VERSION 5.8 ;
BUSBITCHARS "[]" ;
DIVIDERCHAR "/" ;
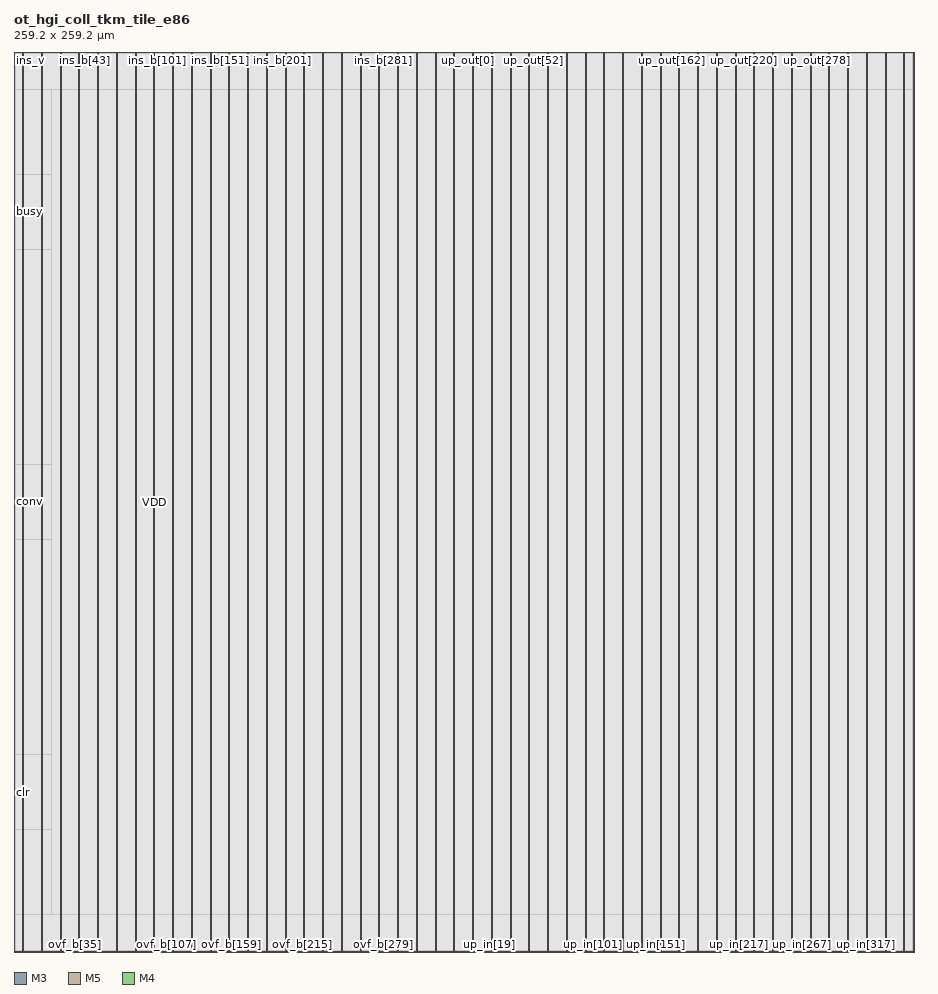
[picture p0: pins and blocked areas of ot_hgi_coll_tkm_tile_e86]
MACRO ot_hgi_coll_tkm_tile_e86
  CLASS BLOCK ;
  ORIGIN 0 0 ;
  FOREIGN ot_hgi_coll_tkm_tile_e86 0 0 ;
  SIZE 259.2 BY 259.2 ;
  SYMMETRY X Y ;
  PIN ins_v
    DIRECTION INPUT ;
    USE SIGNAL ;
    PORT
      LAYER M3 ;
        RECT 4.500 259.056 4.518 259.200 ;
    END
  END ins_v
  PIN ins_b[0]
    DIRECTION INPUT ;
    USE SIGNAL ;
    PORT
      LAYER M5 ;
        RECT 4.848 259.008 4.872 259.200 ;
    END
  END ins_b[0]
  PIN ins_b[1]
    DIRECTION INPUT ;
    USE SIGNAL ;
    PORT
      LAYER M3 ;
        RECT 5.220 259.056 5.238 259.200 ;
    END
  END ins_b[1]
  PIN ins_b[2]
    DIRECTION INPUT ;
    USE SIGNAL ;
    PORT
      LAYER M5 ;
        RECT 5.568 259.008 5.592 259.200 ;
    END
  END ins_b[2]
  PIN ins_b[3]
    DIRECTION INPUT ;
    USE SIGNAL ;
    PORT
      LAYER M3 ;
        RECT 5.940 259.056 5.958 259.200 ;
    END
  END ins_b[3]
  PIN ins_b[4]
    DIRECTION INPUT ;
    USE SIGNAL ;
    PORT
      LAYER M5 ;
        RECT 6.288 259.008 6.312 259.200 ;
    END
  END ins_b[4]
  PIN ins_b[5]
    DIRECTION INPUT ;
    USE SIGNAL ;
    PORT
      LAYER M3 ;
        RECT 6.660 259.056 6.678 259.200 ;
    END
  END ins_b[5]
  PIN ins_b[6]
    DIRECTION INPUT ;
    USE SIGNAL ;
    PORT
      LAYER M5 ;
        RECT 7.008 259.008 7.032 259.200 ;
    END
  END ins_b[6]
  PIN ins_b[7]
    DIRECTION INPUT ;
    USE SIGNAL ;
    PORT
      LAYER M3 ;
        RECT 7.380 259.056 7.398 259.200 ;
    END
  END ins_b[7]
  PIN ins_b[8]
    DIRECTION INPUT ;
    USE SIGNAL ;
    PORT
      LAYER M5 ;
        RECT 7.728 259.008 7.752 259.200 ;
    END
  END ins_b[8]
  PIN ins_b[9]
    DIRECTION INPUT ;
    USE SIGNAL ;
    PORT
      LAYER M3 ;
        RECT 8.100 259.056 8.118 259.200 ;
    END
  END ins_b[9]
  PIN ins_b[10]
    DIRECTION INPUT ;
    USE SIGNAL ;
    PORT
      LAYER M5 ;
        RECT 8.448 259.008 8.472 259.200 ;
    END
  END ins_b[10]
  PIN ins_b[11]
    DIRECTION INPUT ;
    USE SIGNAL ;
    PORT
      LAYER M3 ;
        RECT 8.820 259.056 8.838 259.200 ;
    END
  END ins_b[11]
  PIN ins_b[12]
    DIRECTION INPUT ;
    USE SIGNAL ;
    PORT
      LAYER M5 ;
        RECT 9.168 259.008 9.192 259.200 ;
    END
  END ins_b[12]
  PIN ins_b[13]
    DIRECTION INPUT ;
    USE SIGNAL ;
    PORT
      LAYER M3 ;
        RECT 9.540 259.056 9.558 259.200 ;
    END
  END ins_b[13]
  PIN ins_b[14]
    DIRECTION INPUT ;
    USE SIGNAL ;
    PORT
      LAYER M5 ;
        RECT 9.888 259.008 9.912 259.200 ;
    END
  END ins_b[14]
  PIN ins_b[15]
    DIRECTION INPUT ;
    USE SIGNAL ;
    PORT
      LAYER M3 ;
        RECT 10.260 259.056 10.278 259.200 ;
    END
  END ins_b[15]
  PIN ins_b[16]
    DIRECTION INPUT ;
    USE SIGNAL ;
    PORT
      LAYER M5 ;
        RECT 10.608 259.008 10.632 259.200 ;
    END
  END ins_b[16]
  PIN ins_b[17]
    DIRECTION INPUT ;
    USE SIGNAL ;
    PORT
      LAYER M3 ;
        RECT 10.980 259.056 10.998 259.200 ;
    END
  END ins_b[17]
  PIN ins_b[18]
    DIRECTION INPUT ;
    USE SIGNAL ;
    PORT
      LAYER M5 ;
        RECT 11.328 259.008 11.352 259.200 ;
    END
  END ins_b[18]
  PIN ins_b[19]
    DIRECTION INPUT ;
    USE SIGNAL ;
    PORT
      LAYER M3 ;
        RECT 11.700 259.056 11.718 259.200 ;
    END
  END ins_b[19]
  PIN ins_b[20]
    DIRECTION INPUT ;
    USE SIGNAL ;
    PORT
      LAYER M5 ;
        RECT 12.048 259.008 12.072 259.200 ;
    END
  END ins_b[20]
  PIN ins_b[21]
    DIRECTION INPUT ;
    USE SIGNAL ;
    PORT
      LAYER M3 ;
        RECT 12.420 259.056 12.438 259.200 ;
    END
  END ins_b[21]
  PIN ins_b[22]
    DIRECTION INPUT ;
    USE SIGNAL ;
    PORT
      LAYER M5 ;
        RECT 12.816 259.008 12.840 259.200 ;
    END
  END ins_b[22]
  PIN ins_b[23]
    DIRECTION INPUT ;
    USE SIGNAL ;
    PORT
      LAYER M3 ;
        RECT 13.140 259.056 13.158 259.200 ;
    END
  END ins_b[23]
  PIN ins_b[24]
    DIRECTION INPUT ;
    USE SIGNAL ;
    PORT
      LAYER M5 ;
        RECT 13.536 259.008 13.560 259.200 ;
    END
  END ins_b[24]
  PIN ins_b[25]
    DIRECTION INPUT ;
    USE SIGNAL ;
    PORT
      LAYER M3 ;
        RECT 13.896 259.056 13.914 259.200 ;
    END
  END ins_b[25]
  PIN ins_b[26]
    DIRECTION INPUT ;
    USE SIGNAL ;
    PORT
      LAYER M5 ;
        RECT 14.256 259.008 14.280 259.200 ;
    END
  END ins_b[26]
  PIN ins_b[27]
    DIRECTION INPUT ;
    USE SIGNAL ;
    PORT
      LAYER M3 ;
        RECT 14.616 259.056 14.634 259.200 ;
    END
  END ins_b[27]
  PIN ins_b[28]
    DIRECTION INPUT ;
    USE SIGNAL ;
    PORT
      LAYER M5 ;
        RECT 14.976 259.008 15.000 259.200 ;
    END
  END ins_b[28]
  PIN ins_b[29]
    DIRECTION INPUT ;
    USE SIGNAL ;
    PORT
      LAYER M3 ;
        RECT 15.336 259.056 15.354 259.200 ;
    END
  END ins_b[29]
  PIN ins_b[30]
    DIRECTION INPUT ;
    USE SIGNAL ;
    PORT
      LAYER M5 ;
        RECT 15.696 259.008 15.720 259.200 ;
    END
  END ins_b[30]
  PIN ins_b[31]
    DIRECTION INPUT ;
    USE SIGNAL ;
    PORT
      LAYER M3 ;
        RECT 16.056 259.056 16.074 259.200 ;
    END
  END ins_b[31]
  PIN ins_b[32]
    DIRECTION INPUT ;
    USE SIGNAL ;
    PORT
      LAYER M5 ;
        RECT 16.416 259.008 16.440 259.200 ;
    END
  END ins_b[32]
  PIN ins_b[33]
    DIRECTION INPUT ;
    USE SIGNAL ;
    PORT
      LAYER M3 ;
        RECT 16.776 259.056 16.794 259.200 ;
    END
  END ins_b[33]
  PIN ins_b[34]
    DIRECTION INPUT ;
    USE SIGNAL ;
    PORT
      LAYER M5 ;
        RECT 17.136 259.008 17.160 259.200 ;
    END
  END ins_b[34]
  PIN ins_b[35]
    DIRECTION INPUT ;
    USE SIGNAL ;
    PORT
      LAYER M3 ;
        RECT 17.496 259.056 17.514 259.200 ;
    END
  END ins_b[35]
  PIN ins_b[36]
    DIRECTION INPUT ;
    USE SIGNAL ;
    PORT
      LAYER M5 ;
        RECT 17.856 259.008 17.880 259.200 ;
    END
  END ins_b[36]
  PIN ins_b[37]
    DIRECTION INPUT ;
    USE SIGNAL ;
    PORT
      LAYER M3 ;
        RECT 18.216 259.056 18.234 259.200 ;
    END
  END ins_b[37]
  PIN ins_b[38]
    DIRECTION INPUT ;
    USE SIGNAL ;
    PORT
      LAYER M5 ;
        RECT 18.576 259.008 18.600 259.200 ;
    END
  END ins_b[38]
  PIN ins_b[39]
    DIRECTION INPUT ;
    USE SIGNAL ;
    PORT
      LAYER M3 ;
        RECT 18.936 259.056 18.954 259.200 ;
    END
  END ins_b[39]
  PIN ins_b[40]
    DIRECTION INPUT ;
    USE SIGNAL ;
    PORT
      LAYER M5 ;
        RECT 19.296 259.008 19.320 259.200 ;
    END
  END ins_b[40]
  PIN ins_b[41]
    DIRECTION INPUT ;
    USE SIGNAL ;
    PORT
      LAYER M3 ;
        RECT 19.656 259.056 19.674 259.200 ;
    END
  END ins_b[41]
  PIN ins_b[42]
    DIRECTION INPUT ;
    USE SIGNAL ;
    PORT
      LAYER M5 ;
        RECT 20.016 259.008 20.040 259.200 ;
    END
  END ins_b[42]
  PIN ins_b[43]
    DIRECTION INPUT ;
    USE SIGNAL ;
    PORT
      LAYER M3 ;
        RECT 20.376 259.056 20.394 259.200 ;
    END
  END ins_b[43]
  PIN ins_b[44]
    DIRECTION INPUT ;
    USE SIGNAL ;
    PORT
      LAYER M5 ;
        RECT 20.736 259.008 20.760 259.200 ;
    END
  END ins_b[44]
  PIN ins_b[45]
    DIRECTION INPUT ;
    USE SIGNAL ;
    PORT
      LAYER M3 ;
        RECT 21.096 259.056 21.114 259.200 ;
    END
  END ins_b[45]
  PIN ins_b[46]
    DIRECTION INPUT ;
    USE SIGNAL ;
    PORT
      LAYER M5 ;
        RECT 21.456 259.008 21.480 259.200 ;
    END
  END ins_b[46]
  PIN ins_b[47]
    DIRECTION INPUT ;
    USE SIGNAL ;
    PORT
      LAYER M3 ;
        RECT 21.816 259.056 21.834 259.200 ;
    END
  END ins_b[47]
  PIN ins_b[48]
    DIRECTION INPUT ;
    USE SIGNAL ;
    PORT
      LAYER M5 ;
        RECT 22.176 259.008 22.200 259.200 ;
    END
  END ins_b[48]
  PIN ins_b[49]
    DIRECTION INPUT ;
    USE SIGNAL ;
    PORT
      LAYER M3 ;
        RECT 22.536 259.056 22.554 259.200 ;
    END
  END ins_b[49]
  PIN ins_b[50]
    DIRECTION INPUT ;
    USE SIGNAL ;
    PORT
      LAYER M5 ;
        RECT 22.896 259.008 22.920 259.200 ;
    END
  END ins_b[50]
  PIN ins_b[51]
    DIRECTION INPUT ;
    USE SIGNAL ;
    PORT
      LAYER M3 ;
        RECT 23.256 259.056 23.274 259.200 ;
    END
  END ins_b[51]
  PIN ins_b[52]
    DIRECTION INPUT ;
    USE SIGNAL ;
    PORT
      LAYER M5 ;
        RECT 23.616 259.008 23.640 259.200 ;
    END
  END ins_b[52]
  PIN ins_b[53]
    DIRECTION INPUT ;
    USE SIGNAL ;
    PORT
      LAYER M3 ;
        RECT 23.976 259.056 23.994 259.200 ;
    END
  END ins_b[53]
  PIN ins_b[54]
    DIRECTION INPUT ;
    USE SIGNAL ;
    PORT
      LAYER M5 ;
        RECT 24.336 259.008 24.360 259.200 ;
    END
  END ins_b[54]
  PIN ins_b[55]
    DIRECTION INPUT ;
    USE SIGNAL ;
    PORT
      LAYER M3 ;
        RECT 24.696 259.056 24.714 259.200 ;
    END
  END ins_b[55]
  PIN ins_b[56]
    DIRECTION INPUT ;
    USE SIGNAL ;
    PORT
      LAYER M5 ;
        RECT 25.056 259.008 25.080 259.200 ;
    END
  END ins_b[56]
  PIN ins_b[57]
    DIRECTION INPUT ;
    USE SIGNAL ;
    PORT
      LAYER M3 ;
        RECT 25.416 259.056 25.434 259.200 ;
    END
  END ins_b[57]
  PIN ins_b[58]
    DIRECTION INPUT ;
    USE SIGNAL ;
    PORT
      LAYER M5 ;
        RECT 25.776 259.008 25.800 259.200 ;
    END
  END ins_b[58]
  PIN ins_b[59]
    DIRECTION INPUT ;
    USE SIGNAL ;
    PORT
      LAYER M3 ;
        RECT 26.136 259.056 26.154 259.200 ;
    END
  END ins_b[59]
  PIN ins_b[60]
    DIRECTION INPUT ;
    USE SIGNAL ;
    PORT
      LAYER M5 ;
        RECT 26.496 259.008 26.520 259.200 ;
    END
  END ins_b[60]
  PIN ins_b[61]
    DIRECTION INPUT ;
    USE SIGNAL ;
    PORT
      LAYER M3 ;
        RECT 26.892 259.056 26.910 259.200 ;
    END
  END ins_b[61]
  PIN ins_b[62]
    DIRECTION INPUT ;
    USE SIGNAL ;
    PORT
      LAYER M5 ;
        RECT 27.216 259.008 27.240 259.200 ;
    END
  END ins_b[62]
  PIN ins_b[63]
    DIRECTION INPUT ;
    USE SIGNAL ;
    PORT
      LAYER M3 ;
        RECT 27.612 259.056 27.630 259.200 ;
    END
  END ins_b[63]
  PIN ins_b[64]
    DIRECTION INPUT ;
    USE SIGNAL ;
    PORT
      LAYER M5 ;
        RECT 27.936 259.008 27.960 259.200 ;
    END
  END ins_b[64]
  PIN ins_b[65]
    DIRECTION INPUT ;
    USE SIGNAL ;
    PORT
      LAYER M3 ;
        RECT 28.332 259.056 28.350 259.200 ;
    END
  END ins_b[65]
  PIN ins_b[66]
    DIRECTION INPUT ;
    USE SIGNAL ;
    PORT
      LAYER M5 ;
        RECT 28.656 259.008 28.680 259.200 ;
    END
  END ins_b[66]
  PIN ins_b[67]
    DIRECTION INPUT ;
    USE SIGNAL ;
    PORT
      LAYER M3 ;
        RECT 29.052 259.056 29.070 259.200 ;
    END
  END ins_b[67]
  PIN ins_b[68]
    DIRECTION INPUT ;
    USE SIGNAL ;
    PORT
      LAYER M5 ;
        RECT 29.424 259.008 29.448 259.200 ;
    END
  END ins_b[68]
  PIN ins_b[69]
    DIRECTION INPUT ;
    USE SIGNAL ;
    PORT
      LAYER M3 ;
        RECT 29.772 259.056 29.790 259.200 ;
    END
  END ins_b[69]
  PIN ins_b[70]
    DIRECTION INPUT ;
    USE SIGNAL ;
    PORT
      LAYER M5 ;
        RECT 30.144 259.008 30.168 259.200 ;
    END
  END ins_b[70]
  PIN ins_b[71]
    DIRECTION INPUT ;
    USE SIGNAL ;
    PORT
      LAYER M3 ;
        RECT 30.492 259.056 30.510 259.200 ;
    END
  END ins_b[71]
  PIN ins_b[72]
    DIRECTION INPUT ;
    USE SIGNAL ;
    PORT
      LAYER M5 ;
        RECT 30.864 259.008 30.888 259.200 ;
    END
  END ins_b[72]
  PIN ins_b[73]
    DIRECTION INPUT ;
    USE SIGNAL ;
    PORT
      LAYER M3 ;
        RECT 31.212 259.056 31.230 259.200 ;
    END
  END ins_b[73]
  PIN ins_b[74]
    DIRECTION INPUT ;
    USE SIGNAL ;
    PORT
      LAYER M5 ;
        RECT 31.584 259.008 31.608 259.200 ;
    END
  END ins_b[74]
  PIN ins_b[75]
    DIRECTION INPUT ;
    USE SIGNAL ;
    PORT
      LAYER M3 ;
        RECT 31.932 259.056 31.950 259.200 ;
    END
  END ins_b[75]
  PIN ins_b[76]
    DIRECTION INPUT ;
    USE SIGNAL ;
    PORT
      LAYER M5 ;
        RECT 32.304 259.008 32.328 259.200 ;
    END
  END ins_b[76]
  PIN ins_b[77]
    DIRECTION INPUT ;
    USE SIGNAL ;
    PORT
      LAYER M3 ;
        RECT 32.652 259.056 32.670 259.200 ;
    END
  END ins_b[77]
  PIN ins_b[78]
    DIRECTION INPUT ;
    USE SIGNAL ;
    PORT
      LAYER M5 ;
        RECT 33.024 259.008 33.048 259.200 ;
    END
  END ins_b[78]
  PIN ins_b[79]
    DIRECTION INPUT ;
    USE SIGNAL ;
    PORT
      LAYER M3 ;
        RECT 33.372 259.056 33.390 259.200 ;
    END
  END ins_b[79]
  PIN ins_b[80]
    DIRECTION INPUT ;
    USE SIGNAL ;
    PORT
      LAYER M5 ;
        RECT 33.744 259.008 33.768 259.200 ;
    END
  END ins_b[80]
  PIN ins_b[81]
    DIRECTION INPUT ;
    USE SIGNAL ;
    PORT
      LAYER M3 ;
        RECT 34.092 259.056 34.110 259.200 ;
    END
  END ins_b[81]
  PIN ins_b[82]
    DIRECTION INPUT ;
    USE SIGNAL ;
    PORT
      LAYER M5 ;
        RECT 34.464 259.008 34.488 259.200 ;
    END
  END ins_b[82]
  PIN ins_b[83]
    DIRECTION INPUT ;
    USE SIGNAL ;
    PORT
      LAYER M3 ;
        RECT 34.812 259.056 34.830 259.200 ;
    END
  END ins_b[83]
  PIN ins_b[84]
    DIRECTION INPUT ;
    USE SIGNAL ;
    PORT
      LAYER M5 ;
        RECT 35.184 259.008 35.208 259.200 ;
    END
  END ins_b[84]
  PIN ins_b[85]
    DIRECTION INPUT ;
    USE SIGNAL ;
    PORT
      LAYER M3 ;
        RECT 35.532 259.056 35.550 259.200 ;
    END
  END ins_b[85]
  PIN ins_b[86]
    DIRECTION INPUT ;
    USE SIGNAL ;
    PORT
      LAYER M5 ;
        RECT 35.904 259.008 35.928 259.200 ;
    END
  END ins_b[86]
  PIN ins_b[87]
    DIRECTION INPUT ;
    USE SIGNAL ;
    PORT
      LAYER M3 ;
        RECT 36.252 259.056 36.270 259.200 ;
    END
  END ins_b[87]
  PIN ins_b[88]
    DIRECTION INPUT ;
    USE SIGNAL ;
    PORT
      LAYER M5 ;
        RECT 36.624 259.008 36.648 259.200 ;
    END
  END ins_b[88]
  PIN ins_b[89]
    DIRECTION INPUT ;
    USE SIGNAL ;
    PORT
      LAYER M3 ;
        RECT 36.972 259.056 36.990 259.200 ;
    END
  END ins_b[89]
  PIN ins_b[90]
    DIRECTION INPUT ;
    USE SIGNAL ;
    PORT
      LAYER M5 ;
        RECT 37.344 259.008 37.368 259.200 ;
    END
  END ins_b[90]
  PIN ins_b[91]
    DIRECTION INPUT ;
    USE SIGNAL ;
    PORT
      LAYER M3 ;
        RECT 37.692 259.056 37.710 259.200 ;
    END
  END ins_b[91]
  PIN ins_b[92]
    DIRECTION INPUT ;
    USE SIGNAL ;
    PORT
      LAYER M5 ;
        RECT 38.064 259.008 38.088 259.200 ;
    END
  END ins_b[92]
  PIN ins_b[93]
    DIRECTION INPUT ;
    USE SIGNAL ;
    PORT
      LAYER M3 ;
        RECT 38.412 259.056 38.430 259.200 ;
    END
  END ins_b[93]
  PIN ins_b[94]
    DIRECTION INPUT ;
    USE SIGNAL ;
    PORT
      LAYER M5 ;
        RECT 38.784 259.008 38.808 259.200 ;
    END
  END ins_b[94]
  PIN ins_b[95]
    DIRECTION INPUT ;
    USE SIGNAL ;
    PORT
      LAYER M3 ;
        RECT 39.168 259.056 39.186 259.200 ;
    END
  END ins_b[95]
  PIN ins_b[96]
    DIRECTION INPUT ;
    USE SIGNAL ;
    PORT
      LAYER M5 ;
        RECT 39.504 259.008 39.528 259.200 ;
    END
  END ins_b[96]
  PIN ins_b[97]
    DIRECTION INPUT ;
    USE SIGNAL ;
    PORT
      LAYER M3 ;
        RECT 39.888 259.056 39.906 259.200 ;
    END
  END ins_b[97]
  PIN ins_b[98]
    DIRECTION INPUT ;
    USE SIGNAL ;
    PORT
      LAYER M5 ;
        RECT 40.224 259.008 40.248 259.200 ;
    END
  END ins_b[98]
  PIN ins_b[99]
    DIRECTION INPUT ;
    USE SIGNAL ;
    PORT
      LAYER M3 ;
        RECT 40.608 259.056 40.626 259.200 ;
    END
  END ins_b[99]
  PIN ins_b[100]
    DIRECTION INPUT ;
    USE SIGNAL ;
    PORT
      LAYER M5 ;
        RECT 40.944 259.008 40.968 259.200 ;
    END
  END ins_b[100]
  PIN ins_b[101]
    DIRECTION INPUT ;
    USE SIGNAL ;
    PORT
      LAYER M3 ;
        RECT 41.328 259.056 41.346 259.200 ;
    END
  END ins_b[101]
  PIN ins_b[102]
    DIRECTION INPUT ;
    USE SIGNAL ;
    PORT
      LAYER M5 ;
        RECT 41.664 259.008 41.688 259.200 ;
    END
  END ins_b[102]
  PIN ins_b[103]
    DIRECTION INPUT ;
    USE SIGNAL ;
    PORT
      LAYER M3 ;
        RECT 42.048 259.056 42.066 259.200 ;
    END
  END ins_b[103]
  PIN ins_b[104]
    DIRECTION INPUT ;
    USE SIGNAL ;
    PORT
      LAYER M5 ;
        RECT 42.384 259.008 42.408 259.200 ;
    END
  END ins_b[104]
  PIN ins_b[105]
    DIRECTION INPUT ;
    USE SIGNAL ;
    PORT
      LAYER M3 ;
        RECT 42.768 259.056 42.786 259.200 ;
    END
  END ins_b[105]
  PIN ins_b[106]
    DIRECTION INPUT ;
    USE SIGNAL ;
    PORT
      LAYER M5 ;
        RECT 43.104 259.008 43.128 259.200 ;
    END
  END ins_b[106]
  PIN ins_b[107]
    DIRECTION INPUT ;
    USE SIGNAL ;
    PORT
      LAYER M3 ;
        RECT 43.488 259.056 43.506 259.200 ;
    END
  END ins_b[107]
  PIN ins_b[108]
    DIRECTION INPUT ;
    USE SIGNAL ;
    PORT
      LAYER M5 ;
        RECT 43.824 259.008 43.848 259.200 ;
    END
  END ins_b[108]
  PIN ins_b[109]
    DIRECTION INPUT ;
    USE SIGNAL ;
    PORT
      LAYER M3 ;
        RECT 44.208 259.056 44.226 259.200 ;
    END
  END ins_b[109]
  PIN ins_b[110]
    DIRECTION INPUT ;
    USE SIGNAL ;
    PORT
      LAYER M5 ;
        RECT 44.544 259.008 44.568 259.200 ;
    END
  END ins_b[110]
  PIN ins_b[111]
    DIRECTION INPUT ;
    USE SIGNAL ;
    PORT
      LAYER M3 ;
        RECT 44.928 259.056 44.946 259.200 ;
    END
  END ins_b[111]
  PIN ins_b[112]
    DIRECTION INPUT ;
    USE SIGNAL ;
    PORT
      LAYER M5 ;
        RECT 45.264 259.008 45.288 259.200 ;
    END
  END ins_b[112]
  PIN ins_b[113]
    DIRECTION INPUT ;
    USE SIGNAL ;
    PORT
      LAYER M3 ;
        RECT 45.648 259.056 45.666 259.200 ;
    END
  END ins_b[113]
  PIN ins_b[114]
    DIRECTION INPUT ;
    USE SIGNAL ;
    PORT
      LAYER M5 ;
        RECT 45.984 259.008 46.008 259.200 ;
    END
  END ins_b[114]
  PIN ins_b[115]
    DIRECTION INPUT ;
    USE SIGNAL ;
    PORT
      LAYER M3 ;
        RECT 46.368 259.056 46.386 259.200 ;
    END
  END ins_b[115]
  PIN ins_b[116]
    DIRECTION INPUT ;
    USE SIGNAL ;
    PORT
      LAYER M5 ;
        RECT 46.752 259.008 46.776 259.200 ;
    END
  END ins_b[116]
  PIN ins_b[117]
    DIRECTION INPUT ;
    USE SIGNAL ;
    PORT
      LAYER M3 ;
        RECT 47.088 259.056 47.106 259.200 ;
    END
  END ins_b[117]
  PIN ins_b[118]
    DIRECTION INPUT ;
    USE SIGNAL ;
    PORT
      LAYER M5 ;
        RECT 47.472 259.008 47.496 259.200 ;
    END
  END ins_b[118]
  PIN ins_b[119]
    DIRECTION INPUT ;
    USE SIGNAL ;
    PORT
      LAYER M3 ;
        RECT 47.808 259.056 47.826 259.200 ;
    END
  END ins_b[119]
  PIN ins_b[120]
    DIRECTION INPUT ;
    USE SIGNAL ;
    PORT
      LAYER M5 ;
        RECT 48.192 259.008 48.216 259.200 ;
    END
  END ins_b[120]
  PIN ins_b[121]
    DIRECTION INPUT ;
    USE SIGNAL ;
    PORT
      LAYER M3 ;
        RECT 48.528 259.056 48.546 259.200 ;
    END
  END ins_b[121]
  PIN ins_b[122]
    DIRECTION INPUT ;
    USE SIGNAL ;
    PORT
      LAYER M5 ;
        RECT 48.912 259.008 48.936 259.200 ;
    END
  END ins_b[122]
  PIN ins_b[123]
    DIRECTION INPUT ;
    USE SIGNAL ;
    PORT
      LAYER M3 ;
        RECT 49.248 259.056 49.266 259.200 ;
    END
  END ins_b[123]
  PIN ins_b[124]
    DIRECTION INPUT ;
    USE SIGNAL ;
    PORT
      LAYER M5 ;
        RECT 49.632 259.008 49.656 259.200 ;
    END
  END ins_b[124]
  PIN ins_b[125]
    DIRECTION INPUT ;
    USE SIGNAL ;
    PORT
      LAYER M3 ;
        RECT 49.968 259.056 49.986 259.200 ;
    END
  END ins_b[125]
  PIN ins_b[126]
    DIRECTION INPUT ;
    USE SIGNAL ;
    PORT
      LAYER M5 ;
        RECT 50.352 259.008 50.376 259.200 ;
    END
  END ins_b[126]
  PIN ins_b[127]
    DIRECTION INPUT ;
    USE SIGNAL ;
    PORT
      LAYER M3 ;
        RECT 50.688 259.056 50.706 259.200 ;
    END
  END ins_b[127]
  PIN ins_b[128]
    DIRECTION INPUT ;
    USE SIGNAL ;
    PORT
      LAYER M5 ;
        RECT 51.072 259.008 51.096 259.200 ;
    END
  END ins_b[128]
  PIN ins_b[129]
    DIRECTION INPUT ;
    USE SIGNAL ;
    PORT
      LAYER M3 ;
        RECT 51.444 259.056 51.462 259.200 ;
    END
  END ins_b[129]
  PIN ins_b[130]
    DIRECTION INPUT ;
    USE SIGNAL ;
    PORT
      LAYER M5 ;
        RECT 51.792 259.008 51.816 259.200 ;
    END
  END ins_b[130]
  PIN ins_b[131]
    DIRECTION INPUT ;
    USE SIGNAL ;
    PORT
      LAYER M3 ;
        RECT 52.164 259.056 52.182 259.200 ;
    END
  END ins_b[131]
  PIN ins_b[132]
    DIRECTION INPUT ;
    USE SIGNAL ;
    PORT
      LAYER M5 ;
        RECT 52.512 259.008 52.536 259.200 ;
    END
  END ins_b[132]
  PIN ins_b[133]
    DIRECTION INPUT ;
    USE SIGNAL ;
    PORT
      LAYER M3 ;
        RECT 52.884 259.056 52.902 259.200 ;
    END
  END ins_b[133]
  PIN ins_b[134]
    DIRECTION INPUT ;
    USE SIGNAL ;
    PORT
      LAYER M5 ;
        RECT 53.232 259.008 53.256 259.200 ;
    END
  END ins_b[134]
  PIN ins_b[135]
    DIRECTION INPUT ;
    USE SIGNAL ;
    PORT
      LAYER M3 ;
        RECT 53.604 259.056 53.622 259.200 ;
    END
  END ins_b[135]
  PIN ins_b[136]
    DIRECTION INPUT ;
    USE SIGNAL ;
    PORT
      LAYER M5 ;
        RECT 53.952 259.008 53.976 259.200 ;
    END
  END ins_b[136]
  PIN ins_b[137]
    DIRECTION INPUT ;
    USE SIGNAL ;
    PORT
      LAYER M3 ;
        RECT 54.324 259.056 54.342 259.200 ;
    END
  END ins_b[137]
  PIN ins_b[138]
    DIRECTION INPUT ;
    USE SIGNAL ;
    PORT
      LAYER M5 ;
        RECT 54.672 259.008 54.696 259.200 ;
    END
  END ins_b[138]
  PIN ins_b[139]
    DIRECTION INPUT ;
    USE SIGNAL ;
    PORT
      LAYER M3 ;
        RECT 55.044 259.056 55.062 259.200 ;
    END
  END ins_b[139]
  PIN ins_b[140]
    DIRECTION INPUT ;
    USE SIGNAL ;
    PORT
      LAYER M5 ;
        RECT 55.392 259.008 55.416 259.200 ;
    END
  END ins_b[140]
  PIN ins_b[141]
    DIRECTION INPUT ;
    USE SIGNAL ;
    PORT
      LAYER M3 ;
        RECT 55.764 259.056 55.782 259.200 ;
    END
  END ins_b[141]
  PIN ins_b[142]
    DIRECTION INPUT ;
    USE SIGNAL ;
    PORT
      LAYER M5 ;
        RECT 56.112 259.008 56.136 259.200 ;
    END
  END ins_b[142]
  PIN ins_b[143]
    DIRECTION INPUT ;
    USE SIGNAL ;
    PORT
      LAYER M3 ;
        RECT 56.484 259.056 56.502 259.200 ;
    END
  END ins_b[143]
  PIN ins_b[144]
    DIRECTION INPUT ;
    USE SIGNAL ;
    PORT
      LAYER M5 ;
        RECT 56.832 259.008 56.856 259.200 ;
    END
  END ins_b[144]
  PIN ins_b[145]
    DIRECTION INPUT ;
    USE SIGNAL ;
    PORT
      LAYER M3 ;
        RECT 57.204 259.056 57.222 259.200 ;
    END
  END ins_b[145]
  PIN ins_b[146]
    DIRECTION INPUT ;
    USE SIGNAL ;
    PORT
      LAYER M5 ;
        RECT 57.552 259.008 57.576 259.200 ;
    END
  END ins_b[146]
  PIN ins_b[147]
    DIRECTION INPUT ;
    USE SIGNAL ;
    PORT
      LAYER M3 ;
        RECT 57.924 259.056 57.942 259.200 ;
    END
  END ins_b[147]
  PIN ins_b[148]
    DIRECTION INPUT ;
    USE SIGNAL ;
    PORT
      LAYER M5 ;
        RECT 58.272 259.008 58.296 259.200 ;
    END
  END ins_b[148]
  PIN ins_b[149]
    DIRECTION INPUT ;
    USE SIGNAL ;
    PORT
      LAYER M3 ;
        RECT 58.644 259.056 58.662 259.200 ;
    END
  END ins_b[149]
  PIN ins_b[150]
    DIRECTION INPUT ;
    USE SIGNAL ;
    PORT
      LAYER M5 ;
        RECT 58.992 259.008 59.016 259.200 ;
    END
  END ins_b[150]
  PIN ins_b[151]
    DIRECTION INPUT ;
    USE SIGNAL ;
    PORT
      LAYER M3 ;
        RECT 59.364 259.056 59.382 259.200 ;
    END
  END ins_b[151]
  PIN ins_b[152]
    DIRECTION INPUT ;
    USE SIGNAL ;
    PORT
      LAYER M5 ;
        RECT 59.712 259.008 59.736 259.200 ;
    END
  END ins_b[152]
  PIN ins_b[153]
    DIRECTION INPUT ;
    USE SIGNAL ;
    PORT
      LAYER M3 ;
        RECT 60.084 259.056 60.102 259.200 ;
    END
  END ins_b[153]
  PIN ins_b[154]
    DIRECTION INPUT ;
    USE SIGNAL ;
    PORT
      LAYER M5 ;
        RECT 60.432 259.008 60.456 259.200 ;
    END
  END ins_b[154]
  PIN ins_b[155]
    DIRECTION INPUT ;
    USE SIGNAL ;
    PORT
      LAYER M3 ;
        RECT 60.804 259.056 60.822 259.200 ;
    END
  END ins_b[155]
  PIN ins_b[156]
    DIRECTION INPUT ;
    USE SIGNAL ;
    PORT
      LAYER M5 ;
        RECT 61.152 259.008 61.176 259.200 ;
    END
  END ins_b[156]
  PIN ins_b[157]
    DIRECTION INPUT ;
    USE SIGNAL ;
    PORT
      LAYER M3 ;
        RECT 61.524 259.056 61.542 259.200 ;
    END
  END ins_b[157]
  PIN ins_b[158]
    DIRECTION INPUT ;
    USE SIGNAL ;
    PORT
      LAYER M5 ;
        RECT 61.872 259.008 61.896 259.200 ;
    END
  END ins_b[158]
  PIN ins_b[159]
    DIRECTION INPUT ;
    USE SIGNAL ;
    PORT
      LAYER M3 ;
        RECT 62.244 259.056 62.262 259.200 ;
    END
  END ins_b[159]
  PIN ins_b[160]
    DIRECTION INPUT ;
    USE SIGNAL ;
    PORT
      LAYER M5 ;
        RECT 62.592 259.008 62.616 259.200 ;
    END
  END ins_b[160]
  PIN ins_b[161]
    DIRECTION INPUT ;
    USE SIGNAL ;
    PORT
      LAYER M3 ;
        RECT 62.964 259.056 62.982 259.200 ;
    END
  END ins_b[161]
  PIN ins_b[162]
    DIRECTION INPUT ;
    USE SIGNAL ;
    PORT
      LAYER M5 ;
        RECT 63.360 259.008 63.384 259.200 ;
    END
  END ins_b[162]
  PIN ins_b[163]
    DIRECTION INPUT ;
    USE SIGNAL ;
    PORT
      LAYER M3 ;
        RECT 63.684 259.056 63.702 259.200 ;
    END
  END ins_b[163]
  PIN ins_b[164]
    DIRECTION INPUT ;
    USE SIGNAL ;
    PORT
      LAYER M5 ;
        RECT 64.080 259.008 64.104 259.200 ;
    END
  END ins_b[164]
  PIN ins_b[165]
    DIRECTION INPUT ;
    USE SIGNAL ;
    PORT
      LAYER M3 ;
        RECT 64.440 259.056 64.458 259.200 ;
    END
  END ins_b[165]
  PIN ins_b[166]
    DIRECTION INPUT ;
    USE SIGNAL ;
    PORT
      LAYER M5 ;
        RECT 64.800 259.008 64.824 259.200 ;
    END
  END ins_b[166]
  PIN ins_b[167]
    DIRECTION INPUT ;
    USE SIGNAL ;
    PORT
      LAYER M3 ;
        RECT 65.160 259.056 65.178 259.200 ;
    END
  END ins_b[167]
  PIN ins_b[168]
    DIRECTION INPUT ;
    USE SIGNAL ;
    PORT
      LAYER M5 ;
        RECT 65.520 259.008 65.544 259.200 ;
    END
  END ins_b[168]
  PIN ins_b[169]
    DIRECTION INPUT ;
    USE SIGNAL ;
    PORT
      LAYER M3 ;
        RECT 65.880 259.056 65.898 259.200 ;
    END
  END ins_b[169]
  PIN ins_b[170]
    DIRECTION INPUT ;
    USE SIGNAL ;
    PORT
      LAYER M5 ;
        RECT 66.240 259.008 66.264 259.200 ;
    END
  END ins_b[170]
  PIN ins_b[171]
    DIRECTION INPUT ;
    USE SIGNAL ;
    PORT
      LAYER M3 ;
        RECT 66.600 259.056 66.618 259.200 ;
    END
  END ins_b[171]
  PIN ins_b[172]
    DIRECTION INPUT ;
    USE SIGNAL ;
    PORT
      LAYER M5 ;
        RECT 66.960 259.008 66.984 259.200 ;
    END
  END ins_b[172]
  PIN ins_b[173]
    DIRECTION INPUT ;
    USE SIGNAL ;
    PORT
      LAYER M3 ;
        RECT 67.320 259.056 67.338 259.200 ;
    END
  END ins_b[173]
  PIN ins_b[174]
    DIRECTION INPUT ;
    USE SIGNAL ;
    PORT
      LAYER M5 ;
        RECT 67.680 259.008 67.704 259.200 ;
    END
  END ins_b[174]
  PIN ins_b[175]
    DIRECTION INPUT ;
    USE SIGNAL ;
    PORT
      LAYER M3 ;
        RECT 68.040 259.056 68.058 259.200 ;
    END
  END ins_b[175]
  PIN ins_b[176]
    DIRECTION INPUT ;
    USE SIGNAL ;
    PORT
      LAYER M5 ;
        RECT 68.400 259.008 68.424 259.200 ;
    END
  END ins_b[176]
  PIN ins_b[177]
    DIRECTION INPUT ;
    USE SIGNAL ;
    PORT
      LAYER M3 ;
        RECT 68.760 259.056 68.778 259.200 ;
    END
  END ins_b[177]
  PIN ins_b[178]
    DIRECTION INPUT ;
    USE SIGNAL ;
    PORT
      LAYER M5 ;
        RECT 69.120 259.008 69.144 259.200 ;
    END
  END ins_b[178]
  PIN ins_b[179]
    DIRECTION INPUT ;
    USE SIGNAL ;
    PORT
      LAYER M3 ;
        RECT 69.480 259.056 69.498 259.200 ;
    END
  END ins_b[179]
  PIN ins_b[180]
    DIRECTION INPUT ;
    USE SIGNAL ;
    PORT
      LAYER M5 ;
        RECT 69.840 259.008 69.864 259.200 ;
    END
  END ins_b[180]
  PIN ins_b[181]
    DIRECTION INPUT ;
    USE SIGNAL ;
    PORT
      LAYER M3 ;
        RECT 70.200 259.056 70.218 259.200 ;
    END
  END ins_b[181]
  PIN ins_b[182]
    DIRECTION INPUT ;
    USE SIGNAL ;
    PORT
      LAYER M5 ;
        RECT 70.560 259.008 70.584 259.200 ;
    END
  END ins_b[182]
  PIN ins_b[183]
    DIRECTION INPUT ;
    USE SIGNAL ;
    PORT
      LAYER M3 ;
        RECT 70.920 259.056 70.938 259.200 ;
    END
  END ins_b[183]
  PIN ins_b[184]
    DIRECTION INPUT ;
    USE SIGNAL ;
    PORT
      LAYER M5 ;
        RECT 71.280 259.008 71.304 259.200 ;
    END
  END ins_b[184]
  PIN ins_b[185]
    DIRECTION INPUT ;
    USE SIGNAL ;
    PORT
      LAYER M3 ;
        RECT 71.640 259.056 71.658 259.200 ;
    END
  END ins_b[185]
  PIN ins_b[186]
    DIRECTION INPUT ;
    USE SIGNAL ;
    PORT
      LAYER M5 ;
        RECT 72.000 259.008 72.024 259.200 ;
    END
  END ins_b[186]
  PIN ins_b[187]
    DIRECTION INPUT ;
    USE SIGNAL ;
    PORT
      LAYER M3 ;
        RECT 72.360 259.056 72.378 259.200 ;
    END
  END ins_b[187]
  PIN ins_b[188]
    DIRECTION INPUT ;
    USE SIGNAL ;
    PORT
      LAYER M5 ;
        RECT 72.720 259.008 72.744 259.200 ;
    END
  END ins_b[188]
  PIN ins_b[189]
    DIRECTION INPUT ;
    USE SIGNAL ;
    PORT
      LAYER M3 ;
        RECT 73.080 259.056 73.098 259.200 ;
    END
  END ins_b[189]
  PIN ins_b[190]
    DIRECTION INPUT ;
    USE SIGNAL ;
    PORT
      LAYER M5 ;
        RECT 73.440 259.008 73.464 259.200 ;
    END
  END ins_b[190]
  PIN ins_b[191]
    DIRECTION INPUT ;
    USE SIGNAL ;
    PORT
      LAYER M3 ;
        RECT 73.800 259.056 73.818 259.200 ;
    END
  END ins_b[191]
  PIN ins_b[192]
    DIRECTION INPUT ;
    USE SIGNAL ;
    PORT
      LAYER M5 ;
        RECT 74.160 259.008 74.184 259.200 ;
    END
  END ins_b[192]
  PIN ins_b[193]
    DIRECTION INPUT ;
    USE SIGNAL ;
    PORT
      LAYER M3 ;
        RECT 74.520 259.056 74.538 259.200 ;
    END
  END ins_b[193]
  PIN ins_b[194]
    DIRECTION INPUT ;
    USE SIGNAL ;
    PORT
      LAYER M5 ;
        RECT 74.880 259.008 74.904 259.200 ;
    END
  END ins_b[194]
  PIN ins_b[195]
    DIRECTION INPUT ;
    USE SIGNAL ;
    PORT
      LAYER M3 ;
        RECT 75.240 259.056 75.258 259.200 ;
    END
  END ins_b[195]
  PIN ins_b[196]
    DIRECTION INPUT ;
    USE SIGNAL ;
    PORT
      LAYER M5 ;
        RECT 75.600 259.008 75.624 259.200 ;
    END
  END ins_b[196]
  PIN ins_b[197]
    DIRECTION INPUT ;
    USE SIGNAL ;
    PORT
      LAYER M3 ;
        RECT 75.960 259.056 75.978 259.200 ;
    END
  END ins_b[197]
  PIN ins_b[198]
    DIRECTION INPUT ;
    USE SIGNAL ;
    PORT
      LAYER M5 ;
        RECT 76.320 259.008 76.344 259.200 ;
    END
  END ins_b[198]
  PIN ins_b[199]
    DIRECTION INPUT ;
    USE SIGNAL ;
    PORT
      LAYER M3 ;
        RECT 76.716 259.056 76.734 259.200 ;
    END
  END ins_b[199]
  PIN ins_b[200]
    DIRECTION INPUT ;
    USE SIGNAL ;
    PORT
      LAYER M5 ;
        RECT 77.040 259.008 77.064 259.200 ;
    END
  END ins_b[200]
  PIN ins_b[201]
    DIRECTION INPUT ;
    USE SIGNAL ;
    PORT
      LAYER M3 ;
        RECT 77.436 259.056 77.454 259.200 ;
    END
  END ins_b[201]
  PIN ins_b[202]
    DIRECTION INPUT ;
    USE SIGNAL ;
    PORT
      LAYER M5 ;
        RECT 77.760 259.008 77.784 259.200 ;
    END
  END ins_b[202]
  PIN ins_b[203]
    DIRECTION INPUT ;
    USE SIGNAL ;
    PORT
      LAYER M3 ;
        RECT 78.156 259.056 78.174 259.200 ;
    END
  END ins_b[203]
  PIN ins_b[204]
    DIRECTION INPUT ;
    USE SIGNAL ;
    PORT
      LAYER M5 ;
        RECT 78.480 259.008 78.504 259.200 ;
    END
  END ins_b[204]
  PIN ins_b[205]
    DIRECTION INPUT ;
    USE SIGNAL ;
    PORT
      LAYER M3 ;
        RECT 78.876 259.056 78.894 259.200 ;
    END
  END ins_b[205]
  PIN ins_b[206]
    DIRECTION INPUT ;
    USE SIGNAL ;
    PORT
      LAYER M5 ;
        RECT 79.200 259.008 79.224 259.200 ;
    END
  END ins_b[206]
  PIN ins_b[207]
    DIRECTION INPUT ;
    USE SIGNAL ;
    PORT
      LAYER M3 ;
        RECT 79.596 259.056 79.614 259.200 ;
    END
  END ins_b[207]
  PIN ins_b[208]
    DIRECTION INPUT ;
    USE SIGNAL ;
    PORT
      LAYER M5 ;
        RECT 79.968 259.008 79.992 259.200 ;
    END
  END ins_b[208]
  PIN ins_b[209]
    DIRECTION INPUT ;
    USE SIGNAL ;
    PORT
      LAYER M3 ;
        RECT 80.316 259.056 80.334 259.200 ;
    END
  END ins_b[209]
  PIN ins_b[210]
    DIRECTION INPUT ;
    USE SIGNAL ;
    PORT
      LAYER M5 ;
        RECT 80.688 259.008 80.712 259.200 ;
    END
  END ins_b[210]
  PIN ins_b[211]
    DIRECTION INPUT ;
    USE SIGNAL ;
    PORT
      LAYER M3 ;
        RECT 81.036 259.056 81.054 259.200 ;
    END
  END ins_b[211]
  PIN ins_b[212]
    DIRECTION INPUT ;
    USE SIGNAL ;
    PORT
      LAYER M5 ;
        RECT 81.408 259.008 81.432 259.200 ;
    END
  END ins_b[212]
  PIN ins_b[213]
    DIRECTION INPUT ;
    USE SIGNAL ;
    PORT
      LAYER M3 ;
        RECT 81.756 259.056 81.774 259.200 ;
    END
  END ins_b[213]
  PIN ins_b[214]
    DIRECTION INPUT ;
    USE SIGNAL ;
    PORT
      LAYER M5 ;
        RECT 82.128 259.008 82.152 259.200 ;
    END
  END ins_b[214]
  PIN ins_b[215]
    DIRECTION INPUT ;
    USE SIGNAL ;
    PORT
      LAYER M3 ;
        RECT 82.476 259.056 82.494 259.200 ;
    END
  END ins_b[215]
  PIN ins_b[216]
    DIRECTION INPUT ;
    USE SIGNAL ;
    PORT
      LAYER M5 ;
        RECT 82.848 259.008 82.872 259.200 ;
    END
  END ins_b[216]
  PIN ins_b[217]
    DIRECTION INPUT ;
    USE SIGNAL ;
    PORT
      LAYER M3 ;
        RECT 83.196 259.056 83.214 259.200 ;
    END
  END ins_b[217]
  PIN ins_b[218]
    DIRECTION INPUT ;
    USE SIGNAL ;
    PORT
      LAYER M5 ;
        RECT 83.568 259.008 83.592 259.200 ;
    END
  END ins_b[218]
  PIN ins_b[219]
    DIRECTION INPUT ;
    USE SIGNAL ;
    PORT
      LAYER M3 ;
        RECT 83.916 259.056 83.934 259.200 ;
    END
  END ins_b[219]
  PIN ins_b[220]
    DIRECTION INPUT ;
    USE SIGNAL ;
    PORT
      LAYER M5 ;
        RECT 84.288 259.008 84.312 259.200 ;
    END
  END ins_b[220]
  PIN ins_b[221]
    DIRECTION INPUT ;
    USE SIGNAL ;
    PORT
      LAYER M3 ;
        RECT 84.636 259.056 84.654 259.200 ;
    END
  END ins_b[221]
  PIN ins_b[222]
    DIRECTION INPUT ;
    USE SIGNAL ;
    PORT
      LAYER M5 ;
        RECT 85.008 259.008 85.032 259.200 ;
    END
  END ins_b[222]
  PIN ins_b[223]
    DIRECTION INPUT ;
    USE SIGNAL ;
    PORT
      LAYER M3 ;
        RECT 85.356 259.056 85.374 259.200 ;
    END
  END ins_b[223]
  PIN ins_b[224]
    DIRECTION INPUT ;
    USE SIGNAL ;
    PORT
      LAYER M5 ;
        RECT 85.728 259.008 85.752 259.200 ;
    END
  END ins_b[224]
  PIN ins_b[225]
    DIRECTION INPUT ;
    USE SIGNAL ;
    PORT
      LAYER M3 ;
        RECT 86.076 259.056 86.094 259.200 ;
    END
  END ins_b[225]
  PIN ins_b[226]
    DIRECTION INPUT ;
    USE SIGNAL ;
    PORT
      LAYER M5 ;
        RECT 86.448 259.008 86.472 259.200 ;
    END
  END ins_b[226]
  PIN ins_b[227]
    DIRECTION INPUT ;
    USE SIGNAL ;
    PORT
      LAYER M3 ;
        RECT 86.796 259.056 86.814 259.200 ;
    END
  END ins_b[227]
  PIN ins_b[228]
    DIRECTION INPUT ;
    USE SIGNAL ;
    PORT
      LAYER M5 ;
        RECT 87.168 259.008 87.192 259.200 ;
    END
  END ins_b[228]
  PIN ins_b[229]
    DIRECTION INPUT ;
    USE SIGNAL ;
    PORT
      LAYER M3 ;
        RECT 87.516 259.056 87.534 259.200 ;
    END
  END ins_b[229]
  PIN ins_b[230]
    DIRECTION INPUT ;
    USE SIGNAL ;
    PORT
      LAYER M5 ;
        RECT 87.888 259.008 87.912 259.200 ;
    END
  END ins_b[230]
  PIN ins_b[231]
    DIRECTION INPUT ;
    USE SIGNAL ;
    PORT
      LAYER M3 ;
        RECT 88.236 259.056 88.254 259.200 ;
    END
  END ins_b[231]
  PIN ins_b[232]
    DIRECTION INPUT ;
    USE SIGNAL ;
    PORT
      LAYER M5 ;
        RECT 88.608 259.008 88.632 259.200 ;
    END
  END ins_b[232]
  PIN ins_b[233]
    DIRECTION INPUT ;
    USE SIGNAL ;
    PORT
      LAYER M3 ;
        RECT 88.992 259.056 89.010 259.200 ;
    END
  END ins_b[233]
  PIN ins_b[234]
    DIRECTION INPUT ;
    USE SIGNAL ;
    PORT
      LAYER M5 ;
        RECT 89.328 259.008 89.352 259.200 ;
    END
  END ins_b[234]
  PIN ins_b[235]
    DIRECTION INPUT ;
    USE SIGNAL ;
    PORT
      LAYER M3 ;
        RECT 89.712 259.056 89.730 259.200 ;
    END
  END ins_b[235]
  PIN ins_b[236]
    DIRECTION INPUT ;
    USE SIGNAL ;
    PORT
      LAYER M5 ;
        RECT 90.048 259.008 90.072 259.200 ;
    END
  END ins_b[236]
  PIN ins_b[237]
    DIRECTION INPUT ;
    USE SIGNAL ;
    PORT
      LAYER M3 ;
        RECT 90.432 259.056 90.450 259.200 ;
    END
  END ins_b[237]
  PIN ins_b[238]
    DIRECTION INPUT ;
    USE SIGNAL ;
    PORT
      LAYER M5 ;
        RECT 90.768 259.008 90.792 259.200 ;
    END
  END ins_b[238]
  PIN ins_b[239]
    DIRECTION INPUT ;
    USE SIGNAL ;
    PORT
      LAYER M3 ;
        RECT 91.152 259.056 91.170 259.200 ;
    END
  END ins_b[239]
  PIN ins_b[240]
    DIRECTION INPUT ;
    USE SIGNAL ;
    PORT
      LAYER M5 ;
        RECT 91.488 259.008 91.512 259.200 ;
    END
  END ins_b[240]
  PIN ins_b[241]
    DIRECTION INPUT ;
    USE SIGNAL ;
    PORT
      LAYER M3 ;
        RECT 91.872 259.056 91.890 259.200 ;
    END
  END ins_b[241]
  PIN ins_b[242]
    DIRECTION INPUT ;
    USE SIGNAL ;
    PORT
      LAYER M5 ;
        RECT 92.208 259.008 92.232 259.200 ;
    END
  END ins_b[242]
  PIN ins_b[243]
    DIRECTION INPUT ;
    USE SIGNAL ;
    PORT
      LAYER M3 ;
        RECT 92.592 259.056 92.610 259.200 ;
    END
  END ins_b[243]
  PIN ins_b[244]
    DIRECTION INPUT ;
    USE SIGNAL ;
    PORT
      LAYER M5 ;
        RECT 92.928 259.008 92.952 259.200 ;
    END
  END ins_b[244]
  PIN ins_b[245]
    DIRECTION INPUT ;
    USE SIGNAL ;
    PORT
      LAYER M3 ;
        RECT 93.312 259.056 93.330 259.200 ;
    END
  END ins_b[245]
  PIN ins_b[246]
    DIRECTION INPUT ;
    USE SIGNAL ;
    PORT
      LAYER M5 ;
        RECT 93.648 259.008 93.672 259.200 ;
    END
  END ins_b[246]
  PIN ins_b[247]
    DIRECTION INPUT ;
    USE SIGNAL ;
    PORT
      LAYER M3 ;
        RECT 94.032 259.056 94.050 259.200 ;
    END
  END ins_b[247]
  PIN ins_b[248]
    DIRECTION INPUT ;
    USE SIGNAL ;
    PORT
      LAYER M5 ;
        RECT 94.368 259.008 94.392 259.200 ;
    END
  END ins_b[248]
  PIN ins_b[249]
    DIRECTION INPUT ;
    USE SIGNAL ;
    PORT
      LAYER M3 ;
        RECT 94.752 259.056 94.770 259.200 ;
    END
  END ins_b[249]
  PIN ins_b[250]
    DIRECTION INPUT ;
    USE SIGNAL ;
    PORT
      LAYER M5 ;
        RECT 95.088 259.008 95.112 259.200 ;
    END
  END ins_b[250]
  PIN ins_b[251]
    DIRECTION INPUT ;
    USE SIGNAL ;
    PORT
      LAYER M3 ;
        RECT 95.472 259.056 95.490 259.200 ;
    END
  END ins_b[251]
  PIN ins_b[252]
    DIRECTION INPUT ;
    USE SIGNAL ;
    PORT
      LAYER M5 ;
        RECT 95.808 259.008 95.832 259.200 ;
    END
  END ins_b[252]
  PIN ins_b[253]
    DIRECTION INPUT ;
    USE SIGNAL ;
    PORT
      LAYER M3 ;
        RECT 96.192 259.056 96.210 259.200 ;
    END
  END ins_b[253]
  PIN ins_b[254]
    DIRECTION INPUT ;
    USE SIGNAL ;
    PORT
      LAYER M5 ;
        RECT 96.576 259.008 96.600 259.200 ;
    END
  END ins_b[254]
  PIN ins_b[255]
    DIRECTION INPUT ;
    USE SIGNAL ;
    PORT
      LAYER M3 ;
        RECT 96.912 259.056 96.930 259.200 ;
    END
  END ins_b[255]
  PIN ins_b[256]
    DIRECTION INPUT ;
    USE SIGNAL ;
    PORT
      LAYER M5 ;
        RECT 97.296 259.008 97.320 259.200 ;
    END
  END ins_b[256]
  PIN ins_b[257]
    DIRECTION INPUT ;
    USE SIGNAL ;
    PORT
      LAYER M3 ;
        RECT 97.632 259.056 97.650 259.200 ;
    END
  END ins_b[257]
  PIN ins_b[258]
    DIRECTION INPUT ;
    USE SIGNAL ;
    PORT
      LAYER M5 ;
        RECT 98.016 259.008 98.040 259.200 ;
    END
  END ins_b[258]
  PIN ins_b[259]
    DIRECTION INPUT ;
    USE SIGNAL ;
    PORT
      LAYER M3 ;
        RECT 98.352 259.056 98.370 259.200 ;
    END
  END ins_b[259]
  PIN ins_b[260]
    DIRECTION INPUT ;
    USE SIGNAL ;
    PORT
      LAYER M5 ;
        RECT 98.736 259.008 98.760 259.200 ;
    END
  END ins_b[260]
  PIN ins_b[261]
    DIRECTION INPUT ;
    USE SIGNAL ;
    PORT
      LAYER M3 ;
        RECT 99.072 259.056 99.090 259.200 ;
    END
  END ins_b[261]
  PIN ins_b[262]
    DIRECTION INPUT ;
    USE SIGNAL ;
    PORT
      LAYER M5 ;
        RECT 99.456 259.008 99.480 259.200 ;
    END
  END ins_b[262]
  PIN ins_b[263]
    DIRECTION INPUT ;
    USE SIGNAL ;
    PORT
      LAYER M3 ;
        RECT 99.792 259.056 99.810 259.200 ;
    END
  END ins_b[263]
  PIN ins_b[264]
    DIRECTION INPUT ;
    USE SIGNAL ;
    PORT
      LAYER M5 ;
        RECT 100.176 259.008 100.200 259.200 ;
    END
  END ins_b[264]
  PIN ins_b[265]
    DIRECTION INPUT ;
    USE SIGNAL ;
    PORT
      LAYER M3 ;
        RECT 100.512 259.056 100.530 259.200 ;
    END
  END ins_b[265]
  PIN ins_b[266]
    DIRECTION INPUT ;
    USE SIGNAL ;
    PORT
      LAYER M5 ;
        RECT 100.896 259.008 100.920 259.200 ;
    END
  END ins_b[266]
  PIN ins_b[267]
    DIRECTION INPUT ;
    USE SIGNAL ;
    PORT
      LAYER M3 ;
        RECT 101.232 259.056 101.250 259.200 ;
    END
  END ins_b[267]
  PIN ins_b[268]
    DIRECTION INPUT ;
    USE SIGNAL ;
    PORT
      LAYER M5 ;
        RECT 101.616 259.008 101.640 259.200 ;
    END
  END ins_b[268]
  PIN ins_b[269]
    DIRECTION INPUT ;
    USE SIGNAL ;
    PORT
      LAYER M3 ;
        RECT 101.988 259.056 102.006 259.200 ;
    END
  END ins_b[269]
  PIN ins_b[270]
    DIRECTION INPUT ;
    USE SIGNAL ;
    PORT
      LAYER M5 ;
        RECT 102.336 259.008 102.360 259.200 ;
    END
  END ins_b[270]
  PIN ins_b[271]
    DIRECTION INPUT ;
    USE SIGNAL ;
    PORT
      LAYER M3 ;
        RECT 102.708 259.056 102.726 259.200 ;
    END
  END ins_b[271]
  PIN ins_b[272]
    DIRECTION INPUT ;
    USE SIGNAL ;
    PORT
      LAYER M5 ;
        RECT 103.056 259.008 103.080 259.200 ;
    END
  END ins_b[272]
  PIN ins_b[273]
    DIRECTION INPUT ;
    USE SIGNAL ;
    PORT
      LAYER M3 ;
        RECT 103.428 259.056 103.446 259.200 ;
    END
  END ins_b[273]
  PIN ins_b[274]
    DIRECTION INPUT ;
    USE SIGNAL ;
    PORT
      LAYER M5 ;
        RECT 103.776 259.008 103.800 259.200 ;
    END
  END ins_b[274]
  PIN ins_b[275]
    DIRECTION INPUT ;
    USE SIGNAL ;
    PORT
      LAYER M3 ;
        RECT 104.148 259.056 104.166 259.200 ;
    END
  END ins_b[275]
  PIN ins_b[276]
    DIRECTION INPUT ;
    USE SIGNAL ;
    PORT
      LAYER M5 ;
        RECT 104.496 259.008 104.520 259.200 ;
    END
  END ins_b[276]
  PIN ins_b[277]
    DIRECTION INPUT ;
    USE SIGNAL ;
    PORT
      LAYER M3 ;
        RECT 104.868 259.056 104.886 259.200 ;
    END
  END ins_b[277]
  PIN ins_b[278]
    DIRECTION INPUT ;
    USE SIGNAL ;
    PORT
      LAYER M5 ;
        RECT 105.216 259.008 105.240 259.200 ;
    END
  END ins_b[278]
  PIN ins_b[279]
    DIRECTION INPUT ;
    USE SIGNAL ;
    PORT
      LAYER M3 ;
        RECT 105.588 259.056 105.606 259.200 ;
    END
  END ins_b[279]
  PIN ins_b[280]
    DIRECTION INPUT ;
    USE SIGNAL ;
    PORT
      LAYER M5 ;
        RECT 105.936 259.008 105.960 259.200 ;
    END
  END ins_b[280]
  PIN ins_b[281]
    DIRECTION INPUT ;
    USE SIGNAL ;
    PORT
      LAYER M3 ;
        RECT 106.308 259.056 106.326 259.200 ;
    END
  END ins_b[281]
  PIN ins_b[282]
    DIRECTION INPUT ;
    USE SIGNAL ;
    PORT
      LAYER M5 ;
        RECT 106.656 259.008 106.680 259.200 ;
    END
  END ins_b[282]
  PIN ins_b[283]
    DIRECTION INPUT ;
    USE SIGNAL ;
    PORT
      LAYER M3 ;
        RECT 107.028 259.056 107.046 259.200 ;
    END
  END ins_b[283]
  PIN ins_b[284]
    DIRECTION INPUT ;
    USE SIGNAL ;
    PORT
      LAYER M5 ;
        RECT 107.376 259.008 107.400 259.200 ;
    END
  END ins_b[284]
  PIN ins_b[285]
    DIRECTION INPUT ;
    USE SIGNAL ;
    PORT
      LAYER M3 ;
        RECT 107.748 259.056 107.766 259.200 ;
    END
  END ins_b[285]
  PIN ins_b[286]
    DIRECTION INPUT ;
    USE SIGNAL ;
    PORT
      LAYER M5 ;
        RECT 108.096 259.008 108.120 259.200 ;
    END
  END ins_b[286]
  PIN ins_b[287]
    DIRECTION INPUT ;
    USE SIGNAL ;
    PORT
      LAYER M3 ;
        RECT 108.468 259.056 108.486 259.200 ;
    END
  END ins_b[287]
  PIN ins_b[288]
    DIRECTION INPUT ;
    USE SIGNAL ;
    PORT
      LAYER M5 ;
        RECT 108.816 259.008 108.840 259.200 ;
    END
  END ins_b[288]
  PIN ins_b[289]
    DIRECTION INPUT ;
    USE SIGNAL ;
    PORT
      LAYER M3 ;
        RECT 109.188 259.056 109.206 259.200 ;
    END
  END ins_b[289]
  PIN ins_b[290]
    DIRECTION INPUT ;
    USE SIGNAL ;
    PORT
      LAYER M5 ;
        RECT 109.536 259.008 109.560 259.200 ;
    END
  END ins_b[290]
  PIN ins_b[291]
    DIRECTION INPUT ;
    USE SIGNAL ;
    PORT
      LAYER M3 ;
        RECT 109.908 259.056 109.926 259.200 ;
    END
  END ins_b[291]
  PIN ins_b[292]
    DIRECTION INPUT ;
    USE SIGNAL ;
    PORT
      LAYER M5 ;
        RECT 110.256 259.008 110.280 259.200 ;
    END
  END ins_b[292]
  PIN ins_b[293]
    DIRECTION INPUT ;
    USE SIGNAL ;
    PORT
      LAYER M3 ;
        RECT 110.628 259.056 110.646 259.200 ;
    END
  END ins_b[293]
  PIN ins_b[294]
    DIRECTION INPUT ;
    USE SIGNAL ;
    PORT
      LAYER M5 ;
        RECT 110.976 259.008 111.000 259.200 ;
    END
  END ins_b[294]
  PIN ins_b[295]
    DIRECTION INPUT ;
    USE SIGNAL ;
    PORT
      LAYER M3 ;
        RECT 111.348 259.056 111.366 259.200 ;
    END
  END ins_b[295]
  PIN ins_b[296]
    DIRECTION INPUT ;
    USE SIGNAL ;
    PORT
      LAYER M5 ;
        RECT 111.696 259.008 111.720 259.200 ;
    END
  END ins_b[296]
  PIN ins_b[297]
    DIRECTION INPUT ;
    USE SIGNAL ;
    PORT
      LAYER M3 ;
        RECT 112.068 259.056 112.086 259.200 ;
    END
  END ins_b[297]
  PIN ins_b[298]
    DIRECTION INPUT ;
    USE SIGNAL ;
    PORT
      LAYER M5 ;
        RECT 112.416 259.008 112.440 259.200 ;
    END
  END ins_b[298]
  PIN ins_b[299]
    DIRECTION INPUT ;
    USE SIGNAL ;
    PORT
      LAYER M3 ;
        RECT 112.788 259.056 112.806 259.200 ;
    END
  END ins_b[299]
  PIN ins_b[300]
    DIRECTION INPUT ;
    USE SIGNAL ;
    PORT
      LAYER M5 ;
        RECT 113.184 259.008 113.208 259.200 ;
    END
  END ins_b[300]
  PIN ins_b[301]
    DIRECTION INPUT ;
    USE SIGNAL ;
    PORT
      LAYER M3 ;
        RECT 113.508 259.056 113.526 259.200 ;
    END
  END ins_b[301]
  PIN ins_b[302]
    DIRECTION INPUT ;
    USE SIGNAL ;
    PORT
      LAYER M5 ;
        RECT 113.904 259.008 113.928 259.200 ;
    END
  END ins_b[302]
  PIN ins_b[303]
    DIRECTION INPUT ;
    USE SIGNAL ;
    PORT
      LAYER M3 ;
        RECT 114.264 259.056 114.282 259.200 ;
    END
  END ins_b[303]
  PIN ins_b[304]
    DIRECTION INPUT ;
    USE SIGNAL ;
    PORT
      LAYER M5 ;
        RECT 114.624 259.008 114.648 259.200 ;
    END
  END ins_b[304]
  PIN ins_b[305]
    DIRECTION INPUT ;
    USE SIGNAL ;
    PORT
      LAYER M3 ;
        RECT 114.984 259.056 115.002 259.200 ;
    END
  END ins_b[305]
  PIN ins_b[306]
    DIRECTION INPUT ;
    USE SIGNAL ;
    PORT
      LAYER M5 ;
        RECT 115.344 259.008 115.368 259.200 ;
    END
  END ins_b[306]
  PIN ins_b[307]
    DIRECTION INPUT ;
    USE SIGNAL ;
    PORT
      LAYER M3 ;
        RECT 115.704 259.056 115.722 259.200 ;
    END
  END ins_b[307]
  PIN ins_b[308]
    DIRECTION INPUT ;
    USE SIGNAL ;
    PORT
      LAYER M5 ;
        RECT 116.064 259.008 116.088 259.200 ;
    END
  END ins_b[308]
  PIN ins_b[309]
    DIRECTION INPUT ;
    USE SIGNAL ;
    PORT
      LAYER M3 ;
        RECT 116.424 259.056 116.442 259.200 ;
    END
  END ins_b[309]
  PIN ins_b[310]
    DIRECTION INPUT ;
    USE SIGNAL ;
    PORT
      LAYER M5 ;
        RECT 116.784 259.008 116.808 259.200 ;
    END
  END ins_b[310]
  PIN ins_b[311]
    DIRECTION INPUT ;
    USE SIGNAL ;
    PORT
      LAYER M3 ;
        RECT 117.144 259.056 117.162 259.200 ;
    END
  END ins_b[311]
  PIN ins_b[312]
    DIRECTION INPUT ;
    USE SIGNAL ;
    PORT
      LAYER M5 ;
        RECT 117.504 259.008 117.528 259.200 ;
    END
  END ins_b[312]
  PIN ins_b[313]
    DIRECTION INPUT ;
    USE SIGNAL ;
    PORT
      LAYER M3 ;
        RECT 117.864 259.056 117.882 259.200 ;
    END
  END ins_b[313]
  PIN ins_b[314]
    DIRECTION INPUT ;
    USE SIGNAL ;
    PORT
      LAYER M5 ;
        RECT 118.224 259.008 118.248 259.200 ;
    END
  END ins_b[314]
  PIN ins_b[315]
    DIRECTION INPUT ;
    USE SIGNAL ;
    PORT
      LAYER M3 ;
        RECT 118.584 259.056 118.602 259.200 ;
    END
  END ins_b[315]
  PIN ins_b[316]
    DIRECTION INPUT ;
    USE SIGNAL ;
    PORT
      LAYER M5 ;
        RECT 118.944 259.008 118.968 259.200 ;
    END
  END ins_b[316]
  PIN ins_b[317]
    DIRECTION INPUT ;
    USE SIGNAL ;
    PORT
      LAYER M3 ;
        RECT 119.304 259.056 119.322 259.200 ;
    END
  END ins_b[317]
  PIN ins_b[318]
    DIRECTION INPUT ;
    USE SIGNAL ;
    PORT
      LAYER M5 ;
        RECT 119.664 259.008 119.688 259.200 ;
    END
  END ins_b[318]
  PIN ins_b[319]
    DIRECTION INPUT ;
    USE SIGNAL ;
    PORT
      LAYER M3 ;
        RECT 120.024 259.056 120.042 259.200 ;
    END
  END ins_b[319]
  PIN ins_b[320]
    DIRECTION INPUT ;
    USE SIGNAL ;
    PORT
      LAYER M5 ;
        RECT 120.384 259.008 120.408 259.200 ;
    END
  END ins_b[320]
  PIN ins_b[321]
    DIRECTION INPUT ;
    USE SIGNAL ;
    PORT
      LAYER M3 ;
        RECT 120.744 259.056 120.762 259.200 ;
    END
  END ins_b[321]
  PIN ins_b[322]
    DIRECTION INPUT ;
    USE SIGNAL ;
    PORT
      LAYER M5 ;
        RECT 121.104 259.008 121.128 259.200 ;
    END
  END ins_b[322]
  PIN ins_b[323]
    DIRECTION INPUT ;
    USE SIGNAL ;
    PORT
      LAYER M3 ;
        RECT 121.464 259.056 121.482 259.200 ;
    END
  END ins_b[323]
  PIN ins_b[324]
    DIRECTION INPUT ;
    USE SIGNAL ;
    PORT
      LAYER M5 ;
        RECT 121.824 259.008 121.848 259.200 ;
    END
  END ins_b[324]
  PIN ins_b[325]
    DIRECTION INPUT ;
    USE SIGNAL ;
    PORT
      LAYER M3 ;
        RECT 122.184 259.056 122.202 259.200 ;
    END
  END ins_b[325]
  PIN ins_b[326]
    DIRECTION INPUT ;
    USE SIGNAL ;
    PORT
      LAYER M5 ;
        RECT 122.544 259.008 122.568 259.200 ;
    END
  END ins_b[326]
  PIN ins_b[327]
    DIRECTION INPUT ;
    USE SIGNAL ;
    PORT
      LAYER M3 ;
        RECT 122.904 259.056 122.922 259.200 ;
    END
  END ins_b[327]
  PIN ins_b[328]
    DIRECTION INPUT ;
    USE SIGNAL ;
    PORT
      LAYER M5 ;
        RECT 123.264 259.008 123.288 259.200 ;
    END
  END ins_b[328]
  PIN ins_b[329]
    DIRECTION INPUT ;
    USE SIGNAL ;
    PORT
      LAYER M3 ;
        RECT 123.624 259.056 123.642 259.200 ;
    END
  END ins_b[329]
  PIN ins_b[330]
    DIRECTION INPUT ;
    USE SIGNAL ;
    PORT
      LAYER M5 ;
        RECT 123.984 259.008 124.008 259.200 ;
    END
  END ins_b[330]
  PIN ins_b[331]
    DIRECTION INPUT ;
    USE SIGNAL ;
    PORT
      LAYER M3 ;
        RECT 124.344 259.056 124.362 259.200 ;
    END
  END ins_b[331]
  PIN ins_b[332]
    DIRECTION INPUT ;
    USE SIGNAL ;
    PORT
      LAYER M5 ;
        RECT 124.704 259.008 124.728 259.200 ;
    END
  END ins_b[332]
  PIN ins_b[333]
    DIRECTION INPUT ;
    USE SIGNAL ;
    PORT
      LAYER M3 ;
        RECT 125.064 259.056 125.082 259.200 ;
    END
  END ins_b[333]
  PIN ins_b[334]
    DIRECTION INPUT ;
    USE SIGNAL ;
    PORT
      LAYER M5 ;
        RECT 125.424 259.008 125.448 259.200 ;
    END
  END ins_b[334]
  PIN ins_b[335]
    DIRECTION INPUT ;
    USE SIGNAL ;
    PORT
      LAYER M3 ;
        RECT 125.784 259.056 125.802 259.200 ;
    END
  END ins_b[335]
  PIN ins_b[336]
    DIRECTION INPUT ;
    USE SIGNAL ;
    PORT
      LAYER M5 ;
        RECT 126.144 259.008 126.168 259.200 ;
    END
  END ins_b[336]
  PIN ins_b[337]
    DIRECTION INPUT ;
    USE SIGNAL ;
    PORT
      LAYER M3 ;
        RECT 126.540 259.056 126.558 259.200 ;
    END
  END ins_b[337]
  PIN ins_b[338]
    DIRECTION INPUT ;
    USE SIGNAL ;
    PORT
      LAYER M5 ;
        RECT 126.864 259.008 126.888 259.200 ;
    END
  END ins_b[338]
  PIN ins_b[339]
    DIRECTION INPUT ;
    USE SIGNAL ;
    PORT
      LAYER M3 ;
        RECT 127.260 259.056 127.278 259.200 ;
    END
  END ins_b[339]
  PIN ins_b[340]
    DIRECTION INPUT ;
    USE SIGNAL ;
    PORT
      LAYER M5 ;
        RECT 127.584 259.008 127.608 259.200 ;
    END
  END ins_b[340]
  PIN ins_b[341]
    DIRECTION INPUT ;
    USE SIGNAL ;
    PORT
      LAYER M3 ;
        RECT 127.980 259.056 127.998 259.200 ;
    END
  END ins_b[341]
  PIN ins_b[342]
    DIRECTION INPUT ;
    USE SIGNAL ;
    PORT
      LAYER M5 ;
        RECT 128.304 259.008 128.328 259.200 ;
    END
  END ins_b[342]
  PIN clk
    DIRECTION INPUT ;
    USE CLOCK ;
    PORT
      LAYER M3 ;
        RECT 128.700 259.056 128.718 259.200 ;
    END
  END clk
  PIN clk_r0
    DIRECTION INPUT ;
    USE CLOCK ;
    PORT
      LAYER M5 ;
        RECT 129.024 259.008 129.048 259.200 ;
    END
  END clk_r0
  PIN clk_r1
    DIRECTION INPUT ;
    USE CLOCK ;
    PORT
      LAYER M3 ;
        RECT 129.420 259.056 129.438 259.200 ;
    END
  END clk_r1
  PIN clk_r2
    DIRECTION INPUT ;
    USE CLOCK ;
    PORT
      LAYER M5 ;
        RECT 129.792 259.008 129.816 259.200 ;
    END
  END clk_r2
  PIN clk_r3
    DIRECTION INPUT ;
    USE CLOCK ;
    PORT
      LAYER M3 ;
        RECT 130.140 259.056 130.158 259.200 ;
    END
  END clk_r3
  PIN ins_b[343]
    DIRECTION INPUT ;
    USE SIGNAL ;
    PORT
      LAYER M5 ;
        RECT 130.512 259.008 130.536 259.200 ;
    END
  END ins_b[343]
  PIN up_out[0]
    DIRECTION OUTPUT ;
    USE SIGNAL ;
    PORT
      LAYER M3 ;
        RECT 130.860 259.056 130.878 259.200 ;
    END
  END up_out[0]
  PIN up_out[1]
    DIRECTION OUTPUT ;
    USE SIGNAL ;
    PORT
      LAYER M5 ;
        RECT 131.232 259.008 131.256 259.200 ;
    END
  END up_out[1]
  PIN up_out[2]
    DIRECTION OUTPUT ;
    USE SIGNAL ;
    PORT
      LAYER M3 ;
        RECT 131.580 259.056 131.598 259.200 ;
    END
  END up_out[2]
  PIN up_out[3]
    DIRECTION OUTPUT ;
    USE SIGNAL ;
    PORT
      LAYER M5 ;
        RECT 131.952 259.008 131.976 259.200 ;
    END
  END up_out[3]
  PIN up_out[4]
    DIRECTION OUTPUT ;
    USE SIGNAL ;
    PORT
      LAYER M3 ;
        RECT 132.300 259.056 132.318 259.200 ;
    END
  END up_out[4]
  PIN up_out[5]
    DIRECTION OUTPUT ;
    USE SIGNAL ;
    PORT
      LAYER M5 ;
        RECT 132.672 259.008 132.696 259.200 ;
    END
  END up_out[5]
  PIN up_out[6]
    DIRECTION OUTPUT ;
    USE SIGNAL ;
    PORT
      LAYER M3 ;
        RECT 133.020 259.056 133.038 259.200 ;
    END
  END up_out[6]
  PIN up_out[7]
    DIRECTION OUTPUT ;
    USE SIGNAL ;
    PORT
      LAYER M5 ;
        RECT 133.392 259.008 133.416 259.200 ;
    END
  END up_out[7]
  PIN up_out[8]
    DIRECTION OUTPUT ;
    USE SIGNAL ;
    PORT
      LAYER M3 ;
        RECT 133.740 259.056 133.758 259.200 ;
    END
  END up_out[8]
  PIN up_out[9]
    DIRECTION OUTPUT ;
    USE SIGNAL ;
    PORT
      LAYER M5 ;
        RECT 134.112 259.008 134.136 259.200 ;
    END
  END up_out[9]
  PIN up_out[10]
    DIRECTION OUTPUT ;
    USE SIGNAL ;
    PORT
      LAYER M3 ;
        RECT 134.460 259.056 134.478 259.200 ;
    END
  END up_out[10]
  PIN up_out[11]
    DIRECTION OUTPUT ;
    USE SIGNAL ;
    PORT
      LAYER M5 ;
        RECT 134.832 259.008 134.856 259.200 ;
    END
  END up_out[11]
  PIN up_out[12]
    DIRECTION OUTPUT ;
    USE SIGNAL ;
    PORT
      LAYER M3 ;
        RECT 135.180 259.056 135.198 259.200 ;
    END
  END up_out[12]
  PIN up_out[13]
    DIRECTION OUTPUT ;
    USE SIGNAL ;
    PORT
      LAYER M5 ;
        RECT 135.552 259.008 135.576 259.200 ;
    END
  END up_out[13]
  PIN up_out[14]
    DIRECTION OUTPUT ;
    USE SIGNAL ;
    PORT
      LAYER M3 ;
        RECT 135.900 259.056 135.918 259.200 ;
    END
  END up_out[14]
  PIN up_out[15]
    DIRECTION OUTPUT ;
    USE SIGNAL ;
    PORT
      LAYER M5 ;
        RECT 136.272 259.008 136.296 259.200 ;
    END
  END up_out[15]
  PIN up_out[16]
    DIRECTION OUTPUT ;
    USE SIGNAL ;
    PORT
      LAYER M3 ;
        RECT 136.620 259.056 136.638 259.200 ;
    END
  END up_out[16]
  PIN up_out[17]
    DIRECTION OUTPUT ;
    USE SIGNAL ;
    PORT
      LAYER M5 ;
        RECT 136.992 259.008 137.016 259.200 ;
    END
  END up_out[17]
  PIN up_out[18]
    DIRECTION OUTPUT ;
    USE SIGNAL ;
    PORT
      LAYER M3 ;
        RECT 137.340 259.056 137.358 259.200 ;
    END
  END up_out[18]
  PIN up_out[19]
    DIRECTION OUTPUT ;
    USE SIGNAL ;
    PORT
      LAYER M5 ;
        RECT 137.712 259.008 137.736 259.200 ;
    END
  END up_out[19]
  PIN up_out[20]
    DIRECTION OUTPUT ;
    USE SIGNAL ;
    PORT
      LAYER M3 ;
        RECT 138.060 259.056 138.078 259.200 ;
    END
  END up_out[20]
  PIN up_out[21]
    DIRECTION OUTPUT ;
    USE SIGNAL ;
    PORT
      LAYER M5 ;
        RECT 138.432 259.008 138.456 259.200 ;
    END
  END up_out[21]
  PIN up_out[22]
    DIRECTION OUTPUT ;
    USE SIGNAL ;
    PORT
      LAYER M3 ;
        RECT 138.780 259.056 138.798 259.200 ;
    END
  END up_out[22]
  PIN up_out[23]
    DIRECTION OUTPUT ;
    USE SIGNAL ;
    PORT
      LAYER M5 ;
        RECT 139.152 259.008 139.176 259.200 ;
    END
  END up_out[23]
  PIN up_out[24]
    DIRECTION OUTPUT ;
    USE SIGNAL ;
    PORT
      LAYER M3 ;
        RECT 139.536 259.056 139.554 259.200 ;
    END
  END up_out[24]
  PIN up_out[25]
    DIRECTION OUTPUT ;
    USE SIGNAL ;
    PORT
      LAYER M5 ;
        RECT 139.872 259.008 139.896 259.200 ;
    END
  END up_out[25]
  PIN up_out[26]
    DIRECTION OUTPUT ;
    USE SIGNAL ;
    PORT
      LAYER M3 ;
        RECT 140.256 259.056 140.274 259.200 ;
    END
  END up_out[26]
  PIN up_out[27]
    DIRECTION OUTPUT ;
    USE SIGNAL ;
    PORT
      LAYER M5 ;
        RECT 140.592 259.008 140.616 259.200 ;
    END
  END up_out[27]
  PIN up_out[28]
    DIRECTION OUTPUT ;
    USE SIGNAL ;
    PORT
      LAYER M3 ;
        RECT 140.976 259.056 140.994 259.200 ;
    END
  END up_out[28]
  PIN up_out[29]
    DIRECTION OUTPUT ;
    USE SIGNAL ;
    PORT
      LAYER M5 ;
        RECT 141.312 259.008 141.336 259.200 ;
    END
  END up_out[29]
  PIN up_out[30]
    DIRECTION OUTPUT ;
    USE SIGNAL ;
    PORT
      LAYER M3 ;
        RECT 141.696 259.056 141.714 259.200 ;
    END
  END up_out[30]
  PIN up_out[31]
    DIRECTION OUTPUT ;
    USE SIGNAL ;
    PORT
      LAYER M5 ;
        RECT 142.032 259.008 142.056 259.200 ;
    END
  END up_out[31]
  PIN up_out[32]
    DIRECTION OUTPUT ;
    USE SIGNAL ;
    PORT
      LAYER M3 ;
        RECT 142.416 259.056 142.434 259.200 ;
    END
  END up_out[32]
  PIN up_out[33]
    DIRECTION OUTPUT ;
    USE SIGNAL ;
    PORT
      LAYER M5 ;
        RECT 142.752 259.008 142.776 259.200 ;
    END
  END up_out[33]
  PIN up_out[34]
    DIRECTION OUTPUT ;
    USE SIGNAL ;
    PORT
      LAYER M3 ;
        RECT 143.136 259.056 143.154 259.200 ;
    END
  END up_out[34]
  PIN up_out[35]
    DIRECTION OUTPUT ;
    USE SIGNAL ;
    PORT
      LAYER M5 ;
        RECT 143.472 259.008 143.496 259.200 ;
    END
  END up_out[35]
  PIN up_out[36]
    DIRECTION OUTPUT ;
    USE SIGNAL ;
    PORT
      LAYER M3 ;
        RECT 143.856 259.056 143.874 259.200 ;
    END
  END up_out[36]
  PIN up_out[37]
    DIRECTION OUTPUT ;
    USE SIGNAL ;
    PORT
      LAYER M5 ;
        RECT 144.192 259.008 144.216 259.200 ;
    END
  END up_out[37]
  PIN up_out[38]
    DIRECTION OUTPUT ;
    USE SIGNAL ;
    PORT
      LAYER M3 ;
        RECT 144.576 259.056 144.594 259.200 ;
    END
  END up_out[38]
  PIN up_out[39]
    DIRECTION OUTPUT ;
    USE SIGNAL ;
    PORT
      LAYER M5 ;
        RECT 144.912 259.008 144.936 259.200 ;
    END
  END up_out[39]
  PIN up_out[40]
    DIRECTION OUTPUT ;
    USE SIGNAL ;
    PORT
      LAYER M3 ;
        RECT 145.296 259.056 145.314 259.200 ;
    END
  END up_out[40]
  PIN up_out[41]
    DIRECTION OUTPUT ;
    USE SIGNAL ;
    PORT
      LAYER M5 ;
        RECT 145.632 259.008 145.656 259.200 ;
    END
  END up_out[41]
  PIN up_out[42]
    DIRECTION OUTPUT ;
    USE SIGNAL ;
    PORT
      LAYER M3 ;
        RECT 146.016 259.056 146.034 259.200 ;
    END
  END up_out[42]
  PIN up_out[43]
    DIRECTION OUTPUT ;
    USE SIGNAL ;
    PORT
      LAYER M5 ;
        RECT 146.400 259.008 146.424 259.200 ;
    END
  END up_out[43]
  PIN up_out[44]
    DIRECTION OUTPUT ;
    USE SIGNAL ;
    PORT
      LAYER M3 ;
        RECT 146.736 259.056 146.754 259.200 ;
    END
  END up_out[44]
  PIN up_out[45]
    DIRECTION OUTPUT ;
    USE SIGNAL ;
    PORT
      LAYER M5 ;
        RECT 147.120 259.008 147.144 259.200 ;
    END
  END up_out[45]
  PIN up_out[46]
    DIRECTION OUTPUT ;
    USE SIGNAL ;
    PORT
      LAYER M3 ;
        RECT 147.456 259.056 147.474 259.200 ;
    END
  END up_out[46]
  PIN up_out[47]
    DIRECTION OUTPUT ;
    USE SIGNAL ;
    PORT
      LAYER M5 ;
        RECT 147.840 259.008 147.864 259.200 ;
    END
  END up_out[47]
  PIN up_out[48]
    DIRECTION OUTPUT ;
    USE SIGNAL ;
    PORT
      LAYER M3 ;
        RECT 148.176 259.056 148.194 259.200 ;
    END
  END up_out[48]
  PIN up_out[49]
    DIRECTION OUTPUT ;
    USE SIGNAL ;
    PORT
      LAYER M5 ;
        RECT 148.560 259.008 148.584 259.200 ;
    END
  END up_out[49]
  PIN up_out[50]
    DIRECTION OUTPUT ;
    USE SIGNAL ;
    PORT
      LAYER M3 ;
        RECT 148.896 259.056 148.914 259.200 ;
    END
  END up_out[50]
  PIN up_out[51]
    DIRECTION OUTPUT ;
    USE SIGNAL ;
    PORT
      LAYER M5 ;
        RECT 149.280 259.008 149.304 259.200 ;
    END
  END up_out[51]
  PIN up_out[52]
    DIRECTION OUTPUT ;
    USE SIGNAL ;
    PORT
      LAYER M3 ;
        RECT 149.616 259.056 149.634 259.200 ;
    END
  END up_out[52]
  PIN up_out[53]
    DIRECTION OUTPUT ;
    USE SIGNAL ;
    PORT
      LAYER M5 ;
        RECT 150.000 259.008 150.024 259.200 ;
    END
  END up_out[53]
  PIN up_out[54]
    DIRECTION OUTPUT ;
    USE SIGNAL ;
    PORT
      LAYER M3 ;
        RECT 150.336 259.056 150.354 259.200 ;
    END
  END up_out[54]
  PIN up_out[55]
    DIRECTION OUTPUT ;
    USE SIGNAL ;
    PORT
      LAYER M5 ;
        RECT 150.720 259.008 150.744 259.200 ;
    END
  END up_out[55]
  PIN up_out[56]
    DIRECTION OUTPUT ;
    USE SIGNAL ;
    PORT
      LAYER M3 ;
        RECT 151.056 259.056 151.074 259.200 ;
    END
  END up_out[56]
  PIN up_out[57]
    DIRECTION OUTPUT ;
    USE SIGNAL ;
    PORT
      LAYER M5 ;
        RECT 151.440 259.008 151.464 259.200 ;
    END
  END up_out[57]
  PIN up_out[58]
    DIRECTION OUTPUT ;
    USE SIGNAL ;
    PORT
      LAYER M3 ;
        RECT 151.812 259.056 151.830 259.200 ;
    END
  END up_out[58]
  PIN up_out[59]
    DIRECTION OUTPUT ;
    USE SIGNAL ;
    PORT
      LAYER M5 ;
        RECT 152.160 259.008 152.184 259.200 ;
    END
  END up_out[59]
  PIN up_out[60]
    DIRECTION OUTPUT ;
    USE SIGNAL ;
    PORT
      LAYER M3 ;
        RECT 152.532 259.056 152.550 259.200 ;
    END
  END up_out[60]
  PIN up_out[61]
    DIRECTION OUTPUT ;
    USE SIGNAL ;
    PORT
      LAYER M5 ;
        RECT 152.880 259.008 152.904 259.200 ;
    END
  END up_out[61]
  PIN up_out[62]
    DIRECTION OUTPUT ;
    USE SIGNAL ;
    PORT
      LAYER M3 ;
        RECT 153.252 259.056 153.270 259.200 ;
    END
  END up_out[62]
  PIN up_out[63]
    DIRECTION OUTPUT ;
    USE SIGNAL ;
    PORT
      LAYER M5 ;
        RECT 153.600 259.008 153.624 259.200 ;
    END
  END up_out[63]
  PIN up_out[64]
    DIRECTION OUTPUT ;
    USE SIGNAL ;
    PORT
      LAYER M3 ;
        RECT 153.972 259.056 153.990 259.200 ;
    END
  END up_out[64]
  PIN up_out[65]
    DIRECTION OUTPUT ;
    USE SIGNAL ;
    PORT
      LAYER M5 ;
        RECT 154.320 259.008 154.344 259.200 ;
    END
  END up_out[65]
  PIN up_out[66]
    DIRECTION OUTPUT ;
    USE SIGNAL ;
    PORT
      LAYER M3 ;
        RECT 154.692 259.056 154.710 259.200 ;
    END
  END up_out[66]
  PIN up_out[67]
    DIRECTION OUTPUT ;
    USE SIGNAL ;
    PORT
      LAYER M5 ;
        RECT 155.040 259.008 155.064 259.200 ;
    END
  END up_out[67]
  PIN up_out[68]
    DIRECTION OUTPUT ;
    USE SIGNAL ;
    PORT
      LAYER M3 ;
        RECT 155.412 259.056 155.430 259.200 ;
    END
  END up_out[68]
  PIN up_out[69]
    DIRECTION OUTPUT ;
    USE SIGNAL ;
    PORT
      LAYER M5 ;
        RECT 155.760 259.008 155.784 259.200 ;
    END
  END up_out[69]
  PIN up_out[70]
    DIRECTION OUTPUT ;
    USE SIGNAL ;
    PORT
      LAYER M3 ;
        RECT 156.132 259.056 156.150 259.200 ;
    END
  END up_out[70]
  PIN up_out[71]
    DIRECTION OUTPUT ;
    USE SIGNAL ;
    PORT
      LAYER M5 ;
        RECT 156.480 259.008 156.504 259.200 ;
    END
  END up_out[71]
  PIN up_out[72]
    DIRECTION OUTPUT ;
    USE SIGNAL ;
    PORT
      LAYER M3 ;
        RECT 156.852 259.056 156.870 259.200 ;
    END
  END up_out[72]
  PIN up_out[73]
    DIRECTION OUTPUT ;
    USE SIGNAL ;
    PORT
      LAYER M5 ;
        RECT 157.200 259.008 157.224 259.200 ;
    END
  END up_out[73]
  PIN up_out[74]
    DIRECTION OUTPUT ;
    USE SIGNAL ;
    PORT
      LAYER M3 ;
        RECT 157.572 259.056 157.590 259.200 ;
    END
  END up_out[74]
  PIN up_out[75]
    DIRECTION OUTPUT ;
    USE SIGNAL ;
    PORT
      LAYER M5 ;
        RECT 157.920 259.008 157.944 259.200 ;
    END
  END up_out[75]
  PIN up_out[76]
    DIRECTION OUTPUT ;
    USE SIGNAL ;
    PORT
      LAYER M3 ;
        RECT 158.292 259.056 158.310 259.200 ;
    END
  END up_out[76]
  PIN up_out[77]
    DIRECTION OUTPUT ;
    USE SIGNAL ;
    PORT
      LAYER M5 ;
        RECT 158.640 259.008 158.664 259.200 ;
    END
  END up_out[77]
  PIN up_out[78]
    DIRECTION OUTPUT ;
    USE SIGNAL ;
    PORT
      LAYER M3 ;
        RECT 159.012 259.056 159.030 259.200 ;
    END
  END up_out[78]
  PIN up_out[79]
    DIRECTION OUTPUT ;
    USE SIGNAL ;
    PORT
      LAYER M5 ;
        RECT 159.360 259.008 159.384 259.200 ;
    END
  END up_out[79]
  PIN up_out[80]
    DIRECTION OUTPUT ;
    USE SIGNAL ;
    PORT
      LAYER M3 ;
        RECT 159.732 259.056 159.750 259.200 ;
    END
  END up_out[80]
  PIN up_out[81]
    DIRECTION OUTPUT ;
    USE SIGNAL ;
    PORT
      LAYER M5 ;
        RECT 160.080 259.008 160.104 259.200 ;
    END
  END up_out[81]
  PIN up_out[82]
    DIRECTION OUTPUT ;
    USE SIGNAL ;
    PORT
      LAYER M3 ;
        RECT 160.452 259.056 160.470 259.200 ;
    END
  END up_out[82]
  PIN up_out[83]
    DIRECTION OUTPUT ;
    USE SIGNAL ;
    PORT
      LAYER M5 ;
        RECT 160.800 259.008 160.824 259.200 ;
    END
  END up_out[83]
  PIN up_out[84]
    DIRECTION OUTPUT ;
    USE SIGNAL ;
    PORT
      LAYER M3 ;
        RECT 161.172 259.056 161.190 259.200 ;
    END
  END up_out[84]
  PIN up_out[85]
    DIRECTION OUTPUT ;
    USE SIGNAL ;
    PORT
      LAYER M5 ;
        RECT 161.520 259.008 161.544 259.200 ;
    END
  END up_out[85]
  PIN up_out[86]
    DIRECTION OUTPUT ;
    USE SIGNAL ;
    PORT
      LAYER M3 ;
        RECT 161.892 259.056 161.910 259.200 ;
    END
  END up_out[86]
  PIN up_out[87]
    DIRECTION OUTPUT ;
    USE SIGNAL ;
    PORT
      LAYER M5 ;
        RECT 162.240 259.008 162.264 259.200 ;
    END
  END up_out[87]
  PIN up_out[88]
    DIRECTION OUTPUT ;
    USE SIGNAL ;
    PORT
      LAYER M3 ;
        RECT 162.612 259.056 162.630 259.200 ;
    END
  END up_out[88]
  PIN up_out[89]
    DIRECTION OUTPUT ;
    USE SIGNAL ;
    PORT
      LAYER M5 ;
        RECT 162.960 259.008 162.984 259.200 ;
    END
  END up_out[89]
  PIN up_out[90]
    DIRECTION OUTPUT ;
    USE SIGNAL ;
    PORT
      LAYER M3 ;
        RECT 163.332 259.056 163.350 259.200 ;
    END
  END up_out[90]
  PIN up_out[91]
    DIRECTION OUTPUT ;
    USE SIGNAL ;
    PORT
      LAYER M5 ;
        RECT 163.728 259.008 163.752 259.200 ;
    END
  END up_out[91]
  PIN up_out[92]
    DIRECTION OUTPUT ;
    USE SIGNAL ;
    PORT
      LAYER M3 ;
        RECT 164.088 259.056 164.106 259.200 ;
    END
  END up_out[92]
  PIN up_out[93]
    DIRECTION OUTPUT ;
    USE SIGNAL ;
    PORT
      LAYER M5 ;
        RECT 164.448 259.008 164.472 259.200 ;
    END
  END up_out[93]
  PIN up_out[94]
    DIRECTION OUTPUT ;
    USE SIGNAL ;
    PORT
      LAYER M3 ;
        RECT 164.808 259.056 164.826 259.200 ;
    END
  END up_out[94]
  PIN up_out[95]
    DIRECTION OUTPUT ;
    USE SIGNAL ;
    PORT
      LAYER M5 ;
        RECT 165.168 259.008 165.192 259.200 ;
    END
  END up_out[95]
  PIN up_out[96]
    DIRECTION OUTPUT ;
    USE SIGNAL ;
    PORT
      LAYER M3 ;
        RECT 165.528 259.056 165.546 259.200 ;
    END
  END up_out[96]
  PIN up_out[97]
    DIRECTION OUTPUT ;
    USE SIGNAL ;
    PORT
      LAYER M5 ;
        RECT 165.888 259.008 165.912 259.200 ;
    END
  END up_out[97]
  PIN up_out[98]
    DIRECTION OUTPUT ;
    USE SIGNAL ;
    PORT
      LAYER M3 ;
        RECT 166.248 259.056 166.266 259.200 ;
    END
  END up_out[98]
  PIN up_out[99]
    DIRECTION OUTPUT ;
    USE SIGNAL ;
    PORT
      LAYER M5 ;
        RECT 166.608 259.008 166.632 259.200 ;
    END
  END up_out[99]
  PIN up_out[100]
    DIRECTION OUTPUT ;
    USE SIGNAL ;
    PORT
      LAYER M3 ;
        RECT 166.968 259.056 166.986 259.200 ;
    END
  END up_out[100]
  PIN up_out[101]
    DIRECTION OUTPUT ;
    USE SIGNAL ;
    PORT
      LAYER M5 ;
        RECT 167.328 259.008 167.352 259.200 ;
    END
  END up_out[101]
  PIN up_out[102]
    DIRECTION OUTPUT ;
    USE SIGNAL ;
    PORT
      LAYER M3 ;
        RECT 167.688 259.056 167.706 259.200 ;
    END
  END up_out[102]
  PIN up_out[103]
    DIRECTION OUTPUT ;
    USE SIGNAL ;
    PORT
      LAYER M5 ;
        RECT 168.048 259.008 168.072 259.200 ;
    END
  END up_out[103]
  PIN up_out[104]
    DIRECTION OUTPUT ;
    USE SIGNAL ;
    PORT
      LAYER M3 ;
        RECT 168.408 259.056 168.426 259.200 ;
    END
  END up_out[104]
  PIN up_out[105]
    DIRECTION OUTPUT ;
    USE SIGNAL ;
    PORT
      LAYER M5 ;
        RECT 168.768 259.008 168.792 259.200 ;
    END
  END up_out[105]
  PIN up_out[106]
    DIRECTION OUTPUT ;
    USE SIGNAL ;
    PORT
      LAYER M3 ;
        RECT 169.128 259.056 169.146 259.200 ;
    END
  END up_out[106]
  PIN up_out[107]
    DIRECTION OUTPUT ;
    USE SIGNAL ;
    PORT
      LAYER M5 ;
        RECT 169.488 259.008 169.512 259.200 ;
    END
  END up_out[107]
  PIN up_out[108]
    DIRECTION OUTPUT ;
    USE SIGNAL ;
    PORT
      LAYER M3 ;
        RECT 169.848 259.056 169.866 259.200 ;
    END
  END up_out[108]
  PIN up_out[109]
    DIRECTION OUTPUT ;
    USE SIGNAL ;
    PORT
      LAYER M5 ;
        RECT 170.208 259.008 170.232 259.200 ;
    END
  END up_out[109]
  PIN up_out[110]
    DIRECTION OUTPUT ;
    USE SIGNAL ;
    PORT
      LAYER M3 ;
        RECT 170.568 259.056 170.586 259.200 ;
    END
  END up_out[110]
  PIN up_out[111]
    DIRECTION OUTPUT ;
    USE SIGNAL ;
    PORT
      LAYER M5 ;
        RECT 170.928 259.008 170.952 259.200 ;
    END
  END up_out[111]
  PIN up_out[112]
    DIRECTION OUTPUT ;
    USE SIGNAL ;
    PORT
      LAYER M3 ;
        RECT 171.288 259.056 171.306 259.200 ;
    END
  END up_out[112]
  PIN up_out[113]
    DIRECTION OUTPUT ;
    USE SIGNAL ;
    PORT
      LAYER M5 ;
        RECT 171.648 259.008 171.672 259.200 ;
    END
  END up_out[113]
  PIN up_out[114]
    DIRECTION OUTPUT ;
    USE SIGNAL ;
    PORT
      LAYER M3 ;
        RECT 172.008 259.056 172.026 259.200 ;
    END
  END up_out[114]
  PIN up_out[115]
    DIRECTION OUTPUT ;
    USE SIGNAL ;
    PORT
      LAYER M5 ;
        RECT 172.368 259.008 172.392 259.200 ;
    END
  END up_out[115]
  PIN up_out[116]
    DIRECTION OUTPUT ;
    USE SIGNAL ;
    PORT
      LAYER M3 ;
        RECT 172.728 259.056 172.746 259.200 ;
    END
  END up_out[116]
  PIN up_out[117]
    DIRECTION OUTPUT ;
    USE SIGNAL ;
    PORT
      LAYER M5 ;
        RECT 173.088 259.008 173.112 259.200 ;
    END
  END up_out[117]
  PIN up_out[118]
    DIRECTION OUTPUT ;
    USE SIGNAL ;
    PORT
      LAYER M3 ;
        RECT 173.448 259.056 173.466 259.200 ;
    END
  END up_out[118]
  PIN up_out[119]
    DIRECTION OUTPUT ;
    USE SIGNAL ;
    PORT
      LAYER M5 ;
        RECT 173.808 259.008 173.832 259.200 ;
    END
  END up_out[119]
  PIN up_out[120]
    DIRECTION OUTPUT ;
    USE SIGNAL ;
    PORT
      LAYER M3 ;
        RECT 174.168 259.056 174.186 259.200 ;
    END
  END up_out[120]
  PIN up_out[121]
    DIRECTION OUTPUT ;
    USE SIGNAL ;
    PORT
      LAYER M5 ;
        RECT 174.528 259.008 174.552 259.200 ;
    END
  END up_out[121]
  PIN up_out[122]
    DIRECTION OUTPUT ;
    USE SIGNAL ;
    PORT
      LAYER M3 ;
        RECT 174.888 259.056 174.906 259.200 ;
    END
  END up_out[122]
  PIN up_out[123]
    DIRECTION OUTPUT ;
    USE SIGNAL ;
    PORT
      LAYER M5 ;
        RECT 175.248 259.008 175.272 259.200 ;
    END
  END up_out[123]
  PIN up_out[124]
    DIRECTION OUTPUT ;
    USE SIGNAL ;
    PORT
      LAYER M3 ;
        RECT 175.608 259.056 175.626 259.200 ;
    END
  END up_out[124]
  PIN up_out[125]
    DIRECTION OUTPUT ;
    USE SIGNAL ;
    PORT
      LAYER M5 ;
        RECT 175.968 259.008 175.992 259.200 ;
    END
  END up_out[125]
  PIN up_out[126]
    DIRECTION OUTPUT ;
    USE SIGNAL ;
    PORT
      LAYER M3 ;
        RECT 176.328 259.056 176.346 259.200 ;
    END
  END up_out[126]
  PIN up_out[127]
    DIRECTION OUTPUT ;
    USE SIGNAL ;
    PORT
      LAYER M5 ;
        RECT 176.688 259.008 176.712 259.200 ;
    END
  END up_out[127]
  PIN up_out[128]
    DIRECTION OUTPUT ;
    USE SIGNAL ;
    PORT
      LAYER M3 ;
        RECT 177.084 259.056 177.102 259.200 ;
    END
  END up_out[128]
  PIN up_out[129]
    DIRECTION OUTPUT ;
    USE SIGNAL ;
    PORT
      LAYER M5 ;
        RECT 177.408 259.008 177.432 259.200 ;
    END
  END up_out[129]
  PIN up_out[130]
    DIRECTION OUTPUT ;
    USE SIGNAL ;
    PORT
      LAYER M3 ;
        RECT 177.804 259.056 177.822 259.200 ;
    END
  END up_out[130]
  PIN up_out[131]
    DIRECTION OUTPUT ;
    USE SIGNAL ;
    PORT
      LAYER M5 ;
        RECT 178.128 259.008 178.152 259.200 ;
    END
  END up_out[131]
  PIN up_out[132]
    DIRECTION OUTPUT ;
    USE SIGNAL ;
    PORT
      LAYER M3 ;
        RECT 178.524 259.056 178.542 259.200 ;
    END
  END up_out[132]
  PIN up_out[133]
    DIRECTION OUTPUT ;
    USE SIGNAL ;
    PORT
      LAYER M5 ;
        RECT 178.848 259.008 178.872 259.200 ;
    END
  END up_out[133]
  PIN up_out[134]
    DIRECTION OUTPUT ;
    USE SIGNAL ;
    PORT
      LAYER M3 ;
        RECT 179.244 259.056 179.262 259.200 ;
    END
  END up_out[134]
  PIN up_out[135]
    DIRECTION OUTPUT ;
    USE SIGNAL ;
    PORT
      LAYER M5 ;
        RECT 179.568 259.008 179.592 259.200 ;
    END
  END up_out[135]
  PIN up_out[136]
    DIRECTION OUTPUT ;
    USE SIGNAL ;
    PORT
      LAYER M3 ;
        RECT 179.964 259.056 179.982 259.200 ;
    END
  END up_out[136]
  PIN up_out[137]
    DIRECTION OUTPUT ;
    USE SIGNAL ;
    PORT
      LAYER M5 ;
        RECT 180.336 259.008 180.360 259.200 ;
    END
  END up_out[137]
  PIN up_out[138]
    DIRECTION OUTPUT ;
    USE SIGNAL ;
    PORT
      LAYER M3 ;
        RECT 180.684 259.056 180.702 259.200 ;
    END
  END up_out[138]
  PIN up_out[139]
    DIRECTION OUTPUT ;
    USE SIGNAL ;
    PORT
      LAYER M5 ;
        RECT 181.056 259.008 181.080 259.200 ;
    END
  END up_out[139]
  PIN up_out[140]
    DIRECTION OUTPUT ;
    USE SIGNAL ;
    PORT
      LAYER M3 ;
        RECT 181.404 259.056 181.422 259.200 ;
    END
  END up_out[140]
  PIN up_out[141]
    DIRECTION OUTPUT ;
    USE SIGNAL ;
    PORT
      LAYER M5 ;
        RECT 181.776 259.008 181.800 259.200 ;
    END
  END up_out[141]
  PIN up_out[142]
    DIRECTION OUTPUT ;
    USE SIGNAL ;
    PORT
      LAYER M3 ;
        RECT 182.124 259.056 182.142 259.200 ;
    END
  END up_out[142]
  PIN up_out[143]
    DIRECTION OUTPUT ;
    USE SIGNAL ;
    PORT
      LAYER M5 ;
        RECT 182.496 259.008 182.520 259.200 ;
    END
  END up_out[143]
  PIN up_out[144]
    DIRECTION OUTPUT ;
    USE SIGNAL ;
    PORT
      LAYER M3 ;
        RECT 182.844 259.056 182.862 259.200 ;
    END
  END up_out[144]
  PIN up_out[145]
    DIRECTION OUTPUT ;
    USE SIGNAL ;
    PORT
      LAYER M5 ;
        RECT 183.216 259.008 183.240 259.200 ;
    END
  END up_out[145]
  PIN up_out[146]
    DIRECTION OUTPUT ;
    USE SIGNAL ;
    PORT
      LAYER M3 ;
        RECT 183.564 259.056 183.582 259.200 ;
    END
  END up_out[146]
  PIN up_out[147]
    DIRECTION OUTPUT ;
    USE SIGNAL ;
    PORT
      LAYER M5 ;
        RECT 183.936 259.008 183.960 259.200 ;
    END
  END up_out[147]
  PIN up_out[148]
    DIRECTION OUTPUT ;
    USE SIGNAL ;
    PORT
      LAYER M3 ;
        RECT 184.284 259.056 184.302 259.200 ;
    END
  END up_out[148]
  PIN up_out[149]
    DIRECTION OUTPUT ;
    USE SIGNAL ;
    PORT
      LAYER M5 ;
        RECT 184.656 259.008 184.680 259.200 ;
    END
  END up_out[149]
  PIN up_out[150]
    DIRECTION OUTPUT ;
    USE SIGNAL ;
    PORT
      LAYER M3 ;
        RECT 185.004 259.056 185.022 259.200 ;
    END
  END up_out[150]
  PIN up_out[151]
    DIRECTION OUTPUT ;
    USE SIGNAL ;
    PORT
      LAYER M5 ;
        RECT 185.376 259.008 185.400 259.200 ;
    END
  END up_out[151]
  PIN up_out[152]
    DIRECTION OUTPUT ;
    USE SIGNAL ;
    PORT
      LAYER M3 ;
        RECT 185.724 259.056 185.742 259.200 ;
    END
  END up_out[152]
  PIN up_out[153]
    DIRECTION OUTPUT ;
    USE SIGNAL ;
    PORT
      LAYER M5 ;
        RECT 186.096 259.008 186.120 259.200 ;
    END
  END up_out[153]
  PIN up_out[154]
    DIRECTION OUTPUT ;
    USE SIGNAL ;
    PORT
      LAYER M3 ;
        RECT 186.444 259.056 186.462 259.200 ;
    END
  END up_out[154]
  PIN up_out[155]
    DIRECTION OUTPUT ;
    USE SIGNAL ;
    PORT
      LAYER M5 ;
        RECT 186.816 259.008 186.840 259.200 ;
    END
  END up_out[155]
  PIN up_out[156]
    DIRECTION OUTPUT ;
    USE SIGNAL ;
    PORT
      LAYER M3 ;
        RECT 187.164 259.056 187.182 259.200 ;
    END
  END up_out[156]
  PIN up_out[157]
    DIRECTION OUTPUT ;
    USE SIGNAL ;
    PORT
      LAYER M5 ;
        RECT 187.536 259.008 187.560 259.200 ;
    END
  END up_out[157]
  PIN up_out[158]
    DIRECTION OUTPUT ;
    USE SIGNAL ;
    PORT
      LAYER M3 ;
        RECT 187.884 259.056 187.902 259.200 ;
    END
  END up_out[158]
  PIN up_out[159]
    DIRECTION OUTPUT ;
    USE SIGNAL ;
    PORT
      LAYER M5 ;
        RECT 188.256 259.008 188.280 259.200 ;
    END
  END up_out[159]
  PIN up_out[160]
    DIRECTION OUTPUT ;
    USE SIGNAL ;
    PORT
      LAYER M3 ;
        RECT 188.604 259.056 188.622 259.200 ;
    END
  END up_out[160]
  PIN up_out[161]
    DIRECTION OUTPUT ;
    USE SIGNAL ;
    PORT
      LAYER M5 ;
        RECT 188.976 259.008 189.000 259.200 ;
    END
  END up_out[161]
  PIN up_out[162]
    DIRECTION OUTPUT ;
    USE SIGNAL ;
    PORT
      LAYER M3 ;
        RECT 189.360 259.056 189.378 259.200 ;
    END
  END up_out[162]
  PIN up_out[163]
    DIRECTION OUTPUT ;
    USE SIGNAL ;
    PORT
      LAYER M5 ;
        RECT 189.696 259.008 189.720 259.200 ;
    END
  END up_out[163]
  PIN up_out[164]
    DIRECTION OUTPUT ;
    USE SIGNAL ;
    PORT
      LAYER M3 ;
        RECT 190.080 259.056 190.098 259.200 ;
    END
  END up_out[164]
  PIN up_out[165]
    DIRECTION OUTPUT ;
    USE SIGNAL ;
    PORT
      LAYER M5 ;
        RECT 190.416 259.008 190.440 259.200 ;
    END
  END up_out[165]
  PIN up_out[166]
    DIRECTION OUTPUT ;
    USE SIGNAL ;
    PORT
      LAYER M3 ;
        RECT 190.800 259.056 190.818 259.200 ;
    END
  END up_out[166]
  PIN up_out[167]
    DIRECTION OUTPUT ;
    USE SIGNAL ;
    PORT
      LAYER M5 ;
        RECT 191.136 259.008 191.160 259.200 ;
    END
  END up_out[167]
  PIN up_out[168]
    DIRECTION OUTPUT ;
    USE SIGNAL ;
    PORT
      LAYER M3 ;
        RECT 191.520 259.056 191.538 259.200 ;
    END
  END up_out[168]
  PIN up_out[169]
    DIRECTION OUTPUT ;
    USE SIGNAL ;
    PORT
      LAYER M5 ;
        RECT 191.856 259.008 191.880 259.200 ;
    END
  END up_out[169]
  PIN up_out[170]
    DIRECTION OUTPUT ;
    USE SIGNAL ;
    PORT
      LAYER M3 ;
        RECT 192.240 259.056 192.258 259.200 ;
    END
  END up_out[170]
  PIN up_out[171]
    DIRECTION OUTPUT ;
    USE SIGNAL ;
    PORT
      LAYER M5 ;
        RECT 192.576 259.008 192.600 259.200 ;
    END
  END up_out[171]
  PIN up_out[172]
    DIRECTION OUTPUT ;
    USE SIGNAL ;
    PORT
      LAYER M3 ;
        RECT 192.960 259.056 192.978 259.200 ;
    END
  END up_out[172]
  PIN up_out[173]
    DIRECTION OUTPUT ;
    USE SIGNAL ;
    PORT
      LAYER M5 ;
        RECT 193.296 259.008 193.320 259.200 ;
    END
  END up_out[173]
  PIN up_out[174]
    DIRECTION OUTPUT ;
    USE SIGNAL ;
    PORT
      LAYER M3 ;
        RECT 193.680 259.056 193.698 259.200 ;
    END
  END up_out[174]
  PIN up_out[175]
    DIRECTION OUTPUT ;
    USE SIGNAL ;
    PORT
      LAYER M5 ;
        RECT 194.016 259.008 194.040 259.200 ;
    END
  END up_out[175]
  PIN up_out[176]
    DIRECTION OUTPUT ;
    USE SIGNAL ;
    PORT
      LAYER M3 ;
        RECT 194.400 259.056 194.418 259.200 ;
    END
  END up_out[176]
  PIN up_out[177]
    DIRECTION OUTPUT ;
    USE SIGNAL ;
    PORT
      LAYER M5 ;
        RECT 194.736 259.008 194.760 259.200 ;
    END
  END up_out[177]
  PIN up_out[178]
    DIRECTION OUTPUT ;
    USE SIGNAL ;
    PORT
      LAYER M3 ;
        RECT 195.120 259.056 195.138 259.200 ;
    END
  END up_out[178]
  PIN up_out[179]
    DIRECTION OUTPUT ;
    USE SIGNAL ;
    PORT
      LAYER M5 ;
        RECT 195.456 259.008 195.480 259.200 ;
    END
  END up_out[179]
  PIN up_out[180]
    DIRECTION OUTPUT ;
    USE SIGNAL ;
    PORT
      LAYER M3 ;
        RECT 195.840 259.056 195.858 259.200 ;
    END
  END up_out[180]
  PIN up_out[181]
    DIRECTION OUTPUT ;
    USE SIGNAL ;
    PORT
      LAYER M5 ;
        RECT 196.176 259.008 196.200 259.200 ;
    END
  END up_out[181]
  PIN up_out[182]
    DIRECTION OUTPUT ;
    USE SIGNAL ;
    PORT
      LAYER M3 ;
        RECT 196.560 259.056 196.578 259.200 ;
    END
  END up_out[182]
  PIN up_out[183]
    DIRECTION OUTPUT ;
    USE SIGNAL ;
    PORT
      LAYER M5 ;
        RECT 196.944 259.008 196.968 259.200 ;
    END
  END up_out[183]
  PIN up_out[184]
    DIRECTION OUTPUT ;
    USE SIGNAL ;
    PORT
      LAYER M3 ;
        RECT 197.280 259.056 197.298 259.200 ;
    END
  END up_out[184]
  PIN up_out[185]
    DIRECTION OUTPUT ;
    USE SIGNAL ;
    PORT
      LAYER M5 ;
        RECT 197.664 259.008 197.688 259.200 ;
    END
  END up_out[185]
  PIN up_out[186]
    DIRECTION OUTPUT ;
    USE SIGNAL ;
    PORT
      LAYER M3 ;
        RECT 198.000 259.056 198.018 259.200 ;
    END
  END up_out[186]
  PIN up_out[187]
    DIRECTION OUTPUT ;
    USE SIGNAL ;
    PORT
      LAYER M5 ;
        RECT 198.384 259.008 198.408 259.200 ;
    END
  END up_out[187]
  PIN up_out[188]
    DIRECTION OUTPUT ;
    USE SIGNAL ;
    PORT
      LAYER M3 ;
        RECT 198.720 259.056 198.738 259.200 ;
    END
  END up_out[188]
  PIN up_out[189]
    DIRECTION OUTPUT ;
    USE SIGNAL ;
    PORT
      LAYER M5 ;
        RECT 199.104 259.008 199.128 259.200 ;
    END
  END up_out[189]
  PIN up_out[190]
    DIRECTION OUTPUT ;
    USE SIGNAL ;
    PORT
      LAYER M3 ;
        RECT 199.440 259.056 199.458 259.200 ;
    END
  END up_out[190]
  PIN up_out[191]
    DIRECTION OUTPUT ;
    USE SIGNAL ;
    PORT
      LAYER M5 ;
        RECT 199.824 259.008 199.848 259.200 ;
    END
  END up_out[191]
  PIN up_out[192]
    DIRECTION OUTPUT ;
    USE SIGNAL ;
    PORT
      LAYER M3 ;
        RECT 200.160 259.056 200.178 259.200 ;
    END
  END up_out[192]
  PIN up_out[193]
    DIRECTION OUTPUT ;
    USE SIGNAL ;
    PORT
      LAYER M5 ;
        RECT 200.544 259.008 200.568 259.200 ;
    END
  END up_out[193]
  PIN up_out[194]
    DIRECTION OUTPUT ;
    USE SIGNAL ;
    PORT
      LAYER M3 ;
        RECT 200.880 259.056 200.898 259.200 ;
    END
  END up_out[194]
  PIN up_out[195]
    DIRECTION OUTPUT ;
    USE SIGNAL ;
    PORT
      LAYER M5 ;
        RECT 201.264 259.008 201.288 259.200 ;
    END
  END up_out[195]
  PIN up_out[196]
    DIRECTION OUTPUT ;
    USE SIGNAL ;
    PORT
      LAYER M3 ;
        RECT 201.600 259.056 201.618 259.200 ;
    END
  END up_out[196]
  PIN up_out[197]
    DIRECTION OUTPUT ;
    USE SIGNAL ;
    PORT
      LAYER M5 ;
        RECT 201.984 259.008 202.008 259.200 ;
    END
  END up_out[197]
  PIN up_out[198]
    DIRECTION OUTPUT ;
    USE SIGNAL ;
    PORT
      LAYER M3 ;
        RECT 202.356 259.056 202.374 259.200 ;
    END
  END up_out[198]
  PIN up_out[199]
    DIRECTION OUTPUT ;
    USE SIGNAL ;
    PORT
      LAYER M5 ;
        RECT 202.704 259.008 202.728 259.200 ;
    END
  END up_out[199]
  PIN up_out[200]
    DIRECTION OUTPUT ;
    USE SIGNAL ;
    PORT
      LAYER M3 ;
        RECT 203.076 259.056 203.094 259.200 ;
    END
  END up_out[200]
  PIN up_out[201]
    DIRECTION OUTPUT ;
    USE SIGNAL ;
    PORT
      LAYER M5 ;
        RECT 203.424 259.008 203.448 259.200 ;
    END
  END up_out[201]
  PIN up_out[202]
    DIRECTION OUTPUT ;
    USE SIGNAL ;
    PORT
      LAYER M3 ;
        RECT 203.796 259.056 203.814 259.200 ;
    END
  END up_out[202]
  PIN up_out[203]
    DIRECTION OUTPUT ;
    USE SIGNAL ;
    PORT
      LAYER M5 ;
        RECT 204.144 259.008 204.168 259.200 ;
    END
  END up_out[203]
  PIN up_out[204]
    DIRECTION OUTPUT ;
    USE SIGNAL ;
    PORT
      LAYER M3 ;
        RECT 204.516 259.056 204.534 259.200 ;
    END
  END up_out[204]
  PIN up_out[205]
    DIRECTION OUTPUT ;
    USE SIGNAL ;
    PORT
      LAYER M5 ;
        RECT 204.864 259.008 204.888 259.200 ;
    END
  END up_out[205]
  PIN up_out[206]
    DIRECTION OUTPUT ;
    USE SIGNAL ;
    PORT
      LAYER M3 ;
        RECT 205.236 259.056 205.254 259.200 ;
    END
  END up_out[206]
  PIN up_out[207]
    DIRECTION OUTPUT ;
    USE SIGNAL ;
    PORT
      LAYER M5 ;
        RECT 205.584 259.008 205.608 259.200 ;
    END
  END up_out[207]
  PIN up_out[208]
    DIRECTION OUTPUT ;
    USE SIGNAL ;
    PORT
      LAYER M3 ;
        RECT 205.956 259.056 205.974 259.200 ;
    END
  END up_out[208]
  PIN up_out[209]
    DIRECTION OUTPUT ;
    USE SIGNAL ;
    PORT
      LAYER M5 ;
        RECT 206.304 259.008 206.328 259.200 ;
    END
  END up_out[209]
  PIN up_out[210]
    DIRECTION OUTPUT ;
    USE SIGNAL ;
    PORT
      LAYER M3 ;
        RECT 206.676 259.056 206.694 259.200 ;
    END
  END up_out[210]
  PIN up_out[211]
    DIRECTION OUTPUT ;
    USE SIGNAL ;
    PORT
      LAYER M5 ;
        RECT 207.024 259.008 207.048 259.200 ;
    END
  END up_out[211]
  PIN up_out[212]
    DIRECTION OUTPUT ;
    USE SIGNAL ;
    PORT
      LAYER M3 ;
        RECT 207.396 259.056 207.414 259.200 ;
    END
  END up_out[212]
  PIN up_out[213]
    DIRECTION OUTPUT ;
    USE SIGNAL ;
    PORT
      LAYER M5 ;
        RECT 207.744 259.008 207.768 259.200 ;
    END
  END up_out[213]
  PIN up_out[214]
    DIRECTION OUTPUT ;
    USE SIGNAL ;
    PORT
      LAYER M3 ;
        RECT 208.116 259.056 208.134 259.200 ;
    END
  END up_out[214]
  PIN up_out[215]
    DIRECTION OUTPUT ;
    USE SIGNAL ;
    PORT
      LAYER M5 ;
        RECT 208.464 259.008 208.488 259.200 ;
    END
  END up_out[215]
  PIN up_out[216]
    DIRECTION OUTPUT ;
    USE SIGNAL ;
    PORT
      LAYER M3 ;
        RECT 208.836 259.056 208.854 259.200 ;
    END
  END up_out[216]
  PIN up_out[217]
    DIRECTION OUTPUT ;
    USE SIGNAL ;
    PORT
      LAYER M5 ;
        RECT 209.184 259.008 209.208 259.200 ;
    END
  END up_out[217]
  PIN up_out[218]
    DIRECTION OUTPUT ;
    USE SIGNAL ;
    PORT
      LAYER M3 ;
        RECT 209.556 259.056 209.574 259.200 ;
    END
  END up_out[218]
  PIN up_out[219]
    DIRECTION OUTPUT ;
    USE SIGNAL ;
    PORT
      LAYER M5 ;
        RECT 209.904 259.008 209.928 259.200 ;
    END
  END up_out[219]
  PIN up_out[220]
    DIRECTION OUTPUT ;
    USE SIGNAL ;
    PORT
      LAYER M3 ;
        RECT 210.276 259.056 210.294 259.200 ;
    END
  END up_out[220]
  PIN up_out[221]
    DIRECTION OUTPUT ;
    USE SIGNAL ;
    PORT
      LAYER M5 ;
        RECT 210.624 259.008 210.648 259.200 ;
    END
  END up_out[221]
  PIN up_out[222]
    DIRECTION OUTPUT ;
    USE SIGNAL ;
    PORT
      LAYER M3 ;
        RECT 210.996 259.056 211.014 259.200 ;
    END
  END up_out[222]
  PIN up_out[223]
    DIRECTION OUTPUT ;
    USE SIGNAL ;
    PORT
      LAYER M5 ;
        RECT 211.344 259.008 211.368 259.200 ;
    END
  END up_out[223]
  PIN up_out[224]
    DIRECTION OUTPUT ;
    USE SIGNAL ;
    PORT
      LAYER M3 ;
        RECT 211.716 259.056 211.734 259.200 ;
    END
  END up_out[224]
  PIN up_out[225]
    DIRECTION OUTPUT ;
    USE SIGNAL ;
    PORT
      LAYER M5 ;
        RECT 212.064 259.008 212.088 259.200 ;
    END
  END up_out[225]
  PIN up_out[226]
    DIRECTION OUTPUT ;
    USE SIGNAL ;
    PORT
      LAYER M3 ;
        RECT 212.436 259.056 212.454 259.200 ;
    END
  END up_out[226]
  PIN up_out[227]
    DIRECTION OUTPUT ;
    USE SIGNAL ;
    PORT
      LAYER M5 ;
        RECT 212.784 259.008 212.808 259.200 ;
    END
  END up_out[227]
  PIN up_out[228]
    DIRECTION OUTPUT ;
    USE SIGNAL ;
    PORT
      LAYER M3 ;
        RECT 213.156 259.056 213.174 259.200 ;
    END
  END up_out[228]
  PIN up_out[229]
    DIRECTION OUTPUT ;
    USE SIGNAL ;
    PORT
      LAYER M5 ;
        RECT 213.552 259.008 213.576 259.200 ;
    END
  END up_out[229]
  PIN up_out[230]
    DIRECTION OUTPUT ;
    USE SIGNAL ;
    PORT
      LAYER M3 ;
        RECT 213.876 259.056 213.894 259.200 ;
    END
  END up_out[230]
  PIN up_out[231]
    DIRECTION OUTPUT ;
    USE SIGNAL ;
    PORT
      LAYER M5 ;
        RECT 214.272 259.008 214.296 259.200 ;
    END
  END up_out[231]
  PIN up_out[232]
    DIRECTION OUTPUT ;
    USE SIGNAL ;
    PORT
      LAYER M3 ;
        RECT 214.632 259.056 214.650 259.200 ;
    END
  END up_out[232]
  PIN up_out[233]
    DIRECTION OUTPUT ;
    USE SIGNAL ;
    PORT
      LAYER M5 ;
        RECT 214.992 259.008 215.016 259.200 ;
    END
  END up_out[233]
  PIN up_out[234]
    DIRECTION OUTPUT ;
    USE SIGNAL ;
    PORT
      LAYER M3 ;
        RECT 215.352 259.056 215.370 259.200 ;
    END
  END up_out[234]
  PIN up_out[235]
    DIRECTION OUTPUT ;
    USE SIGNAL ;
    PORT
      LAYER M5 ;
        RECT 215.712 259.008 215.736 259.200 ;
    END
  END up_out[235]
  PIN up_out[236]
    DIRECTION OUTPUT ;
    USE SIGNAL ;
    PORT
      LAYER M3 ;
        RECT 216.072 259.056 216.090 259.200 ;
    END
  END up_out[236]
  PIN up_out[237]
    DIRECTION OUTPUT ;
    USE SIGNAL ;
    PORT
      LAYER M5 ;
        RECT 216.432 259.008 216.456 259.200 ;
    END
  END up_out[237]
  PIN up_out[238]
    DIRECTION OUTPUT ;
    USE SIGNAL ;
    PORT
      LAYER M3 ;
        RECT 216.792 259.056 216.810 259.200 ;
    END
  END up_out[238]
  PIN up_out[239]
    DIRECTION OUTPUT ;
    USE SIGNAL ;
    PORT
      LAYER M5 ;
        RECT 217.152 259.008 217.176 259.200 ;
    END
  END up_out[239]
  PIN up_out[240]
    DIRECTION OUTPUT ;
    USE SIGNAL ;
    PORT
      LAYER M3 ;
        RECT 217.512 259.056 217.530 259.200 ;
    END
  END up_out[240]
  PIN up_out[241]
    DIRECTION OUTPUT ;
    USE SIGNAL ;
    PORT
      LAYER M5 ;
        RECT 217.872 259.008 217.896 259.200 ;
    END
  END up_out[241]
  PIN up_out[242]
    DIRECTION OUTPUT ;
    USE SIGNAL ;
    PORT
      LAYER M3 ;
        RECT 218.232 259.056 218.250 259.200 ;
    END
  END up_out[242]
  PIN up_out[243]
    DIRECTION OUTPUT ;
    USE SIGNAL ;
    PORT
      LAYER M5 ;
        RECT 218.592 259.008 218.616 259.200 ;
    END
  END up_out[243]
  PIN up_out[244]
    DIRECTION OUTPUT ;
    USE SIGNAL ;
    PORT
      LAYER M3 ;
        RECT 218.952 259.056 218.970 259.200 ;
    END
  END up_out[244]
  PIN up_out[245]
    DIRECTION OUTPUT ;
    USE SIGNAL ;
    PORT
      LAYER M5 ;
        RECT 219.312 259.008 219.336 259.200 ;
    END
  END up_out[245]
  PIN up_out[246]
    DIRECTION OUTPUT ;
    USE SIGNAL ;
    PORT
      LAYER M3 ;
        RECT 219.672 259.056 219.690 259.200 ;
    END
  END up_out[246]
  PIN up_out[247]
    DIRECTION OUTPUT ;
    USE SIGNAL ;
    PORT
      LAYER M5 ;
        RECT 220.032 259.008 220.056 259.200 ;
    END
  END up_out[247]
  PIN up_out[248]
    DIRECTION OUTPUT ;
    USE SIGNAL ;
    PORT
      LAYER M3 ;
        RECT 220.392 259.056 220.410 259.200 ;
    END
  END up_out[248]
  PIN up_out[249]
    DIRECTION OUTPUT ;
    USE SIGNAL ;
    PORT
      LAYER M5 ;
        RECT 220.752 259.008 220.776 259.200 ;
    END
  END up_out[249]
  PIN up_out[250]
    DIRECTION OUTPUT ;
    USE SIGNAL ;
    PORT
      LAYER M3 ;
        RECT 221.112 259.056 221.130 259.200 ;
    END
  END up_out[250]
  PIN up_out[251]
    DIRECTION OUTPUT ;
    USE SIGNAL ;
    PORT
      LAYER M5 ;
        RECT 221.472 259.008 221.496 259.200 ;
    END
  END up_out[251]
  PIN up_out[252]
    DIRECTION OUTPUT ;
    USE SIGNAL ;
    PORT
      LAYER M3 ;
        RECT 221.832 259.056 221.850 259.200 ;
    END
  END up_out[252]
  PIN up_out[253]
    DIRECTION OUTPUT ;
    USE SIGNAL ;
    PORT
      LAYER M5 ;
        RECT 222.192 259.008 222.216 259.200 ;
    END
  END up_out[253]
  PIN up_out[254]
    DIRECTION OUTPUT ;
    USE SIGNAL ;
    PORT
      LAYER M3 ;
        RECT 222.552 259.056 222.570 259.200 ;
    END
  END up_out[254]
  PIN up_out[255]
    DIRECTION OUTPUT ;
    USE SIGNAL ;
    PORT
      LAYER M5 ;
        RECT 222.912 259.008 222.936 259.200 ;
    END
  END up_out[255]
  PIN up_out[256]
    DIRECTION OUTPUT ;
    USE SIGNAL ;
    PORT
      LAYER M3 ;
        RECT 223.272 259.056 223.290 259.200 ;
    END
  END up_out[256]
  PIN up_out[257]
    DIRECTION OUTPUT ;
    USE SIGNAL ;
    PORT
      LAYER M5 ;
        RECT 223.632 259.008 223.656 259.200 ;
    END
  END up_out[257]
  PIN up_out[258]
    DIRECTION OUTPUT ;
    USE SIGNAL ;
    PORT
      LAYER M3 ;
        RECT 223.992 259.056 224.010 259.200 ;
    END
  END up_out[258]
  PIN up_out[259]
    DIRECTION OUTPUT ;
    USE SIGNAL ;
    PORT
      LAYER M5 ;
        RECT 224.352 259.008 224.376 259.200 ;
    END
  END up_out[259]
  PIN up_out[260]
    DIRECTION OUTPUT ;
    USE SIGNAL ;
    PORT
      LAYER M3 ;
        RECT 224.712 259.056 224.730 259.200 ;
    END
  END up_out[260]
  PIN up_out[261]
    DIRECTION OUTPUT ;
    USE SIGNAL ;
    PORT
      LAYER M5 ;
        RECT 225.072 259.008 225.096 259.200 ;
    END
  END up_out[261]
  PIN up_out[262]
    DIRECTION OUTPUT ;
    USE SIGNAL ;
    PORT
      LAYER M3 ;
        RECT 225.432 259.056 225.450 259.200 ;
    END
  END up_out[262]
  PIN up_out[263]
    DIRECTION OUTPUT ;
    USE SIGNAL ;
    PORT
      LAYER M5 ;
        RECT 225.792 259.008 225.816 259.200 ;
    END
  END up_out[263]
  PIN up_out[264]
    DIRECTION OUTPUT ;
    USE SIGNAL ;
    PORT
      LAYER M3 ;
        RECT 226.152 259.056 226.170 259.200 ;
    END
  END up_out[264]
  PIN up_out[265]
    DIRECTION OUTPUT ;
    USE SIGNAL ;
    PORT
      LAYER M5 ;
        RECT 226.512 259.008 226.536 259.200 ;
    END
  END up_out[265]
  PIN up_out[266]
    DIRECTION OUTPUT ;
    USE SIGNAL ;
    PORT
      LAYER M3 ;
        RECT 226.908 259.056 226.926 259.200 ;
    END
  END up_out[266]
  PIN up_out[267]
    DIRECTION OUTPUT ;
    USE SIGNAL ;
    PORT
      LAYER M5 ;
        RECT 227.232 259.008 227.256 259.200 ;
    END
  END up_out[267]
  PIN up_out[268]
    DIRECTION OUTPUT ;
    USE SIGNAL ;
    PORT
      LAYER M3 ;
        RECT 227.628 259.056 227.646 259.200 ;
    END
  END up_out[268]
  PIN up_out[269]
    DIRECTION OUTPUT ;
    USE SIGNAL ;
    PORT
      LAYER M5 ;
        RECT 227.952 259.008 227.976 259.200 ;
    END
  END up_out[269]
  PIN up_out[270]
    DIRECTION OUTPUT ;
    USE SIGNAL ;
    PORT
      LAYER M3 ;
        RECT 228.348 259.056 228.366 259.200 ;
    END
  END up_out[270]
  PIN up_out[271]
    DIRECTION OUTPUT ;
    USE SIGNAL ;
    PORT
      LAYER M5 ;
        RECT 228.672 259.008 228.696 259.200 ;
    END
  END up_out[271]
  PIN up_out[272]
    DIRECTION OUTPUT ;
    USE SIGNAL ;
    PORT
      LAYER M3 ;
        RECT 229.068 259.056 229.086 259.200 ;
    END
  END up_out[272]
  PIN up_out[273]
    DIRECTION OUTPUT ;
    USE SIGNAL ;
    PORT
      LAYER M5 ;
        RECT 229.392 259.008 229.416 259.200 ;
    END
  END up_out[273]
  PIN up_out[274]
    DIRECTION OUTPUT ;
    USE SIGNAL ;
    PORT
      LAYER M3 ;
        RECT 229.788 259.056 229.806 259.200 ;
    END
  END up_out[274]
  PIN up_out[275]
    DIRECTION OUTPUT ;
    USE SIGNAL ;
    PORT
      LAYER M5 ;
        RECT 230.160 259.008 230.184 259.200 ;
    END
  END up_out[275]
  PIN up_out[276]
    DIRECTION OUTPUT ;
    USE SIGNAL ;
    PORT
      LAYER M3 ;
        RECT 230.508 259.056 230.526 259.200 ;
    END
  END up_out[276]
  PIN up_out[277]
    DIRECTION OUTPUT ;
    USE SIGNAL ;
    PORT
      LAYER M5 ;
        RECT 230.880 259.008 230.904 259.200 ;
    END
  END up_out[277]
  PIN up_out[278]
    DIRECTION OUTPUT ;
    USE SIGNAL ;
    PORT
      LAYER M3 ;
        RECT 231.228 259.056 231.246 259.200 ;
    END
  END up_out[278]
  PIN up_out[279]
    DIRECTION OUTPUT ;
    USE SIGNAL ;
    PORT
      LAYER M5 ;
        RECT 231.600 259.008 231.624 259.200 ;
    END
  END up_out[279]
  PIN up_out[280]
    DIRECTION OUTPUT ;
    USE SIGNAL ;
    PORT
      LAYER M3 ;
        RECT 231.948 259.056 231.966 259.200 ;
    END
  END up_out[280]
  PIN up_out[281]
    DIRECTION OUTPUT ;
    USE SIGNAL ;
    PORT
      LAYER M5 ;
        RECT 232.320 259.008 232.344 259.200 ;
    END
  END up_out[281]
  PIN up_out[282]
    DIRECTION OUTPUT ;
    USE SIGNAL ;
    PORT
      LAYER M3 ;
        RECT 232.668 259.056 232.686 259.200 ;
    END
  END up_out[282]
  PIN up_out[283]
    DIRECTION OUTPUT ;
    USE SIGNAL ;
    PORT
      LAYER M5 ;
        RECT 233.040 259.008 233.064 259.200 ;
    END
  END up_out[283]
  PIN up_out[284]
    DIRECTION OUTPUT ;
    USE SIGNAL ;
    PORT
      LAYER M3 ;
        RECT 233.388 259.056 233.406 259.200 ;
    END
  END up_out[284]
  PIN up_out[285]
    DIRECTION OUTPUT ;
    USE SIGNAL ;
    PORT
      LAYER M5 ;
        RECT 233.760 259.008 233.784 259.200 ;
    END
  END up_out[285]
  PIN up_out[286]
    DIRECTION OUTPUT ;
    USE SIGNAL ;
    PORT
      LAYER M3 ;
        RECT 234.108 259.056 234.126 259.200 ;
    END
  END up_out[286]
  PIN up_out[287]
    DIRECTION OUTPUT ;
    USE SIGNAL ;
    PORT
      LAYER M5 ;
        RECT 234.480 259.008 234.504 259.200 ;
    END
  END up_out[287]
  PIN up_out[288]
    DIRECTION OUTPUT ;
    USE SIGNAL ;
    PORT
      LAYER M3 ;
        RECT 234.828 259.056 234.846 259.200 ;
    END
  END up_out[288]
  PIN up_out[289]
    DIRECTION OUTPUT ;
    USE SIGNAL ;
    PORT
      LAYER M5 ;
        RECT 235.200 259.008 235.224 259.200 ;
    END
  END up_out[289]
  PIN up_out[290]
    DIRECTION OUTPUT ;
    USE SIGNAL ;
    PORT
      LAYER M3 ;
        RECT 235.548 259.056 235.566 259.200 ;
    END
  END up_out[290]
  PIN up_out[291]
    DIRECTION OUTPUT ;
    USE SIGNAL ;
    PORT
      LAYER M5 ;
        RECT 235.920 259.008 235.944 259.200 ;
    END
  END up_out[291]
  PIN up_out[292]
    DIRECTION OUTPUT ;
    USE SIGNAL ;
    PORT
      LAYER M3 ;
        RECT 236.268 259.056 236.286 259.200 ;
    END
  END up_out[292]
  PIN up_out[293]
    DIRECTION OUTPUT ;
    USE SIGNAL ;
    PORT
      LAYER M5 ;
        RECT 236.640 259.008 236.664 259.200 ;
    END
  END up_out[293]
  PIN up_out[294]
    DIRECTION OUTPUT ;
    USE SIGNAL ;
    PORT
      LAYER M3 ;
        RECT 236.988 259.056 237.006 259.200 ;
    END
  END up_out[294]
  PIN up_out[295]
    DIRECTION OUTPUT ;
    USE SIGNAL ;
    PORT
      LAYER M5 ;
        RECT 237.360 259.008 237.384 259.200 ;
    END
  END up_out[295]
  PIN up_out[296]
    DIRECTION OUTPUT ;
    USE SIGNAL ;
    PORT
      LAYER M3 ;
        RECT 237.708 259.056 237.726 259.200 ;
    END
  END up_out[296]
  PIN up_out[297]
    DIRECTION OUTPUT ;
    USE SIGNAL ;
    PORT
      LAYER M5 ;
        RECT 238.080 259.008 238.104 259.200 ;
    END
  END up_out[297]
  PIN up_out[298]
    DIRECTION OUTPUT ;
    USE SIGNAL ;
    PORT
      LAYER M3 ;
        RECT 238.428 259.056 238.446 259.200 ;
    END
  END up_out[298]
  PIN up_out[299]
    DIRECTION OUTPUT ;
    USE SIGNAL ;
    PORT
      LAYER M5 ;
        RECT 238.800 259.008 238.824 259.200 ;
    END
  END up_out[299]
  PIN up_out[300]
    DIRECTION OUTPUT ;
    USE SIGNAL ;
    PORT
      LAYER M3 ;
        RECT 239.148 259.056 239.166 259.200 ;
    END
  END up_out[300]
  PIN up_out[301]
    DIRECTION OUTPUT ;
    USE SIGNAL ;
    PORT
      LAYER M5 ;
        RECT 239.520 259.008 239.544 259.200 ;
    END
  END up_out[301]
  PIN up_out[302]
    DIRECTION OUTPUT ;
    USE SIGNAL ;
    PORT
      LAYER M3 ;
        RECT 239.904 259.056 239.922 259.200 ;
    END
  END up_out[302]
  PIN up_out[303]
    DIRECTION OUTPUT ;
    USE SIGNAL ;
    PORT
      LAYER M5 ;
        RECT 240.240 259.008 240.264 259.200 ;
    END
  END up_out[303]
  PIN up_out[304]
    DIRECTION OUTPUT ;
    USE SIGNAL ;
    PORT
      LAYER M3 ;
        RECT 240.624 259.056 240.642 259.200 ;
    END
  END up_out[304]
  PIN up_out[305]
    DIRECTION OUTPUT ;
    USE SIGNAL ;
    PORT
      LAYER M5 ;
        RECT 240.960 259.008 240.984 259.200 ;
    END
  END up_out[305]
  PIN up_out[306]
    DIRECTION OUTPUT ;
    USE SIGNAL ;
    PORT
      LAYER M3 ;
        RECT 241.344 259.056 241.362 259.200 ;
    END
  END up_out[306]
  PIN up_out[307]
    DIRECTION OUTPUT ;
    USE SIGNAL ;
    PORT
      LAYER M5 ;
        RECT 241.680 259.008 241.704 259.200 ;
    END
  END up_out[307]
  PIN up_out[308]
    DIRECTION OUTPUT ;
    USE SIGNAL ;
    PORT
      LAYER M3 ;
        RECT 242.064 259.056 242.082 259.200 ;
    END
  END up_out[308]
  PIN up_out[309]
    DIRECTION OUTPUT ;
    USE SIGNAL ;
    PORT
      LAYER M5 ;
        RECT 242.400 259.008 242.424 259.200 ;
    END
  END up_out[309]
  PIN up_out[310]
    DIRECTION OUTPUT ;
    USE SIGNAL ;
    PORT
      LAYER M3 ;
        RECT 242.784 259.056 242.802 259.200 ;
    END
  END up_out[310]
  PIN up_out[311]
    DIRECTION OUTPUT ;
    USE SIGNAL ;
    PORT
      LAYER M5 ;
        RECT 243.120 259.008 243.144 259.200 ;
    END
  END up_out[311]
  PIN up_out[312]
    DIRECTION OUTPUT ;
    USE SIGNAL ;
    PORT
      LAYER M3 ;
        RECT 243.504 259.056 243.522 259.200 ;
    END
  END up_out[312]
  PIN up_out[313]
    DIRECTION OUTPUT ;
    USE SIGNAL ;
    PORT
      LAYER M5 ;
        RECT 243.840 259.008 243.864 259.200 ;
    END
  END up_out[313]
  PIN up_out[314]
    DIRECTION OUTPUT ;
    USE SIGNAL ;
    PORT
      LAYER M3 ;
        RECT 244.224 259.056 244.242 259.200 ;
    END
  END up_out[314]
  PIN up_out[315]
    DIRECTION OUTPUT ;
    USE SIGNAL ;
    PORT
      LAYER M5 ;
        RECT 244.560 259.008 244.584 259.200 ;
    END
  END up_out[315]
  PIN up_out[316]
    DIRECTION OUTPUT ;
    USE SIGNAL ;
    PORT
      LAYER M3 ;
        RECT 244.944 259.056 244.962 259.200 ;
    END
  END up_out[316]
  PIN up_out[317]
    DIRECTION OUTPUT ;
    USE SIGNAL ;
    PORT
      LAYER M5 ;
        RECT 245.280 259.008 245.304 259.200 ;
    END
  END up_out[317]
  PIN up_out[318]
    DIRECTION OUTPUT ;
    USE SIGNAL ;
    PORT
      LAYER M3 ;
        RECT 245.664 259.056 245.682 259.200 ;
    END
  END up_out[318]
  PIN up_out[319]
    DIRECTION OUTPUT ;
    USE SIGNAL ;
    PORT
      LAYER M5 ;
        RECT 246.000 259.008 246.024 259.200 ;
    END
  END up_out[319]
  PIN up_out[320]
    DIRECTION OUTPUT ;
    USE SIGNAL ;
    PORT
      LAYER M3 ;
        RECT 246.384 259.056 246.402 259.200 ;
    END
  END up_out[320]
  PIN up_out[321]
    DIRECTION OUTPUT ;
    USE SIGNAL ;
    PORT
      LAYER M5 ;
        RECT 246.768 259.008 246.792 259.200 ;
    END
  END up_out[321]
  PIN up_out[322]
    DIRECTION OUTPUT ;
    USE SIGNAL ;
    PORT
      LAYER M3 ;
        RECT 247.104 259.056 247.122 259.200 ;
    END
  END up_out[322]
  PIN up_out[323]
    DIRECTION OUTPUT ;
    USE SIGNAL ;
    PORT
      LAYER M5 ;
        RECT 247.488 259.008 247.512 259.200 ;
    END
  END up_out[323]
  PIN up_out[324]
    DIRECTION OUTPUT ;
    USE SIGNAL ;
    PORT
      LAYER M3 ;
        RECT 247.824 259.056 247.842 259.200 ;
    END
  END up_out[324]
  PIN up_out[325]
    DIRECTION OUTPUT ;
    USE SIGNAL ;
    PORT
      LAYER M5 ;
        RECT 248.208 259.008 248.232 259.200 ;
    END
  END up_out[325]
  PIN up_out[326]
    DIRECTION OUTPUT ;
    USE SIGNAL ;
    PORT
      LAYER M3 ;
        RECT 248.544 259.056 248.562 259.200 ;
    END
  END up_out[326]
  PIN up_out[327]
    DIRECTION OUTPUT ;
    USE SIGNAL ;
    PORT
      LAYER M5 ;
        RECT 248.928 259.008 248.952 259.200 ;
    END
  END up_out[327]
  PIN up_out[328]
    DIRECTION OUTPUT ;
    USE SIGNAL ;
    PORT
      LAYER M3 ;
        RECT 249.264 259.056 249.282 259.200 ;
    END
  END up_out[328]
  PIN up_out[329]
    DIRECTION OUTPUT ;
    USE SIGNAL ;
    PORT
      LAYER M5 ;
        RECT 249.648 259.008 249.672 259.200 ;
    END
  END up_out[329]
  PIN up_out[330]
    DIRECTION OUTPUT ;
    USE SIGNAL ;
    PORT
      LAYER M3 ;
        RECT 249.984 259.056 250.002 259.200 ;
    END
  END up_out[330]
  PIN up_out[331]
    DIRECTION OUTPUT ;
    USE SIGNAL ;
    PORT
      LAYER M5 ;
        RECT 250.368 259.008 250.392 259.200 ;
    END
  END up_out[331]
  PIN up_out[332]
    DIRECTION OUTPUT ;
    USE SIGNAL ;
    PORT
      LAYER M3 ;
        RECT 250.704 259.056 250.722 259.200 ;
    END
  END up_out[332]
  PIN up_out[333]
    DIRECTION OUTPUT ;
    USE SIGNAL ;
    PORT
      LAYER M5 ;
        RECT 251.088 259.008 251.112 259.200 ;
    END
  END up_out[333]
  PIN up_out[334]
    DIRECTION OUTPUT ;
    USE SIGNAL ;
    PORT
      LAYER M3 ;
        RECT 251.424 259.056 251.442 259.200 ;
    END
  END up_out[334]
  PIN up_out[335]
    DIRECTION OUTPUT ;
    USE SIGNAL ;
    PORT
      LAYER M5 ;
        RECT 251.808 259.008 251.832 259.200 ;
    END
  END up_out[335]
  PIN up_out[336]
    DIRECTION OUTPUT ;
    USE SIGNAL ;
    PORT
      LAYER M3 ;
        RECT 252.180 259.056 252.198 259.200 ;
    END
  END up_out[336]
  PIN up_out[337]
    DIRECTION OUTPUT ;
    USE SIGNAL ;
    PORT
      LAYER M5 ;
        RECT 252.528 259.008 252.552 259.200 ;
    END
  END up_out[337]
  PIN up_out[338]
    DIRECTION OUTPUT ;
    USE SIGNAL ;
    PORT
      LAYER M3 ;
        RECT 252.900 259.056 252.918 259.200 ;
    END
  END up_out[338]
  PIN up_out[339]
    DIRECTION OUTPUT ;
    USE SIGNAL ;
    PORT
      LAYER M5 ;
        RECT 253.248 259.008 253.272 259.200 ;
    END
  END up_out[339]
  PIN up_out[340]
    DIRECTION OUTPUT ;
    USE SIGNAL ;
    PORT
      LAYER M3 ;
        RECT 253.620 259.056 253.638 259.200 ;
    END
  END up_out[340]
  PIN up_out[341]
    DIRECTION OUTPUT ;
    USE SIGNAL ;
    PORT
      LAYER M5 ;
        RECT 253.968 259.008 253.992 259.200 ;
    END
  END up_out[341]
  PIN up_out[342]
    DIRECTION OUTPUT ;
    USE SIGNAL ;
    PORT
      LAYER M3 ;
        RECT 254.340 259.056 254.358 259.200 ;
    END
  END up_out[342]
  PIN up_out[343]
    DIRECTION OUTPUT ;
    USE SIGNAL ;
    PORT
      LAYER M5 ;
        RECT 254.688 259.008 254.712 259.200 ;
    END
  END up_out[343]
  PIN ovf_v
    DIRECTION OUTPUT ;
    USE SIGNAL ;
    PORT
      LAYER M3 ;
        RECT 4.500 0.000 4.518 0.144 ;
    END
  END ovf_v
  PIN ovf_b[0]
    DIRECTION OUTPUT ;
    USE SIGNAL ;
    PORT
      LAYER M5 ;
        RECT 4.848 0.000 4.872 0.192 ;
    END
  END ovf_b[0]
  PIN ovf_b[1]
    DIRECTION OUTPUT ;
    USE SIGNAL ;
    PORT
      LAYER M3 ;
        RECT 5.220 0.000 5.238 0.144 ;
    END
  END ovf_b[1]
  PIN ovf_b[2]
    DIRECTION OUTPUT ;
    USE SIGNAL ;
    PORT
      LAYER M5 ;
        RECT 5.568 0.000 5.592 0.192 ;
    END
  END ovf_b[2]
  PIN ovf_b[3]
    DIRECTION OUTPUT ;
    USE SIGNAL ;
    PORT
      LAYER M3 ;
        RECT 5.940 0.000 5.958 0.144 ;
    END
  END ovf_b[3]
  PIN ovf_b[4]
    DIRECTION OUTPUT ;
    USE SIGNAL ;
    PORT
      LAYER M5 ;
        RECT 6.288 0.000 6.312 0.192 ;
    END
  END ovf_b[4]
  PIN ovf_b[5]
    DIRECTION OUTPUT ;
    USE SIGNAL ;
    PORT
      LAYER M3 ;
        RECT 6.660 0.000 6.678 0.144 ;
    END
  END ovf_b[5]
  PIN ovf_b[6]
    DIRECTION OUTPUT ;
    USE SIGNAL ;
    PORT
      LAYER M5 ;
        RECT 7.056 0.000 7.080 0.192 ;
    END
  END ovf_b[6]
  PIN ovf_b[7]
    DIRECTION OUTPUT ;
    USE SIGNAL ;
    PORT
      LAYER M3 ;
        RECT 7.416 0.000 7.434 0.144 ;
    END
  END ovf_b[7]
  PIN ovf_b[8]
    DIRECTION OUTPUT ;
    USE SIGNAL ;
    PORT
      LAYER M5 ;
        RECT 7.776 0.000 7.800 0.192 ;
    END
  END ovf_b[8]
  PIN ovf_b[9]
    DIRECTION OUTPUT ;
    USE SIGNAL ;
    PORT
      LAYER M3 ;
        RECT 8.136 0.000 8.154 0.144 ;
    END
  END ovf_b[9]
  PIN ovf_b[10]
    DIRECTION OUTPUT ;
    USE SIGNAL ;
    PORT
      LAYER M5 ;
        RECT 8.496 0.000 8.520 0.192 ;
    END
  END ovf_b[10]
  PIN ovf_b[11]
    DIRECTION OUTPUT ;
    USE SIGNAL ;
    PORT
      LAYER M3 ;
        RECT 8.856 0.000 8.874 0.144 ;
    END
  END ovf_b[11]
  PIN ovf_b[12]
    DIRECTION OUTPUT ;
    USE SIGNAL ;
    PORT
      LAYER M5 ;
        RECT 9.216 0.000 9.240 0.192 ;
    END
  END ovf_b[12]
  PIN ovf_b[13]
    DIRECTION OUTPUT ;
    USE SIGNAL ;
    PORT
      LAYER M3 ;
        RECT 9.576 0.000 9.594 0.144 ;
    END
  END ovf_b[13]
  PIN ovf_b[14]
    DIRECTION OUTPUT ;
    USE SIGNAL ;
    PORT
      LAYER M5 ;
        RECT 9.936 0.000 9.960 0.192 ;
    END
  END ovf_b[14]
  PIN ovf_b[15]
    DIRECTION OUTPUT ;
    USE SIGNAL ;
    PORT
      LAYER M3 ;
        RECT 10.296 0.000 10.314 0.144 ;
    END
  END ovf_b[15]
  PIN ovf_b[16]
    DIRECTION OUTPUT ;
    USE SIGNAL ;
    PORT
      LAYER M5 ;
        RECT 10.656 0.000 10.680 0.192 ;
    END
  END ovf_b[16]
  PIN ovf_b[17]
    DIRECTION OUTPUT ;
    USE SIGNAL ;
    PORT
      LAYER M3 ;
        RECT 11.052 0.000 11.070 0.144 ;
    END
  END ovf_b[17]
  PIN ovf_b[18]
    DIRECTION OUTPUT ;
    USE SIGNAL ;
    PORT
      LAYER M5 ;
        RECT 11.376 0.000 11.400 0.192 ;
    END
  END ovf_b[18]
  PIN ovf_b[19]
    DIRECTION OUTPUT ;
    USE SIGNAL ;
    PORT
      LAYER M3 ;
        RECT 11.772 0.000 11.790 0.144 ;
    END
  END ovf_b[19]
  PIN ovf_b[20]
    DIRECTION OUTPUT ;
    USE SIGNAL ;
    PORT
      LAYER M5 ;
        RECT 12.144 0.000 12.168 0.192 ;
    END
  END ovf_b[20]
  PIN ovf_b[21]
    DIRECTION OUTPUT ;
    USE SIGNAL ;
    PORT
      LAYER M3 ;
        RECT 12.492 0.000 12.510 0.144 ;
    END
  END ovf_b[21]
  PIN ovf_b[22]
    DIRECTION OUTPUT ;
    USE SIGNAL ;
    PORT
      LAYER M5 ;
        RECT 12.864 0.000 12.888 0.192 ;
    END
  END ovf_b[22]
  PIN ovf_b[23]
    DIRECTION OUTPUT ;
    USE SIGNAL ;
    PORT
      LAYER M3 ;
        RECT 13.212 0.000 13.230 0.144 ;
    END
  END ovf_b[23]
  PIN ovf_b[24]
    DIRECTION OUTPUT ;
    USE SIGNAL ;
    PORT
      LAYER M5 ;
        RECT 13.584 0.000 13.608 0.192 ;
    END
  END ovf_b[24]
  PIN ovf_b[25]
    DIRECTION OUTPUT ;
    USE SIGNAL ;
    PORT
      LAYER M3 ;
        RECT 13.932 0.000 13.950 0.144 ;
    END
  END ovf_b[25]
  PIN ovf_b[26]
    DIRECTION OUTPUT ;
    USE SIGNAL ;
    PORT
      LAYER M5 ;
        RECT 14.304 0.000 14.328 0.192 ;
    END
  END ovf_b[26]
  PIN ovf_b[27]
    DIRECTION OUTPUT ;
    USE SIGNAL ;
    PORT
      LAYER M3 ;
        RECT 14.688 0.000 14.706 0.144 ;
    END
  END ovf_b[27]
  PIN ovf_b[28]
    DIRECTION OUTPUT ;
    USE SIGNAL ;
    PORT
      LAYER M5 ;
        RECT 15.024 0.000 15.048 0.192 ;
    END
  END ovf_b[28]
  PIN ovf_b[29]
    DIRECTION OUTPUT ;
    USE SIGNAL ;
    PORT
      LAYER M3 ;
        RECT 15.408 0.000 15.426 0.144 ;
    END
  END ovf_b[29]
  PIN ovf_b[30]
    DIRECTION OUTPUT ;
    USE SIGNAL ;
    PORT
      LAYER M5 ;
        RECT 15.744 0.000 15.768 0.192 ;
    END
  END ovf_b[30]
  PIN ovf_b[31]
    DIRECTION OUTPUT ;
    USE SIGNAL ;
    PORT
      LAYER M3 ;
        RECT 16.128 0.000 16.146 0.144 ;
    END
  END ovf_b[31]
  PIN ovf_b[32]
    DIRECTION OUTPUT ;
    USE SIGNAL ;
    PORT
      LAYER M5 ;
        RECT 16.512 0.000 16.536 0.192 ;
    END
  END ovf_b[32]
  PIN ovf_b[33]
    DIRECTION OUTPUT ;
    USE SIGNAL ;
    PORT
      LAYER M3 ;
        RECT 16.848 0.000 16.866 0.144 ;
    END
  END ovf_b[33]
  PIN ovf_b[34]
    DIRECTION OUTPUT ;
    USE SIGNAL ;
    PORT
      LAYER M5 ;
        RECT 17.232 0.000 17.256 0.192 ;
    END
  END ovf_b[34]
  PIN ovf_b[35]
    DIRECTION OUTPUT ;
    USE SIGNAL ;
    PORT
      LAYER M3 ;
        RECT 17.568 0.000 17.586 0.144 ;
    END
  END ovf_b[35]
  PIN ovf_b[36]
    DIRECTION OUTPUT ;
    USE SIGNAL ;
    PORT
      LAYER M5 ;
        RECT 17.952 0.000 17.976 0.192 ;
    END
  END ovf_b[36]
  PIN ovf_b[37]
    DIRECTION OUTPUT ;
    USE SIGNAL ;
    PORT
      LAYER M3 ;
        RECT 18.324 0.000 18.342 0.144 ;
    END
  END ovf_b[37]
  PIN ovf_b[38]
    DIRECTION OUTPUT ;
    USE SIGNAL ;
    PORT
      LAYER M5 ;
        RECT 18.672 0.000 18.696 0.192 ;
    END
  END ovf_b[38]
  PIN ovf_b[39]
    DIRECTION OUTPUT ;
    USE SIGNAL ;
    PORT
      LAYER M3 ;
        RECT 19.044 0.000 19.062 0.144 ;
    END
  END ovf_b[39]
  PIN ovf_b[40]
    DIRECTION OUTPUT ;
    USE SIGNAL ;
    PORT
      LAYER M5 ;
        RECT 19.392 0.000 19.416 0.192 ;
    END
  END ovf_b[40]
  PIN ovf_b[41]
    DIRECTION OUTPUT ;
    USE SIGNAL ;
    PORT
      LAYER M3 ;
        RECT 19.764 0.000 19.782 0.144 ;
    END
  END ovf_b[41]
  PIN ovf_b[42]
    DIRECTION OUTPUT ;
    USE SIGNAL ;
    PORT
      LAYER M5 ;
        RECT 20.112 0.000 20.136 0.192 ;
    END
  END ovf_b[42]
  PIN ovf_b[43]
    DIRECTION OUTPUT ;
    USE SIGNAL ;
    PORT
      LAYER M3 ;
        RECT 20.484 0.000 20.502 0.144 ;
    END
  END ovf_b[43]
  PIN ovf_b[44]
    DIRECTION OUTPUT ;
    USE SIGNAL ;
    PORT
      LAYER M5 ;
        RECT 20.832 0.000 20.856 0.192 ;
    END
  END ovf_b[44]
  PIN ovf_b[45]
    DIRECTION OUTPUT ;
    USE SIGNAL ;
    PORT
      LAYER M3 ;
        RECT 21.204 0.000 21.222 0.144 ;
    END
  END ovf_b[45]
  PIN ovf_b[46]
    DIRECTION OUTPUT ;
    USE SIGNAL ;
    PORT
      LAYER M5 ;
        RECT 21.600 0.000 21.624 0.192 ;
    END
  END ovf_b[46]
  PIN ovf_b[47]
    DIRECTION OUTPUT ;
    USE SIGNAL ;
    PORT
      LAYER M3 ;
        RECT 21.960 0.000 21.978 0.144 ;
    END
  END ovf_b[47]
  PIN ovf_b[48]
    DIRECTION OUTPUT ;
    USE SIGNAL ;
    PORT
      LAYER M5 ;
        RECT 22.320 0.000 22.344 0.192 ;
    END
  END ovf_b[48]
  PIN ovf_b[49]
    DIRECTION OUTPUT ;
    USE SIGNAL ;
    PORT
      LAYER M3 ;
        RECT 22.680 0.000 22.698 0.144 ;
    END
  END ovf_b[49]
  PIN ovf_b[50]
    DIRECTION OUTPUT ;
    USE SIGNAL ;
    PORT
      LAYER M5 ;
        RECT 23.040 0.000 23.064 0.192 ;
    END
  END ovf_b[50]
  PIN ovf_b[51]
    DIRECTION OUTPUT ;
    USE SIGNAL ;
    PORT
      LAYER M3 ;
        RECT 23.400 0.000 23.418 0.144 ;
    END
  END ovf_b[51]
  PIN ovf_b[52]
    DIRECTION OUTPUT ;
    USE SIGNAL ;
    PORT
      LAYER M5 ;
        RECT 23.760 0.000 23.784 0.192 ;
    END
  END ovf_b[52]
  PIN ovf_b[53]
    DIRECTION OUTPUT ;
    USE SIGNAL ;
    PORT
      LAYER M3 ;
        RECT 24.120 0.000 24.138 0.144 ;
    END
  END ovf_b[53]
  PIN ovf_b[54]
    DIRECTION OUTPUT ;
    USE SIGNAL ;
    PORT
      LAYER M5 ;
        RECT 24.480 0.000 24.504 0.192 ;
    END
  END ovf_b[54]
  PIN ovf_b[55]
    DIRECTION OUTPUT ;
    USE SIGNAL ;
    PORT
      LAYER M3 ;
        RECT 24.840 0.000 24.858 0.144 ;
    END
  END ovf_b[55]
  PIN ovf_b[56]
    DIRECTION OUTPUT ;
    USE SIGNAL ;
    PORT
      LAYER M5 ;
        RECT 25.200 0.000 25.224 0.192 ;
    END
  END ovf_b[56]
  PIN ovf_b[57]
    DIRECTION OUTPUT ;
    USE SIGNAL ;
    PORT
      LAYER M3 ;
        RECT 25.596 0.000 25.614 0.144 ;
    END
  END ovf_b[57]
  PIN ovf_b[58]
    DIRECTION OUTPUT ;
    USE SIGNAL ;
    PORT
      LAYER M5 ;
        RECT 25.968 0.000 25.992 0.192 ;
    END
  END ovf_b[58]
  PIN ovf_b[59]
    DIRECTION OUTPUT ;
    USE SIGNAL ;
    PORT
      LAYER M3 ;
        RECT 26.316 0.000 26.334 0.144 ;
    END
  END ovf_b[59]
  PIN ovf_b[60]
    DIRECTION OUTPUT ;
    USE SIGNAL ;
    PORT
      LAYER M5 ;
        RECT 26.688 0.000 26.712 0.192 ;
    END
  END ovf_b[60]
  PIN ovf_b[61]
    DIRECTION OUTPUT ;
    USE SIGNAL ;
    PORT
      LAYER M3 ;
        RECT 27.036 0.000 27.054 0.144 ;
    END
  END ovf_b[61]
  PIN ovf_b[62]
    DIRECTION OUTPUT ;
    USE SIGNAL ;
    PORT
      LAYER M5 ;
        RECT 27.408 0.000 27.432 0.192 ;
    END
  END ovf_b[62]
  PIN ovf_b[63]
    DIRECTION OUTPUT ;
    USE SIGNAL ;
    PORT
      LAYER M3 ;
        RECT 27.756 0.000 27.774 0.144 ;
    END
  END ovf_b[63]
  PIN ovf_b[64]
    DIRECTION OUTPUT ;
    USE SIGNAL ;
    PORT
      LAYER M5 ;
        RECT 28.128 0.000 28.152 0.192 ;
    END
  END ovf_b[64]
  PIN ovf_b[65]
    DIRECTION OUTPUT ;
    USE SIGNAL ;
    PORT
      LAYER M3 ;
        RECT 28.512 0.000 28.530 0.144 ;
    END
  END ovf_b[65]
  PIN ovf_b[66]
    DIRECTION OUTPUT ;
    USE SIGNAL ;
    PORT
      LAYER M5 ;
        RECT 28.848 0.000 28.872 0.192 ;
    END
  END ovf_b[66]
  PIN ovf_b[67]
    DIRECTION OUTPUT ;
    USE SIGNAL ;
    PORT
      LAYER M3 ;
        RECT 29.232 0.000 29.250 0.144 ;
    END
  END ovf_b[67]
  PIN ovf_b[68]
    DIRECTION OUTPUT ;
    USE SIGNAL ;
    PORT
      LAYER M5 ;
        RECT 29.568 0.000 29.592 0.192 ;
    END
  END ovf_b[68]
  PIN ovf_b[69]
    DIRECTION OUTPUT ;
    USE SIGNAL ;
    PORT
      LAYER M3 ;
        RECT 29.952 0.000 29.970 0.144 ;
    END
  END ovf_b[69]
  PIN ovf_b[70]
    DIRECTION OUTPUT ;
    USE SIGNAL ;
    PORT
      LAYER M5 ;
        RECT 30.288 0.000 30.312 0.192 ;
    END
  END ovf_b[70]
  PIN ovf_b[71]
    DIRECTION OUTPUT ;
    USE SIGNAL ;
    PORT
      LAYER M3 ;
        RECT 30.672 0.000 30.690 0.144 ;
    END
  END ovf_b[71]
  PIN ovf_b[72]
    DIRECTION OUTPUT ;
    USE SIGNAL ;
    PORT
      LAYER M5 ;
        RECT 31.056 0.000 31.080 0.192 ;
    END
  END ovf_b[72]
  PIN ovf_b[73]
    DIRECTION OUTPUT ;
    USE SIGNAL ;
    PORT
      LAYER M3 ;
        RECT 31.392 0.000 31.410 0.144 ;
    END
  END ovf_b[73]
  PIN ovf_b[74]
    DIRECTION OUTPUT ;
    USE SIGNAL ;
    PORT
      LAYER M5 ;
        RECT 31.776 0.000 31.800 0.192 ;
    END
  END ovf_b[74]
  PIN ovf_b[75]
    DIRECTION OUTPUT ;
    USE SIGNAL ;
    PORT
      LAYER M3 ;
        RECT 32.148 0.000 32.166 0.144 ;
    END
  END ovf_b[75]
  PIN ovf_b[76]
    DIRECTION OUTPUT ;
    USE SIGNAL ;
    PORT
      LAYER M5 ;
        RECT 32.496 0.000 32.520 0.192 ;
    END
  END ovf_b[76]
  PIN ovf_b[77]
    DIRECTION OUTPUT ;
    USE SIGNAL ;
    PORT
      LAYER M3 ;
        RECT 32.868 0.000 32.886 0.144 ;
    END
  END ovf_b[77]
  PIN ovf_b[78]
    DIRECTION OUTPUT ;
    USE SIGNAL ;
    PORT
      LAYER M5 ;
        RECT 33.216 0.000 33.240 0.192 ;
    END
  END ovf_b[78]
  PIN ovf_b[79]
    DIRECTION OUTPUT ;
    USE SIGNAL ;
    PORT
      LAYER M3 ;
        RECT 33.588 0.000 33.606 0.144 ;
    END
  END ovf_b[79]
  PIN ovf_b[80]
    DIRECTION OUTPUT ;
    USE SIGNAL ;
    PORT
      LAYER M5 ;
        RECT 33.936 0.000 33.960 0.192 ;
    END
  END ovf_b[80]
  PIN ovf_b[81]
    DIRECTION OUTPUT ;
    USE SIGNAL ;
    PORT
      LAYER M3 ;
        RECT 34.308 0.000 34.326 0.144 ;
    END
  END ovf_b[81]
  PIN ovf_b[82]
    DIRECTION OUTPUT ;
    USE SIGNAL ;
    PORT
      LAYER M5 ;
        RECT 34.656 0.000 34.680 0.192 ;
    END
  END ovf_b[82]
  PIN ovf_b[83]
    DIRECTION OUTPUT ;
    USE SIGNAL ;
    PORT
      LAYER M3 ;
        RECT 35.028 0.000 35.046 0.144 ;
    END
  END ovf_b[83]
  PIN ovf_b[84]
    DIRECTION OUTPUT ;
    USE SIGNAL ;
    PORT
      LAYER M5 ;
        RECT 35.424 0.000 35.448 0.192 ;
    END
  END ovf_b[84]
  PIN ovf_b[85]
    DIRECTION OUTPUT ;
    USE SIGNAL ;
    PORT
      LAYER M3 ;
        RECT 35.784 0.000 35.802 0.144 ;
    END
  END ovf_b[85]
  PIN ovf_b[86]
    DIRECTION OUTPUT ;
    USE SIGNAL ;
    PORT
      LAYER M5 ;
        RECT 36.144 0.000 36.168 0.192 ;
    END
  END ovf_b[86]
  PIN ovf_b[87]
    DIRECTION OUTPUT ;
    USE SIGNAL ;
    PORT
      LAYER M3 ;
        RECT 36.504 0.000 36.522 0.144 ;
    END
  END ovf_b[87]
  PIN ovf_b[88]
    DIRECTION OUTPUT ;
    USE SIGNAL ;
    PORT
      LAYER M5 ;
        RECT 36.864 0.000 36.888 0.192 ;
    END
  END ovf_b[88]
  PIN ovf_b[89]
    DIRECTION OUTPUT ;
    USE SIGNAL ;
    PORT
      LAYER M3 ;
        RECT 37.224 0.000 37.242 0.144 ;
    END
  END ovf_b[89]
  PIN ovf_b[90]
    DIRECTION OUTPUT ;
    USE SIGNAL ;
    PORT
      LAYER M5 ;
        RECT 37.584 0.000 37.608 0.192 ;
    END
  END ovf_b[90]
  PIN ovf_b[91]
    DIRECTION OUTPUT ;
    USE SIGNAL ;
    PORT
      LAYER M3 ;
        RECT 37.944 0.000 37.962 0.144 ;
    END
  END ovf_b[91]
  PIN ovf_b[92]
    DIRECTION OUTPUT ;
    USE SIGNAL ;
    PORT
      LAYER M5 ;
        RECT 38.304 0.000 38.328 0.192 ;
    END
  END ovf_b[92]
  PIN ovf_b[93]
    DIRECTION OUTPUT ;
    USE SIGNAL ;
    PORT
      LAYER M3 ;
        RECT 38.664 0.000 38.682 0.144 ;
    END
  END ovf_b[93]
  PIN ovf_b[94]
    DIRECTION OUTPUT ;
    USE SIGNAL ;
    PORT
      LAYER M5 ;
        RECT 39.024 0.000 39.048 0.192 ;
    END
  END ovf_b[94]
  PIN ovf_b[95]
    DIRECTION OUTPUT ;
    USE SIGNAL ;
    PORT
      LAYER M3 ;
        RECT 39.420 0.000 39.438 0.144 ;
    END
  END ovf_b[95]
  PIN ovf_b[96]
    DIRECTION OUTPUT ;
    USE SIGNAL ;
    PORT
      LAYER M5 ;
        RECT 39.744 0.000 39.768 0.192 ;
    END
  END ovf_b[96]
  PIN ovf_b[97]
    DIRECTION OUTPUT ;
    USE SIGNAL ;
    PORT
      LAYER M3 ;
        RECT 40.140 0.000 40.158 0.144 ;
    END
  END ovf_b[97]
  PIN ovf_b[98]
    DIRECTION OUTPUT ;
    USE SIGNAL ;
    PORT
      LAYER M5 ;
        RECT 40.512 0.000 40.536 0.192 ;
    END
  END ovf_b[98]
  PIN ovf_b[99]
    DIRECTION OUTPUT ;
    USE SIGNAL ;
    PORT
      LAYER M3 ;
        RECT 40.860 0.000 40.878 0.144 ;
    END
  END ovf_b[99]
  PIN ovf_b[100]
    DIRECTION OUTPUT ;
    USE SIGNAL ;
    PORT
      LAYER M5 ;
        RECT 41.232 0.000 41.256 0.192 ;
    END
  END ovf_b[100]
  PIN ovf_b[101]
    DIRECTION OUTPUT ;
    USE SIGNAL ;
    PORT
      LAYER M3 ;
        RECT 41.580 0.000 41.598 0.144 ;
    END
  END ovf_b[101]
  PIN ovf_b[102]
    DIRECTION OUTPUT ;
    USE SIGNAL ;
    PORT
      LAYER M5 ;
        RECT 41.952 0.000 41.976 0.192 ;
    END
  END ovf_b[102]
  PIN ovf_b[103]
    DIRECTION OUTPUT ;
    USE SIGNAL ;
    PORT
      LAYER M3 ;
        RECT 42.300 0.000 42.318 0.144 ;
    END
  END ovf_b[103]
  PIN ovf_b[104]
    DIRECTION OUTPUT ;
    USE SIGNAL ;
    PORT
      LAYER M5 ;
        RECT 42.672 0.000 42.696 0.192 ;
    END
  END ovf_b[104]
  PIN ovf_b[105]
    DIRECTION OUTPUT ;
    USE SIGNAL ;
    PORT
      LAYER M3 ;
        RECT 43.056 0.000 43.074 0.144 ;
    END
  END ovf_b[105]
  PIN ovf_b[106]
    DIRECTION OUTPUT ;
    USE SIGNAL ;
    PORT
      LAYER M5 ;
        RECT 43.392 0.000 43.416 0.192 ;
    END
  END ovf_b[106]
  PIN ovf_b[107]
    DIRECTION OUTPUT ;
    USE SIGNAL ;
    PORT
      LAYER M3 ;
        RECT 43.776 0.000 43.794 0.144 ;
    END
  END ovf_b[107]
  PIN ovf_b[108]
    DIRECTION OUTPUT ;
    USE SIGNAL ;
    PORT
      LAYER M5 ;
        RECT 44.112 0.000 44.136 0.192 ;
    END
  END ovf_b[108]
  PIN ovf_b[109]
    DIRECTION OUTPUT ;
    USE SIGNAL ;
    PORT
      LAYER M3 ;
        RECT 44.496 0.000 44.514 0.144 ;
    END
  END ovf_b[109]
  PIN ovf_b[110]
    DIRECTION OUTPUT ;
    USE SIGNAL ;
    PORT
      LAYER M5 ;
        RECT 44.832 0.000 44.856 0.192 ;
    END
  END ovf_b[110]
  PIN ovf_b[111]
    DIRECTION OUTPUT ;
    USE SIGNAL ;
    PORT
      LAYER M3 ;
        RECT 45.216 0.000 45.234 0.144 ;
    END
  END ovf_b[111]
  PIN ovf_b[112]
    DIRECTION OUTPUT ;
    USE SIGNAL ;
    PORT
      LAYER M5 ;
        RECT 45.600 0.000 45.624 0.192 ;
    END
  END ovf_b[112]
  PIN ovf_b[113]
    DIRECTION OUTPUT ;
    USE SIGNAL ;
    PORT
      LAYER M3 ;
        RECT 45.936 0.000 45.954 0.144 ;
    END
  END ovf_b[113]
  PIN ovf_b[114]
    DIRECTION OUTPUT ;
    USE SIGNAL ;
    PORT
      LAYER M5 ;
        RECT 46.320 0.000 46.344 0.192 ;
    END
  END ovf_b[114]
  PIN ovf_b[115]
    DIRECTION OUTPUT ;
    USE SIGNAL ;
    PORT
      LAYER M3 ;
        RECT 46.692 0.000 46.710 0.144 ;
    END
  END ovf_b[115]
  PIN ovf_b[116]
    DIRECTION OUTPUT ;
    USE SIGNAL ;
    PORT
      LAYER M5 ;
        RECT 47.040 0.000 47.064 0.192 ;
    END
  END ovf_b[116]
  PIN ovf_b[117]
    DIRECTION OUTPUT ;
    USE SIGNAL ;
    PORT
      LAYER M3 ;
        RECT 47.412 0.000 47.430 0.144 ;
    END
  END ovf_b[117]
  PIN ovf_b[118]
    DIRECTION OUTPUT ;
    USE SIGNAL ;
    PORT
      LAYER M5 ;
        RECT 47.760 0.000 47.784 0.192 ;
    END
  END ovf_b[118]
  PIN ovf_b[119]
    DIRECTION OUTPUT ;
    USE SIGNAL ;
    PORT
      LAYER M3 ;
        RECT 48.132 0.000 48.150 0.144 ;
    END
  END ovf_b[119]
  PIN ovf_b[120]
    DIRECTION OUTPUT ;
    USE SIGNAL ;
    PORT
      LAYER M5 ;
        RECT 48.480 0.000 48.504 0.192 ;
    END
  END ovf_b[120]
  PIN ovf_b[121]
    DIRECTION OUTPUT ;
    USE SIGNAL ;
    PORT
      LAYER M3 ;
        RECT 48.852 0.000 48.870 0.144 ;
    END
  END ovf_b[121]
  PIN ovf_b[122]
    DIRECTION OUTPUT ;
    USE SIGNAL ;
    PORT
      LAYER M5 ;
        RECT 49.200 0.000 49.224 0.192 ;
    END
  END ovf_b[122]
  PIN ovf_b[123]
    DIRECTION OUTPUT ;
    USE SIGNAL ;
    PORT
      LAYER M3 ;
        RECT 49.572 0.000 49.590 0.144 ;
    END
  END ovf_b[123]
  PIN ovf_b[124]
    DIRECTION OUTPUT ;
    USE SIGNAL ;
    PORT
      LAYER M5 ;
        RECT 49.968 0.000 49.992 0.192 ;
    END
  END ovf_b[124]
  PIN ovf_b[125]
    DIRECTION OUTPUT ;
    USE SIGNAL ;
    PORT
      LAYER M3 ;
        RECT 50.328 0.000 50.346 0.144 ;
    END
  END ovf_b[125]
  PIN ovf_b[126]
    DIRECTION OUTPUT ;
    USE SIGNAL ;
    PORT
      LAYER M5 ;
        RECT 50.688 0.000 50.712 0.192 ;
    END
  END ovf_b[126]
  PIN ovf_b[127]
    DIRECTION OUTPUT ;
    USE SIGNAL ;
    PORT
      LAYER M3 ;
        RECT 51.048 0.000 51.066 0.144 ;
    END
  END ovf_b[127]
  PIN ovf_b[128]
    DIRECTION OUTPUT ;
    USE SIGNAL ;
    PORT
      LAYER M5 ;
        RECT 51.408 0.000 51.432 0.192 ;
    END
  END ovf_b[128]
  PIN ovf_b[129]
    DIRECTION OUTPUT ;
    USE SIGNAL ;
    PORT
      LAYER M3 ;
        RECT 51.768 0.000 51.786 0.144 ;
    END
  END ovf_b[129]
  PIN ovf_b[130]
    DIRECTION OUTPUT ;
    USE SIGNAL ;
    PORT
      LAYER M5 ;
        RECT 52.128 0.000 52.152 0.192 ;
    END
  END ovf_b[130]
  PIN ovf_b[131]
    DIRECTION OUTPUT ;
    USE SIGNAL ;
    PORT
      LAYER M3 ;
        RECT 52.488 0.000 52.506 0.144 ;
    END
  END ovf_b[131]
  PIN ovf_b[132]
    DIRECTION OUTPUT ;
    USE SIGNAL ;
    PORT
      LAYER M5 ;
        RECT 52.848 0.000 52.872 0.192 ;
    END
  END ovf_b[132]
  PIN ovf_b[133]
    DIRECTION OUTPUT ;
    USE SIGNAL ;
    PORT
      LAYER M3 ;
        RECT 53.208 0.000 53.226 0.144 ;
    END
  END ovf_b[133]
  PIN ovf_b[134]
    DIRECTION OUTPUT ;
    USE SIGNAL ;
    PORT
      LAYER M5 ;
        RECT 53.568 0.000 53.592 0.192 ;
    END
  END ovf_b[134]
  PIN ovf_b[135]
    DIRECTION OUTPUT ;
    USE SIGNAL ;
    PORT
      LAYER M3 ;
        RECT 53.964 0.000 53.982 0.144 ;
    END
  END ovf_b[135]
  PIN ovf_b[136]
    DIRECTION OUTPUT ;
    USE SIGNAL ;
    PORT
      LAYER M5 ;
        RECT 54.288 0.000 54.312 0.192 ;
    END
  END ovf_b[136]
  PIN ovf_b[137]
    DIRECTION OUTPUT ;
    USE SIGNAL ;
    PORT
      LAYER M3 ;
        RECT 54.684 0.000 54.702 0.144 ;
    END
  END ovf_b[137]
  PIN ovf_b[138]
    DIRECTION OUTPUT ;
    USE SIGNAL ;
    PORT
      LAYER M5 ;
        RECT 55.056 0.000 55.080 0.192 ;
    END
  END ovf_b[138]
  PIN ovf_b[139]
    DIRECTION OUTPUT ;
    USE SIGNAL ;
    PORT
      LAYER M3 ;
        RECT 55.404 0.000 55.422 0.144 ;
    END
  END ovf_b[139]
  PIN ovf_b[140]
    DIRECTION OUTPUT ;
    USE SIGNAL ;
    PORT
      LAYER M5 ;
        RECT 55.776 0.000 55.800 0.192 ;
    END
  END ovf_b[140]
  PIN ovf_b[141]
    DIRECTION OUTPUT ;
    USE SIGNAL ;
    PORT
      LAYER M3 ;
        RECT 56.124 0.000 56.142 0.144 ;
    END
  END ovf_b[141]
  PIN ovf_b[142]
    DIRECTION OUTPUT ;
    USE SIGNAL ;
    PORT
      LAYER M5 ;
        RECT 56.496 0.000 56.520 0.192 ;
    END
  END ovf_b[142]
  PIN ovf_b[143]
    DIRECTION OUTPUT ;
    USE SIGNAL ;
    PORT
      LAYER M3 ;
        RECT 56.844 0.000 56.862 0.144 ;
    END
  END ovf_b[143]
  PIN ovf_b[144]
    DIRECTION OUTPUT ;
    USE SIGNAL ;
    PORT
      LAYER M5 ;
        RECT 57.216 0.000 57.240 0.192 ;
    END
  END ovf_b[144]
  PIN ovf_b[145]
    DIRECTION OUTPUT ;
    USE SIGNAL ;
    PORT
      LAYER M3 ;
        RECT 57.600 0.000 57.618 0.144 ;
    END
  END ovf_b[145]
  PIN ovf_b[146]
    DIRECTION OUTPUT ;
    USE SIGNAL ;
    PORT
      LAYER M5 ;
        RECT 57.936 0.000 57.960 0.192 ;
    END
  END ovf_b[146]
  PIN ovf_b[147]
    DIRECTION OUTPUT ;
    USE SIGNAL ;
    PORT
      LAYER M3 ;
        RECT 58.320 0.000 58.338 0.144 ;
    END
  END ovf_b[147]
  PIN ovf_b[148]
    DIRECTION OUTPUT ;
    USE SIGNAL ;
    PORT
      LAYER M5 ;
        RECT 58.656 0.000 58.680 0.192 ;
    END
  END ovf_b[148]
  PIN ovf_b[149]
    DIRECTION OUTPUT ;
    USE SIGNAL ;
    PORT
      LAYER M3 ;
        RECT 59.040 0.000 59.058 0.144 ;
    END
  END ovf_b[149]
  PIN ovf_b[150]
    DIRECTION OUTPUT ;
    USE SIGNAL ;
    PORT
      LAYER M5 ;
        RECT 59.424 0.000 59.448 0.192 ;
    END
  END ovf_b[150]
  PIN ovf_b[151]
    DIRECTION OUTPUT ;
    USE SIGNAL ;
    PORT
      LAYER M3 ;
        RECT 59.760 0.000 59.778 0.144 ;
    END
  END ovf_b[151]
  PIN ovf_b[152]
    DIRECTION OUTPUT ;
    USE SIGNAL ;
    PORT
      LAYER M5 ;
        RECT 60.144 0.000 60.168 0.192 ;
    END
  END ovf_b[152]
  PIN ovf_b[153]
    DIRECTION OUTPUT ;
    USE SIGNAL ;
    PORT
      LAYER M3 ;
        RECT 60.480 0.000 60.498 0.144 ;
    END
  END ovf_b[153]
  PIN ovf_b[154]
    DIRECTION OUTPUT ;
    USE SIGNAL ;
    PORT
      LAYER M5 ;
        RECT 60.864 0.000 60.888 0.192 ;
    END
  END ovf_b[154]
  PIN ovf_b[155]
    DIRECTION OUTPUT ;
    USE SIGNAL ;
    PORT
      LAYER M3 ;
        RECT 61.236 0.000 61.254 0.144 ;
    END
  END ovf_b[155]
  PIN ovf_b[156]
    DIRECTION OUTPUT ;
    USE SIGNAL ;
    PORT
      LAYER M5 ;
        RECT 61.584 0.000 61.608 0.192 ;
    END
  END ovf_b[156]
  PIN ovf_b[157]
    DIRECTION OUTPUT ;
    USE SIGNAL ;
    PORT
      LAYER M3 ;
        RECT 61.956 0.000 61.974 0.144 ;
    END
  END ovf_b[157]
  PIN ovf_b[158]
    DIRECTION OUTPUT ;
    USE SIGNAL ;
    PORT
      LAYER M5 ;
        RECT 62.304 0.000 62.328 0.192 ;
    END
  END ovf_b[158]
  PIN ovf_b[159]
    DIRECTION OUTPUT ;
    USE SIGNAL ;
    PORT
      LAYER M3 ;
        RECT 62.676 0.000 62.694 0.144 ;
    END
  END ovf_b[159]
  PIN ovf_b[160]
    DIRECTION OUTPUT ;
    USE SIGNAL ;
    PORT
      LAYER M5 ;
        RECT 63.024 0.000 63.048 0.192 ;
    END
  END ovf_b[160]
  PIN ovf_b[161]
    DIRECTION OUTPUT ;
    USE SIGNAL ;
    PORT
      LAYER M3 ;
        RECT 63.396 0.000 63.414 0.144 ;
    END
  END ovf_b[161]
  PIN ovf_b[162]
    DIRECTION OUTPUT ;
    USE SIGNAL ;
    PORT
      LAYER M5 ;
        RECT 63.744 0.000 63.768 0.192 ;
    END
  END ovf_b[162]
  PIN ovf_b[163]
    DIRECTION OUTPUT ;
    USE SIGNAL ;
    PORT
      LAYER M3 ;
        RECT 64.116 0.000 64.134 0.144 ;
    END
  END ovf_b[163]
  PIN ovf_b[164]
    DIRECTION OUTPUT ;
    USE SIGNAL ;
    PORT
      LAYER M5 ;
        RECT 64.512 0.000 64.536 0.192 ;
    END
  END ovf_b[164]
  PIN ovf_b[165]
    DIRECTION OUTPUT ;
    USE SIGNAL ;
    PORT
      LAYER M3 ;
        RECT 64.872 0.000 64.890 0.144 ;
    END
  END ovf_b[165]
  PIN ovf_b[166]
    DIRECTION OUTPUT ;
    USE SIGNAL ;
    PORT
      LAYER M5 ;
        RECT 65.232 0.000 65.256 0.192 ;
    END
  END ovf_b[166]
  PIN ovf_b[167]
    DIRECTION OUTPUT ;
    USE SIGNAL ;
    PORT
      LAYER M3 ;
        RECT 65.592 0.000 65.610 0.144 ;
    END
  END ovf_b[167]
  PIN ovf_b[168]
    DIRECTION OUTPUT ;
    USE SIGNAL ;
    PORT
      LAYER M5 ;
        RECT 65.952 0.000 65.976 0.192 ;
    END
  END ovf_b[168]
  PIN ovf_b[169]
    DIRECTION OUTPUT ;
    USE SIGNAL ;
    PORT
      LAYER M3 ;
        RECT 66.312 0.000 66.330 0.144 ;
    END
  END ovf_b[169]
  PIN ovf_b[170]
    DIRECTION OUTPUT ;
    USE SIGNAL ;
    PORT
      LAYER M5 ;
        RECT 66.672 0.000 66.696 0.192 ;
    END
  END ovf_b[170]
  PIN ovf_b[171]
    DIRECTION OUTPUT ;
    USE SIGNAL ;
    PORT
      LAYER M3 ;
        RECT 67.032 0.000 67.050 0.144 ;
    END
  END ovf_b[171]
  PIN ovf_b[172]
    DIRECTION OUTPUT ;
    USE SIGNAL ;
    PORT
      LAYER M5 ;
        RECT 67.392 0.000 67.416 0.192 ;
    END
  END ovf_b[172]
  PIN ovf_b[173]
    DIRECTION OUTPUT ;
    USE SIGNAL ;
    PORT
      LAYER M3 ;
        RECT 67.752 0.000 67.770 0.144 ;
    END
  END ovf_b[173]
  PIN ovf_b[174]
    DIRECTION OUTPUT ;
    USE SIGNAL ;
    PORT
      LAYER M5 ;
        RECT 68.112 0.000 68.136 0.192 ;
    END
  END ovf_b[174]
  PIN ovf_b[175]
    DIRECTION OUTPUT ;
    USE SIGNAL ;
    PORT
      LAYER M3 ;
        RECT 68.508 0.000 68.526 0.144 ;
    END
  END ovf_b[175]
  PIN ovf_b[176]
    DIRECTION OUTPUT ;
    USE SIGNAL ;
    PORT
      LAYER M5 ;
        RECT 68.880 0.000 68.904 0.192 ;
    END
  END ovf_b[176]
  PIN ovf_b[177]
    DIRECTION OUTPUT ;
    USE SIGNAL ;
    PORT
      LAYER M3 ;
        RECT 69.228 0.000 69.246 0.144 ;
    END
  END ovf_b[177]
  PIN ovf_b[178]
    DIRECTION OUTPUT ;
    USE SIGNAL ;
    PORT
      LAYER M5 ;
        RECT 69.600 0.000 69.624 0.192 ;
    END
  END ovf_b[178]
  PIN ovf_b[179]
    DIRECTION OUTPUT ;
    USE SIGNAL ;
    PORT
      LAYER M3 ;
        RECT 69.948 0.000 69.966 0.144 ;
    END
  END ovf_b[179]
  PIN ovf_b[180]
    DIRECTION OUTPUT ;
    USE SIGNAL ;
    PORT
      LAYER M5 ;
        RECT 70.320 0.000 70.344 0.192 ;
    END
  END ovf_b[180]
  PIN ovf_b[181]
    DIRECTION OUTPUT ;
    USE SIGNAL ;
    PORT
      LAYER M3 ;
        RECT 70.668 0.000 70.686 0.144 ;
    END
  END ovf_b[181]
  PIN ovf_b[182]
    DIRECTION OUTPUT ;
    USE SIGNAL ;
    PORT
      LAYER M5 ;
        RECT 71.040 0.000 71.064 0.192 ;
    END
  END ovf_b[182]
  PIN ovf_b[183]
    DIRECTION OUTPUT ;
    USE SIGNAL ;
    PORT
      LAYER M3 ;
        RECT 71.388 0.000 71.406 0.144 ;
    END
  END ovf_b[183]
  PIN ovf_b[184]
    DIRECTION OUTPUT ;
    USE SIGNAL ;
    PORT
      LAYER M5 ;
        RECT 71.760 0.000 71.784 0.192 ;
    END
  END ovf_b[184]
  PIN ovf_b[185]
    DIRECTION OUTPUT ;
    USE SIGNAL ;
    PORT
      LAYER M3 ;
        RECT 72.144 0.000 72.162 0.144 ;
    END
  END ovf_b[185]
  PIN ovf_b[186]
    DIRECTION OUTPUT ;
    USE SIGNAL ;
    PORT
      LAYER M5 ;
        RECT 72.480 0.000 72.504 0.192 ;
    END
  END ovf_b[186]
  PIN ovf_b[187]
    DIRECTION OUTPUT ;
    USE SIGNAL ;
    PORT
      LAYER M3 ;
        RECT 72.864 0.000 72.882 0.144 ;
    END
  END ovf_b[187]
  PIN ovf_b[188]
    DIRECTION OUTPUT ;
    USE SIGNAL ;
    PORT
      LAYER M5 ;
        RECT 73.200 0.000 73.224 0.192 ;
    END
  END ovf_b[188]
  PIN ovf_b[189]
    DIRECTION OUTPUT ;
    USE SIGNAL ;
    PORT
      LAYER M3 ;
        RECT 73.584 0.000 73.602 0.144 ;
    END
  END ovf_b[189]
  PIN ovf_b[190]
    DIRECTION OUTPUT ;
    USE SIGNAL ;
    PORT
      LAYER M5 ;
        RECT 73.968 0.000 73.992 0.192 ;
    END
  END ovf_b[190]
  PIN ovf_b[191]
    DIRECTION OUTPUT ;
    USE SIGNAL ;
    PORT
      LAYER M3 ;
        RECT 74.304 0.000 74.322 0.144 ;
    END
  END ovf_b[191]
  PIN ovf_b[192]
    DIRECTION OUTPUT ;
    USE SIGNAL ;
    PORT
      LAYER M5 ;
        RECT 74.688 0.000 74.712 0.192 ;
    END
  END ovf_b[192]
  PIN ovf_b[193]
    DIRECTION OUTPUT ;
    USE SIGNAL ;
    PORT
      LAYER M3 ;
        RECT 75.060 0.000 75.078 0.144 ;
    END
  END ovf_b[193]
  PIN ovf_b[194]
    DIRECTION OUTPUT ;
    USE SIGNAL ;
    PORT
      LAYER M5 ;
        RECT 75.408 0.000 75.432 0.192 ;
    END
  END ovf_b[194]
  PIN ovf_b[195]
    DIRECTION OUTPUT ;
    USE SIGNAL ;
    PORT
      LAYER M3 ;
        RECT 75.780 0.000 75.798 0.144 ;
    END
  END ovf_b[195]
  PIN ovf_b[196]
    DIRECTION OUTPUT ;
    USE SIGNAL ;
    PORT
      LAYER M5 ;
        RECT 76.128 0.000 76.152 0.192 ;
    END
  END ovf_b[196]
  PIN ovf_b[197]
    DIRECTION OUTPUT ;
    USE SIGNAL ;
    PORT
      LAYER M3 ;
        RECT 76.500 0.000 76.518 0.144 ;
    END
  END ovf_b[197]
  PIN ovf_b[198]
    DIRECTION OUTPUT ;
    USE SIGNAL ;
    PORT
      LAYER M5 ;
        RECT 76.848 0.000 76.872 0.192 ;
    END
  END ovf_b[198]
  PIN ovf_b[199]
    DIRECTION OUTPUT ;
    USE SIGNAL ;
    PORT
      LAYER M3 ;
        RECT 77.220 0.000 77.238 0.144 ;
    END
  END ovf_b[199]
  PIN ovf_b[200]
    DIRECTION OUTPUT ;
    USE SIGNAL ;
    PORT
      LAYER M5 ;
        RECT 77.568 0.000 77.592 0.192 ;
    END
  END ovf_b[200]
  PIN ovf_b[201]
    DIRECTION OUTPUT ;
    USE SIGNAL ;
    PORT
      LAYER M3 ;
        RECT 77.940 0.000 77.958 0.144 ;
    END
  END ovf_b[201]
  PIN ovf_b[202]
    DIRECTION OUTPUT ;
    USE SIGNAL ;
    PORT
      LAYER M5 ;
        RECT 78.336 0.000 78.360 0.192 ;
    END
  END ovf_b[202]
  PIN ovf_b[203]
    DIRECTION OUTPUT ;
    USE SIGNAL ;
    PORT
      LAYER M3 ;
        RECT 78.696 0.000 78.714 0.144 ;
    END
  END ovf_b[203]
  PIN ovf_b[204]
    DIRECTION OUTPUT ;
    USE SIGNAL ;
    PORT
      LAYER M5 ;
        RECT 79.056 0.000 79.080 0.192 ;
    END
  END ovf_b[204]
  PIN ovf_b[205]
    DIRECTION OUTPUT ;
    USE SIGNAL ;
    PORT
      LAYER M3 ;
        RECT 79.416 0.000 79.434 0.144 ;
    END
  END ovf_b[205]
  PIN ovf_b[206]
    DIRECTION OUTPUT ;
    USE SIGNAL ;
    PORT
      LAYER M5 ;
        RECT 79.776 0.000 79.800 0.192 ;
    END
  END ovf_b[206]
  PIN ovf_b[207]
    DIRECTION OUTPUT ;
    USE SIGNAL ;
    PORT
      LAYER M3 ;
        RECT 80.136 0.000 80.154 0.144 ;
    END
  END ovf_b[207]
  PIN ovf_b[208]
    DIRECTION OUTPUT ;
    USE SIGNAL ;
    PORT
      LAYER M5 ;
        RECT 80.496 0.000 80.520 0.192 ;
    END
  END ovf_b[208]
  PIN ovf_b[209]
    DIRECTION OUTPUT ;
    USE SIGNAL ;
    PORT
      LAYER M3 ;
        RECT 80.856 0.000 80.874 0.144 ;
    END
  END ovf_b[209]
  PIN ovf_b[210]
    DIRECTION OUTPUT ;
    USE SIGNAL ;
    PORT
      LAYER M5 ;
        RECT 81.216 0.000 81.240 0.192 ;
    END
  END ovf_b[210]
  PIN ovf_b[211]
    DIRECTION OUTPUT ;
    USE SIGNAL ;
    PORT
      LAYER M3 ;
        RECT 81.576 0.000 81.594 0.144 ;
    END
  END ovf_b[211]
  PIN ovf_b[212]
    DIRECTION OUTPUT ;
    USE SIGNAL ;
    PORT
      LAYER M5 ;
        RECT 81.936 0.000 81.960 0.192 ;
    END
  END ovf_b[212]
  PIN ovf_b[213]
    DIRECTION OUTPUT ;
    USE SIGNAL ;
    PORT
      LAYER M3 ;
        RECT 82.332 0.000 82.350 0.144 ;
    END
  END ovf_b[213]
  PIN ovf_b[214]
    DIRECTION OUTPUT ;
    USE SIGNAL ;
    PORT
      LAYER M5 ;
        RECT 82.656 0.000 82.680 0.192 ;
    END
  END ovf_b[214]
  PIN ovf_b[215]
    DIRECTION OUTPUT ;
    USE SIGNAL ;
    PORT
      LAYER M3 ;
        RECT 83.052 0.000 83.070 0.144 ;
    END
  END ovf_b[215]
  PIN ovf_b[216]
    DIRECTION OUTPUT ;
    USE SIGNAL ;
    PORT
      LAYER M5 ;
        RECT 83.424 0.000 83.448 0.192 ;
    END
  END ovf_b[216]
  PIN ovf_b[217]
    DIRECTION OUTPUT ;
    USE SIGNAL ;
    PORT
      LAYER M3 ;
        RECT 83.772 0.000 83.790 0.144 ;
    END
  END ovf_b[217]
  PIN ovf_b[218]
    DIRECTION OUTPUT ;
    USE SIGNAL ;
    PORT
      LAYER M5 ;
        RECT 84.144 0.000 84.168 0.192 ;
    END
  END ovf_b[218]
  PIN ovf_b[219]
    DIRECTION OUTPUT ;
    USE SIGNAL ;
    PORT
      LAYER M3 ;
        RECT 84.492 0.000 84.510 0.144 ;
    END
  END ovf_b[219]
  PIN ovf_b[220]
    DIRECTION OUTPUT ;
    USE SIGNAL ;
    PORT
      LAYER M5 ;
        RECT 84.864 0.000 84.888 0.192 ;
    END
  END ovf_b[220]
  PIN ovf_b[221]
    DIRECTION OUTPUT ;
    USE SIGNAL ;
    PORT
      LAYER M3 ;
        RECT 85.212 0.000 85.230 0.144 ;
    END
  END ovf_b[221]
  PIN ovf_b[222]
    DIRECTION OUTPUT ;
    USE SIGNAL ;
    PORT
      LAYER M5 ;
        RECT 85.584 0.000 85.608 0.192 ;
    END
  END ovf_b[222]
  PIN ovf_b[223]
    DIRECTION OUTPUT ;
    USE SIGNAL ;
    PORT
      LAYER M3 ;
        RECT 85.968 0.000 85.986 0.144 ;
    END
  END ovf_b[223]
  PIN ovf_b[224]
    DIRECTION OUTPUT ;
    USE SIGNAL ;
    PORT
      LAYER M5 ;
        RECT 86.304 0.000 86.328 0.192 ;
    END
  END ovf_b[224]
  PIN ovf_b[225]
    DIRECTION OUTPUT ;
    USE SIGNAL ;
    PORT
      LAYER M3 ;
        RECT 86.688 0.000 86.706 0.144 ;
    END
  END ovf_b[225]
  PIN ovf_b[226]
    DIRECTION OUTPUT ;
    USE SIGNAL ;
    PORT
      LAYER M5 ;
        RECT 87.024 0.000 87.048 0.192 ;
    END
  END ovf_b[226]
  PIN ovf_b[227]
    DIRECTION OUTPUT ;
    USE SIGNAL ;
    PORT
      LAYER M3 ;
        RECT 87.408 0.000 87.426 0.144 ;
    END
  END ovf_b[227]
  PIN ovf_b[228]
    DIRECTION OUTPUT ;
    USE SIGNAL ;
    PORT
      LAYER M5 ;
        RECT 87.744 0.000 87.768 0.192 ;
    END
  END ovf_b[228]
  PIN ovf_b[229]
    DIRECTION OUTPUT ;
    USE SIGNAL ;
    PORT
      LAYER M3 ;
        RECT 88.128 0.000 88.146 0.144 ;
    END
  END ovf_b[229]
  PIN ovf_b[230]
    DIRECTION OUTPUT ;
    USE SIGNAL ;
    PORT
      LAYER M5 ;
        RECT 88.512 0.000 88.536 0.192 ;
    END
  END ovf_b[230]
  PIN ovf_b[231]
    DIRECTION OUTPUT ;
    USE SIGNAL ;
    PORT
      LAYER M3 ;
        RECT 88.848 0.000 88.866 0.144 ;
    END
  END ovf_b[231]
  PIN ovf_b[232]
    DIRECTION OUTPUT ;
    USE SIGNAL ;
    PORT
      LAYER M5 ;
        RECT 89.232 0.000 89.256 0.192 ;
    END
  END ovf_b[232]
  PIN ovf_b[233]
    DIRECTION OUTPUT ;
    USE SIGNAL ;
    PORT
      LAYER M3 ;
        RECT 89.604 0.000 89.622 0.144 ;
    END
  END ovf_b[233]
  PIN ovf_b[234]
    DIRECTION OUTPUT ;
    USE SIGNAL ;
    PORT
      LAYER M5 ;
        RECT 89.952 0.000 89.976 0.192 ;
    END
  END ovf_b[234]
  PIN ovf_b[235]
    DIRECTION OUTPUT ;
    USE SIGNAL ;
    PORT
      LAYER M3 ;
        RECT 90.324 0.000 90.342 0.144 ;
    END
  END ovf_b[235]
  PIN ovf_b[236]
    DIRECTION OUTPUT ;
    USE SIGNAL ;
    PORT
      LAYER M5 ;
        RECT 90.672 0.000 90.696 0.192 ;
    END
  END ovf_b[236]
  PIN ovf_b[237]
    DIRECTION OUTPUT ;
    USE SIGNAL ;
    PORT
      LAYER M3 ;
        RECT 91.044 0.000 91.062 0.144 ;
    END
  END ovf_b[237]
  PIN ovf_b[238]
    DIRECTION OUTPUT ;
    USE SIGNAL ;
    PORT
      LAYER M5 ;
        RECT 91.392 0.000 91.416 0.192 ;
    END
  END ovf_b[238]
  PIN ovf_b[239]
    DIRECTION OUTPUT ;
    USE SIGNAL ;
    PORT
      LAYER M3 ;
        RECT 91.764 0.000 91.782 0.144 ;
    END
  END ovf_b[239]
  PIN ovf_b[240]
    DIRECTION OUTPUT ;
    USE SIGNAL ;
    PORT
      LAYER M5 ;
        RECT 92.112 0.000 92.136 0.192 ;
    END
  END ovf_b[240]
  PIN ovf_b[241]
    DIRECTION OUTPUT ;
    USE SIGNAL ;
    PORT
      LAYER M3 ;
        RECT 92.484 0.000 92.502 0.144 ;
    END
  END ovf_b[241]
  PIN ovf_b[242]
    DIRECTION OUTPUT ;
    USE SIGNAL ;
    PORT
      LAYER M5 ;
        RECT 92.880 0.000 92.904 0.192 ;
    END
  END ovf_b[242]
  PIN ovf_b[243]
    DIRECTION OUTPUT ;
    USE SIGNAL ;
    PORT
      LAYER M3 ;
        RECT 93.240 0.000 93.258 0.144 ;
    END
  END ovf_b[243]
  PIN ovf_b[244]
    DIRECTION OUTPUT ;
    USE SIGNAL ;
    PORT
      LAYER M5 ;
        RECT 93.600 0.000 93.624 0.192 ;
    END
  END ovf_b[244]
  PIN ovf_b[245]
    DIRECTION OUTPUT ;
    USE SIGNAL ;
    PORT
      LAYER M3 ;
        RECT 93.960 0.000 93.978 0.144 ;
    END
  END ovf_b[245]
  PIN ovf_b[246]
    DIRECTION OUTPUT ;
    USE SIGNAL ;
    PORT
      LAYER M5 ;
        RECT 94.320 0.000 94.344 0.192 ;
    END
  END ovf_b[246]
  PIN ovf_b[247]
    DIRECTION OUTPUT ;
    USE SIGNAL ;
    PORT
      LAYER M3 ;
        RECT 94.680 0.000 94.698 0.144 ;
    END
  END ovf_b[247]
  PIN ovf_b[248]
    DIRECTION OUTPUT ;
    USE SIGNAL ;
    PORT
      LAYER M5 ;
        RECT 95.040 0.000 95.064 0.192 ;
    END
  END ovf_b[248]
  PIN ovf_b[249]
    DIRECTION OUTPUT ;
    USE SIGNAL ;
    PORT
      LAYER M3 ;
        RECT 95.400 0.000 95.418 0.144 ;
    END
  END ovf_b[249]
  PIN ovf_b[250]
    DIRECTION OUTPUT ;
    USE SIGNAL ;
    PORT
      LAYER M5 ;
        RECT 95.760 0.000 95.784 0.192 ;
    END
  END ovf_b[250]
  PIN ovf_b[251]
    DIRECTION OUTPUT ;
    USE SIGNAL ;
    PORT
      LAYER M3 ;
        RECT 96.120 0.000 96.138 0.144 ;
    END
  END ovf_b[251]
  PIN ovf_b[252]
    DIRECTION OUTPUT ;
    USE SIGNAL ;
    PORT
      LAYER M5 ;
        RECT 96.480 0.000 96.504 0.192 ;
    END
  END ovf_b[252]
  PIN ovf_b[253]
    DIRECTION OUTPUT ;
    USE SIGNAL ;
    PORT
      LAYER M3 ;
        RECT 96.876 0.000 96.894 0.144 ;
    END
  END ovf_b[253]
  PIN ovf_b[254]
    DIRECTION OUTPUT ;
    USE SIGNAL ;
    PORT
      LAYER M5 ;
        RECT 97.200 0.000 97.224 0.192 ;
    END
  END ovf_b[254]
  PIN ovf_b[255]
    DIRECTION OUTPUT ;
    USE SIGNAL ;
    PORT
      LAYER M3 ;
        RECT 97.596 0.000 97.614 0.144 ;
    END
  END ovf_b[255]
  PIN ovf_b[256]
    DIRECTION OUTPUT ;
    USE SIGNAL ;
    PORT
      LAYER M5 ;
        RECT 97.968 0.000 97.992 0.192 ;
    END
  END ovf_b[256]
  PIN ovf_b[257]
    DIRECTION OUTPUT ;
    USE SIGNAL ;
    PORT
      LAYER M3 ;
        RECT 98.316 0.000 98.334 0.144 ;
    END
  END ovf_b[257]
  PIN ovf_b[258]
    DIRECTION OUTPUT ;
    USE SIGNAL ;
    PORT
      LAYER M5 ;
        RECT 98.688 0.000 98.712 0.192 ;
    END
  END ovf_b[258]
  PIN ovf_b[259]
    DIRECTION OUTPUT ;
    USE SIGNAL ;
    PORT
      LAYER M3 ;
        RECT 99.036 0.000 99.054 0.144 ;
    END
  END ovf_b[259]
  PIN ovf_b[260]
    DIRECTION OUTPUT ;
    USE SIGNAL ;
    PORT
      LAYER M5 ;
        RECT 99.408 0.000 99.432 0.192 ;
    END
  END ovf_b[260]
  PIN ovf_b[261]
    DIRECTION OUTPUT ;
    USE SIGNAL ;
    PORT
      LAYER M3 ;
        RECT 99.756 0.000 99.774 0.144 ;
    END
  END ovf_b[261]
  PIN ovf_b[262]
    DIRECTION OUTPUT ;
    USE SIGNAL ;
    PORT
      LAYER M5 ;
        RECT 100.128 0.000 100.152 0.192 ;
    END
  END ovf_b[262]
  PIN ovf_b[263]
    DIRECTION OUTPUT ;
    USE SIGNAL ;
    PORT
      LAYER M3 ;
        RECT 100.512 0.000 100.530 0.144 ;
    END
  END ovf_b[263]
  PIN ovf_b[264]
    DIRECTION OUTPUT ;
    USE SIGNAL ;
    PORT
      LAYER M5 ;
        RECT 100.848 0.000 100.872 0.192 ;
    END
  END ovf_b[264]
  PIN ovf_b[265]
    DIRECTION OUTPUT ;
    USE SIGNAL ;
    PORT
      LAYER M3 ;
        RECT 101.232 0.000 101.250 0.144 ;
    END
  END ovf_b[265]
  PIN ovf_b[266]
    DIRECTION OUTPUT ;
    USE SIGNAL ;
    PORT
      LAYER M5 ;
        RECT 101.568 0.000 101.592 0.192 ;
    END
  END ovf_b[266]
  PIN ovf_b[267]
    DIRECTION OUTPUT ;
    USE SIGNAL ;
    PORT
      LAYER M3 ;
        RECT 101.952 0.000 101.970 0.144 ;
    END
  END ovf_b[267]
  PIN ovf_b[268]
    DIRECTION OUTPUT ;
    USE SIGNAL ;
    PORT
      LAYER M5 ;
        RECT 102.336 0.000 102.360 0.192 ;
    END
  END ovf_b[268]
  PIN ovf_b[269]
    DIRECTION OUTPUT ;
    USE SIGNAL ;
    PORT
      LAYER M3 ;
        RECT 102.672 0.000 102.690 0.144 ;
    END
  END ovf_b[269]
  PIN ovf_b[270]
    DIRECTION OUTPUT ;
    USE SIGNAL ;
    PORT
      LAYER M5 ;
        RECT 103.056 0.000 103.080 0.192 ;
    END
  END ovf_b[270]
  PIN ovf_b[271]
    DIRECTION OUTPUT ;
    USE SIGNAL ;
    PORT
      LAYER M3 ;
        RECT 103.392 0.000 103.410 0.144 ;
    END
  END ovf_b[271]
  PIN ovf_b[272]
    DIRECTION OUTPUT ;
    USE SIGNAL ;
    PORT
      LAYER M5 ;
        RECT 103.776 0.000 103.800 0.192 ;
    END
  END ovf_b[272]
  PIN ovf_b[273]
    DIRECTION OUTPUT ;
    USE SIGNAL ;
    PORT
      LAYER M3 ;
        RECT 104.148 0.000 104.166 0.144 ;
    END
  END ovf_b[273]
  PIN ovf_b[274]
    DIRECTION OUTPUT ;
    USE SIGNAL ;
    PORT
      LAYER M5 ;
        RECT 104.496 0.000 104.520 0.192 ;
    END
  END ovf_b[274]
  PIN ovf_b[275]
    DIRECTION OUTPUT ;
    USE SIGNAL ;
    PORT
      LAYER M3 ;
        RECT 104.868 0.000 104.886 0.144 ;
    END
  END ovf_b[275]
  PIN ovf_b[276]
    DIRECTION OUTPUT ;
    USE SIGNAL ;
    PORT
      LAYER M5 ;
        RECT 105.216 0.000 105.240 0.192 ;
    END
  END ovf_b[276]
  PIN ovf_b[277]
    DIRECTION OUTPUT ;
    USE SIGNAL ;
    PORT
      LAYER M3 ;
        RECT 105.588 0.000 105.606 0.144 ;
    END
  END ovf_b[277]
  PIN ovf_b[278]
    DIRECTION OUTPUT ;
    USE SIGNAL ;
    PORT
      LAYER M5 ;
        RECT 105.936 0.000 105.960 0.192 ;
    END
  END ovf_b[278]
  PIN ovf_b[279]
    DIRECTION OUTPUT ;
    USE SIGNAL ;
    PORT
      LAYER M3 ;
        RECT 106.308 0.000 106.326 0.144 ;
    END
  END ovf_b[279]
  PIN ovf_b[280]
    DIRECTION OUTPUT ;
    USE SIGNAL ;
    PORT
      LAYER M5 ;
        RECT 106.656 0.000 106.680 0.192 ;
    END
  END ovf_b[280]
  PIN ovf_b[281]
    DIRECTION OUTPUT ;
    USE SIGNAL ;
    PORT
      LAYER M3 ;
        RECT 107.028 0.000 107.046 0.144 ;
    END
  END ovf_b[281]
  PIN ovf_b[282]
    DIRECTION OUTPUT ;
    USE SIGNAL ;
    PORT
      LAYER M5 ;
        RECT 107.424 0.000 107.448 0.192 ;
    END
  END ovf_b[282]
  PIN ovf_b[283]
    DIRECTION OUTPUT ;
    USE SIGNAL ;
    PORT
      LAYER M3 ;
        RECT 107.784 0.000 107.802 0.144 ;
    END
  END ovf_b[283]
  PIN ovf_b[284]
    DIRECTION OUTPUT ;
    USE SIGNAL ;
    PORT
      LAYER M5 ;
        RECT 108.144 0.000 108.168 0.192 ;
    END
  END ovf_b[284]
  PIN ovf_b[285]
    DIRECTION OUTPUT ;
    USE SIGNAL ;
    PORT
      LAYER M3 ;
        RECT 108.504 0.000 108.522 0.144 ;
    END
  END ovf_b[285]
  PIN ovf_b[286]
    DIRECTION OUTPUT ;
    USE SIGNAL ;
    PORT
      LAYER M5 ;
        RECT 108.864 0.000 108.888 0.192 ;
    END
  END ovf_b[286]
  PIN ovf_b[287]
    DIRECTION OUTPUT ;
    USE SIGNAL ;
    PORT
      LAYER M3 ;
        RECT 109.224 0.000 109.242 0.144 ;
    END
  END ovf_b[287]
  PIN ovf_b[288]
    DIRECTION OUTPUT ;
    USE SIGNAL ;
    PORT
      LAYER M5 ;
        RECT 109.584 0.000 109.608 0.192 ;
    END
  END ovf_b[288]
  PIN ovf_b[289]
    DIRECTION OUTPUT ;
    USE SIGNAL ;
    PORT
      LAYER M3 ;
        RECT 109.944 0.000 109.962 0.144 ;
    END
  END ovf_b[289]
  PIN ovf_b[290]
    DIRECTION OUTPUT ;
    USE SIGNAL ;
    PORT
      LAYER M5 ;
        RECT 110.304 0.000 110.328 0.192 ;
    END
  END ovf_b[290]
  PIN ovf_b[291]
    DIRECTION OUTPUT ;
    USE SIGNAL ;
    PORT
      LAYER M3 ;
        RECT 110.664 0.000 110.682 0.144 ;
    END
  END ovf_b[291]
  PIN ovf_b[292]
    DIRECTION OUTPUT ;
    USE SIGNAL ;
    PORT
      LAYER M5 ;
        RECT 111.024 0.000 111.048 0.192 ;
    END
  END ovf_b[292]
  PIN ovf_b[293]
    DIRECTION OUTPUT ;
    USE SIGNAL ;
    PORT
      LAYER M3 ;
        RECT 111.420 0.000 111.438 0.144 ;
    END
  END ovf_b[293]
  PIN ovf_b[294]
    DIRECTION OUTPUT ;
    USE SIGNAL ;
    PORT
      LAYER M5 ;
        RECT 111.792 0.000 111.816 0.192 ;
    END
  END ovf_b[294]
  PIN ovf_b[295]
    DIRECTION OUTPUT ;
    USE SIGNAL ;
    PORT
      LAYER M3 ;
        RECT 112.140 0.000 112.158 0.144 ;
    END
  END ovf_b[295]
  PIN ovf_b[296]
    DIRECTION OUTPUT ;
    USE SIGNAL ;
    PORT
      LAYER M5 ;
        RECT 112.512 0.000 112.536 0.192 ;
    END
  END ovf_b[296]
  PIN ovf_b[297]
    DIRECTION OUTPUT ;
    USE SIGNAL ;
    PORT
      LAYER M3 ;
        RECT 112.860 0.000 112.878 0.144 ;
    END
  END ovf_b[297]
  PIN ovf_b[298]
    DIRECTION OUTPUT ;
    USE SIGNAL ;
    PORT
      LAYER M5 ;
        RECT 113.232 0.000 113.256 0.192 ;
    END
  END ovf_b[298]
  PIN ovf_b[299]
    DIRECTION OUTPUT ;
    USE SIGNAL ;
    PORT
      LAYER M3 ;
        RECT 113.580 0.000 113.598 0.144 ;
    END
  END ovf_b[299]
  PIN ovf_b[300]
    DIRECTION OUTPUT ;
    USE SIGNAL ;
    PORT
      LAYER M5 ;
        RECT 113.952 0.000 113.976 0.192 ;
    END
  END ovf_b[300]
  PIN ovf_b[301]
    DIRECTION OUTPUT ;
    USE SIGNAL ;
    PORT
      LAYER M3 ;
        RECT 114.300 0.000 114.318 0.144 ;
    END
  END ovf_b[301]
  PIN ovf_b[302]
    DIRECTION OUTPUT ;
    USE SIGNAL ;
    PORT
      LAYER M5 ;
        RECT 114.672 0.000 114.696 0.192 ;
    END
  END ovf_b[302]
  PIN ovf_b[303]
    DIRECTION OUTPUT ;
    USE SIGNAL ;
    PORT
      LAYER M3 ;
        RECT 115.056 0.000 115.074 0.144 ;
    END
  END ovf_b[303]
  PIN ovf_b[304]
    DIRECTION OUTPUT ;
    USE SIGNAL ;
    PORT
      LAYER M5 ;
        RECT 115.392 0.000 115.416 0.192 ;
    END
  END ovf_b[304]
  PIN ovf_b[305]
    DIRECTION OUTPUT ;
    USE SIGNAL ;
    PORT
      LAYER M3 ;
        RECT 115.776 0.000 115.794 0.144 ;
    END
  END ovf_b[305]
  PIN ovf_b[306]
    DIRECTION OUTPUT ;
    USE SIGNAL ;
    PORT
      LAYER M5 ;
        RECT 116.112 0.000 116.136 0.192 ;
    END
  END ovf_b[306]
  PIN ovf_b[307]
    DIRECTION OUTPUT ;
    USE SIGNAL ;
    PORT
      LAYER M3 ;
        RECT 116.496 0.000 116.514 0.144 ;
    END
  END ovf_b[307]
  PIN ovf_b[308]
    DIRECTION OUTPUT ;
    USE SIGNAL ;
    PORT
      LAYER M5 ;
        RECT 116.880 0.000 116.904 0.192 ;
    END
  END ovf_b[308]
  PIN ovf_b[309]
    DIRECTION OUTPUT ;
    USE SIGNAL ;
    PORT
      LAYER M3 ;
        RECT 117.216 0.000 117.234 0.144 ;
    END
  END ovf_b[309]
  PIN ovf_b[310]
    DIRECTION OUTPUT ;
    USE SIGNAL ;
    PORT
      LAYER M5 ;
        RECT 117.600 0.000 117.624 0.192 ;
    END
  END ovf_b[310]
  PIN ovf_b[311]
    DIRECTION OUTPUT ;
    USE SIGNAL ;
    PORT
      LAYER M3 ;
        RECT 117.936 0.000 117.954 0.144 ;
    END
  END ovf_b[311]
  PIN ovf_b[312]
    DIRECTION OUTPUT ;
    USE SIGNAL ;
    PORT
      LAYER M5 ;
        RECT 118.320 0.000 118.344 0.192 ;
    END
  END ovf_b[312]
  PIN ovf_b[313]
    DIRECTION OUTPUT ;
    USE SIGNAL ;
    PORT
      LAYER M3 ;
        RECT 118.692 0.000 118.710 0.144 ;
    END
  END ovf_b[313]
  PIN ovf_b[314]
    DIRECTION OUTPUT ;
    USE SIGNAL ;
    PORT
      LAYER M5 ;
        RECT 119.040 0.000 119.064 0.192 ;
    END
  END ovf_b[314]
  PIN ovf_b[315]
    DIRECTION OUTPUT ;
    USE SIGNAL ;
    PORT
      LAYER M3 ;
        RECT 119.412 0.000 119.430 0.144 ;
    END
  END ovf_b[315]
  PIN ovf_b[316]
    DIRECTION OUTPUT ;
    USE SIGNAL ;
    PORT
      LAYER M5 ;
        RECT 119.760 0.000 119.784 0.192 ;
    END
  END ovf_b[316]
  PIN ovf_b[317]
    DIRECTION OUTPUT ;
    USE SIGNAL ;
    PORT
      LAYER M3 ;
        RECT 120.132 0.000 120.150 0.144 ;
    END
  END ovf_b[317]
  PIN ovf_b[318]
    DIRECTION OUTPUT ;
    USE SIGNAL ;
    PORT
      LAYER M5 ;
        RECT 120.480 0.000 120.504 0.192 ;
    END
  END ovf_b[318]
  PIN ovf_b[319]
    DIRECTION OUTPUT ;
    USE SIGNAL ;
    PORT
      LAYER M3 ;
        RECT 120.852 0.000 120.870 0.144 ;
    END
  END ovf_b[319]
  PIN ovf_b[320]
    DIRECTION OUTPUT ;
    USE SIGNAL ;
    PORT
      LAYER M5 ;
        RECT 121.200 0.000 121.224 0.192 ;
    END
  END ovf_b[320]
  PIN ovf_b[321]
    DIRECTION OUTPUT ;
    USE SIGNAL ;
    PORT
      LAYER M3 ;
        RECT 121.608 0.000 121.626 0.144 ;
    END
  END ovf_b[321]
  PIN ovf_b[322]
    DIRECTION OUTPUT ;
    USE SIGNAL ;
    PORT
      LAYER M5 ;
        RECT 121.968 0.000 121.992 0.192 ;
    END
  END ovf_b[322]
  PIN ovf_b[323]
    DIRECTION OUTPUT ;
    USE SIGNAL ;
    PORT
      LAYER M3 ;
        RECT 122.328 0.000 122.346 0.144 ;
    END
  END ovf_b[323]
  PIN ovf_b[324]
    DIRECTION OUTPUT ;
    USE SIGNAL ;
    PORT
      LAYER M5 ;
        RECT 122.688 0.000 122.712 0.192 ;
    END
  END ovf_b[324]
  PIN ovf_b[325]
    DIRECTION OUTPUT ;
    USE SIGNAL ;
    PORT
      LAYER M3 ;
        RECT 123.048 0.000 123.066 0.144 ;
    END
  END ovf_b[325]
  PIN ovf_b[326]
    DIRECTION OUTPUT ;
    USE SIGNAL ;
    PORT
      LAYER M5 ;
        RECT 123.408 0.000 123.432 0.192 ;
    END
  END ovf_b[326]
  PIN ovf_b[327]
    DIRECTION OUTPUT ;
    USE SIGNAL ;
    PORT
      LAYER M3 ;
        RECT 123.768 0.000 123.786 0.144 ;
    END
  END ovf_b[327]
  PIN ovf_b[328]
    DIRECTION OUTPUT ;
    USE SIGNAL ;
    PORT
      LAYER M5 ;
        RECT 124.128 0.000 124.152 0.192 ;
    END
  END ovf_b[328]
  PIN ovf_b[329]
    DIRECTION OUTPUT ;
    USE SIGNAL ;
    PORT
      LAYER M3 ;
        RECT 124.488 0.000 124.506 0.144 ;
    END
  END ovf_b[329]
  PIN ovf_b[330]
    DIRECTION OUTPUT ;
    USE SIGNAL ;
    PORT
      LAYER M5 ;
        RECT 124.848 0.000 124.872 0.192 ;
    END
  END ovf_b[330]
  PIN ovf_b[331]
    DIRECTION OUTPUT ;
    USE SIGNAL ;
    PORT
      LAYER M3 ;
        RECT 125.244 0.000 125.262 0.144 ;
    END
  END ovf_b[331]
  PIN ovf_b[332]
    DIRECTION OUTPUT ;
    USE SIGNAL ;
    PORT
      LAYER M5 ;
        RECT 125.568 0.000 125.592 0.192 ;
    END
  END ovf_b[332]
  PIN ovf_b[333]
    DIRECTION OUTPUT ;
    USE SIGNAL ;
    PORT
      LAYER M3 ;
        RECT 125.964 0.000 125.982 0.144 ;
    END
  END ovf_b[333]
  PIN ovf_b[334]
    DIRECTION OUTPUT ;
    USE SIGNAL ;
    PORT
      LAYER M5 ;
        RECT 126.336 0.000 126.360 0.192 ;
    END
  END ovf_b[334]
  PIN ovf_b[335]
    DIRECTION OUTPUT ;
    USE SIGNAL ;
    PORT
      LAYER M3 ;
        RECT 126.684 0.000 126.702 0.144 ;
    END
  END ovf_b[335]
  PIN ovf_b[336]
    DIRECTION OUTPUT ;
    USE SIGNAL ;
    PORT
      LAYER M5 ;
        RECT 127.056 0.000 127.080 0.192 ;
    END
  END ovf_b[336]
  PIN ovf_b[337]
    DIRECTION OUTPUT ;
    USE SIGNAL ;
    PORT
      LAYER M3 ;
        RECT 127.404 0.000 127.422 0.144 ;
    END
  END ovf_b[337]
  PIN ovf_b[338]
    DIRECTION OUTPUT ;
    USE SIGNAL ;
    PORT
      LAYER M5 ;
        RECT 127.776 0.000 127.800 0.192 ;
    END
  END ovf_b[338]
  PIN ovf_b[339]
    DIRECTION OUTPUT ;
    USE SIGNAL ;
    PORT
      LAYER M3 ;
        RECT 128.124 0.000 128.142 0.144 ;
    END
  END ovf_b[339]
  PIN ovf_b[340]
    DIRECTION OUTPUT ;
    USE SIGNAL ;
    PORT
      LAYER M5 ;
        RECT 128.496 0.000 128.520 0.192 ;
    END
  END ovf_b[340]
  PIN ovf_b[341]
    DIRECTION OUTPUT ;
    USE SIGNAL ;
    PORT
      LAYER M3 ;
        RECT 128.880 0.000 128.898 0.144 ;
    END
  END ovf_b[341]
  PIN ovf_b[342]
    DIRECTION OUTPUT ;
    USE SIGNAL ;
    PORT
      LAYER M5 ;
        RECT 129.216 0.000 129.240 0.192 ;
    END
  END ovf_b[342]
  PIN ovf_b[343]
    DIRECTION OUTPUT ;
    USE SIGNAL ;
    PORT
      LAYER M3 ;
        RECT 129.600 0.000 129.618 0.144 ;
    END
  END ovf_b[343]
  PIN up_in[0]
    DIRECTION INPUT ;
    USE SIGNAL ;
    PORT
      LAYER M5 ;
        RECT 129.936 0.000 129.960 0.192 ;
    END
  END up_in[0]
  PIN up_in[1]
    DIRECTION INPUT ;
    USE SIGNAL ;
    PORT
      LAYER M3 ;
        RECT 130.320 0.000 130.338 0.144 ;
    END
  END up_in[1]
  PIN up_in[2]
    DIRECTION INPUT ;
    USE SIGNAL ;
    PORT
      LAYER M5 ;
        RECT 130.656 0.000 130.680 0.192 ;
    END
  END up_in[2]
  PIN up_in[3]
    DIRECTION INPUT ;
    USE SIGNAL ;
    PORT
      LAYER M3 ;
        RECT 131.040 0.000 131.058 0.144 ;
    END
  END up_in[3]
  PIN up_in[4]
    DIRECTION INPUT ;
    USE SIGNAL ;
    PORT
      LAYER M5 ;
        RECT 131.424 0.000 131.448 0.192 ;
    END
  END up_in[4]
  PIN up_in[5]
    DIRECTION INPUT ;
    USE SIGNAL ;
    PORT
      LAYER M3 ;
        RECT 131.760 0.000 131.778 0.144 ;
    END
  END up_in[5]
  PIN up_in[6]
    DIRECTION INPUT ;
    USE SIGNAL ;
    PORT
      LAYER M5 ;
        RECT 132.144 0.000 132.168 0.192 ;
    END
  END up_in[6]
  PIN up_in[7]
    DIRECTION INPUT ;
    USE SIGNAL ;
    PORT
      LAYER M3 ;
        RECT 132.516 0.000 132.534 0.144 ;
    END
  END up_in[7]
  PIN up_in[8]
    DIRECTION INPUT ;
    USE SIGNAL ;
    PORT
      LAYER M5 ;
        RECT 132.864 0.000 132.888 0.192 ;
    END
  END up_in[8]
  PIN up_in[9]
    DIRECTION INPUT ;
    USE SIGNAL ;
    PORT
      LAYER M3 ;
        RECT 133.236 0.000 133.254 0.144 ;
    END
  END up_in[9]
  PIN up_in[10]
    DIRECTION INPUT ;
    USE SIGNAL ;
    PORT
      LAYER M5 ;
        RECT 133.584 0.000 133.608 0.192 ;
    END
  END up_in[10]
  PIN up_in[11]
    DIRECTION INPUT ;
    USE SIGNAL ;
    PORT
      LAYER M3 ;
        RECT 133.956 0.000 133.974 0.144 ;
    END
  END up_in[11]
  PIN up_in[12]
    DIRECTION INPUT ;
    USE SIGNAL ;
    PORT
      LAYER M5 ;
        RECT 134.304 0.000 134.328 0.192 ;
    END
  END up_in[12]
  PIN up_in[13]
    DIRECTION INPUT ;
    USE SIGNAL ;
    PORT
      LAYER M3 ;
        RECT 134.676 0.000 134.694 0.144 ;
    END
  END up_in[13]
  PIN up_in[14]
    DIRECTION INPUT ;
    USE SIGNAL ;
    PORT
      LAYER M5 ;
        RECT 135.024 0.000 135.048 0.192 ;
    END
  END up_in[14]
  PIN up_in[15]
    DIRECTION INPUT ;
    USE SIGNAL ;
    PORT
      LAYER M3 ;
        RECT 135.396 0.000 135.414 0.144 ;
    END
  END up_in[15]
  PIN up_in[16]
    DIRECTION INPUT ;
    USE SIGNAL ;
    PORT
      LAYER M5 ;
        RECT 135.792 0.000 135.816 0.192 ;
    END
  END up_in[16]
  PIN up_in[17]
    DIRECTION INPUT ;
    USE SIGNAL ;
    PORT
      LAYER M3 ;
        RECT 136.152 0.000 136.170 0.144 ;
    END
  END up_in[17]
  PIN up_in[18]
    DIRECTION INPUT ;
    USE SIGNAL ;
    PORT
      LAYER M5 ;
        RECT 136.512 0.000 136.536 0.192 ;
    END
  END up_in[18]
  PIN up_in[19]
    DIRECTION INPUT ;
    USE SIGNAL ;
    PORT
      LAYER M3 ;
        RECT 136.872 0.000 136.890 0.144 ;
    END
  END up_in[19]
  PIN up_in[20]
    DIRECTION INPUT ;
    USE SIGNAL ;
    PORT
      LAYER M5 ;
        RECT 137.232 0.000 137.256 0.192 ;
    END
  END up_in[20]
  PIN up_in[21]
    DIRECTION INPUT ;
    USE SIGNAL ;
    PORT
      LAYER M3 ;
        RECT 137.592 0.000 137.610 0.144 ;
    END
  END up_in[21]
  PIN up_in[22]
    DIRECTION INPUT ;
    USE SIGNAL ;
    PORT
      LAYER M5 ;
        RECT 137.952 0.000 137.976 0.192 ;
    END
  END up_in[22]
  PIN up_in[23]
    DIRECTION INPUT ;
    USE SIGNAL ;
    PORT
      LAYER M3 ;
        RECT 138.312 0.000 138.330 0.144 ;
    END
  END up_in[23]
  PIN up_in[24]
    DIRECTION INPUT ;
    USE SIGNAL ;
    PORT
      LAYER M5 ;
        RECT 138.672 0.000 138.696 0.192 ;
    END
  END up_in[24]
  PIN up_in[25]
    DIRECTION INPUT ;
    USE SIGNAL ;
    PORT
      LAYER M3 ;
        RECT 139.032 0.000 139.050 0.144 ;
    END
  END up_in[25]
  PIN up_in[26]
    DIRECTION INPUT ;
    USE SIGNAL ;
    PORT
      LAYER M5 ;
        RECT 139.392 0.000 139.416 0.192 ;
    END
  END up_in[26]
  PIN up_in[27]
    DIRECTION INPUT ;
    USE SIGNAL ;
    PORT
      LAYER M3 ;
        RECT 139.788 0.000 139.806 0.144 ;
    END
  END up_in[27]
  PIN up_in[28]
    DIRECTION INPUT ;
    USE SIGNAL ;
    PORT
      LAYER M5 ;
        RECT 140.112 0.000 140.136 0.192 ;
    END
  END up_in[28]
  PIN up_in[29]
    DIRECTION INPUT ;
    USE SIGNAL ;
    PORT
      LAYER M3 ;
        RECT 140.508 0.000 140.526 0.144 ;
    END
  END up_in[29]
  PIN up_in[30]
    DIRECTION INPUT ;
    USE SIGNAL ;
    PORT
      LAYER M5 ;
        RECT 140.880 0.000 140.904 0.192 ;
    END
  END up_in[30]
  PIN up_in[31]
    DIRECTION INPUT ;
    USE SIGNAL ;
    PORT
      LAYER M3 ;
        RECT 141.228 0.000 141.246 0.144 ;
    END
  END up_in[31]
  PIN up_in[32]
    DIRECTION INPUT ;
    USE SIGNAL ;
    PORT
      LAYER M5 ;
        RECT 141.600 0.000 141.624 0.192 ;
    END
  END up_in[32]
  PIN up_in[33]
    DIRECTION INPUT ;
    USE SIGNAL ;
    PORT
      LAYER M3 ;
        RECT 141.948 0.000 141.966 0.144 ;
    END
  END up_in[33]
  PIN up_in[34]
    DIRECTION INPUT ;
    USE SIGNAL ;
    PORT
      LAYER M5 ;
        RECT 142.320 0.000 142.344 0.192 ;
    END
  END up_in[34]
  PIN up_in[35]
    DIRECTION INPUT ;
    USE SIGNAL ;
    PORT
      LAYER M3 ;
        RECT 142.668 0.000 142.686 0.144 ;
    END
  END up_in[35]
  PIN up_in[36]
    DIRECTION INPUT ;
    USE SIGNAL ;
    PORT
      LAYER M5 ;
        RECT 143.040 0.000 143.064 0.192 ;
    END
  END up_in[36]
  PIN up_in[37]
    DIRECTION INPUT ;
    USE SIGNAL ;
    PORT
      LAYER M3 ;
        RECT 143.424 0.000 143.442 0.144 ;
    END
  END up_in[37]
  PIN up_in[38]
    DIRECTION INPUT ;
    USE SIGNAL ;
    PORT
      LAYER M5 ;
        RECT 143.760 0.000 143.784 0.192 ;
    END
  END up_in[38]
  PIN up_in[39]
    DIRECTION INPUT ;
    USE SIGNAL ;
    PORT
      LAYER M3 ;
        RECT 144.144 0.000 144.162 0.144 ;
    END
  END up_in[39]
  PIN up_in[40]
    DIRECTION INPUT ;
    USE SIGNAL ;
    PORT
      LAYER M5 ;
        RECT 144.480 0.000 144.504 0.192 ;
    END
  END up_in[40]
  PIN up_in[41]
    DIRECTION INPUT ;
    USE SIGNAL ;
    PORT
      LAYER M3 ;
        RECT 144.864 0.000 144.882 0.144 ;
    END
  END up_in[41]
  PIN up_in[42]
    DIRECTION INPUT ;
    USE SIGNAL ;
    PORT
      LAYER M5 ;
        RECT 145.248 0.000 145.272 0.192 ;
    END
  END up_in[42]
  PIN up_in[43]
    DIRECTION INPUT ;
    USE SIGNAL ;
    PORT
      LAYER M3 ;
        RECT 145.584 0.000 145.602 0.144 ;
    END
  END up_in[43]
  PIN up_in[44]
    DIRECTION INPUT ;
    USE SIGNAL ;
    PORT
      LAYER M5 ;
        RECT 145.968 0.000 145.992 0.192 ;
    END
  END up_in[44]
  PIN up_in[45]
    DIRECTION INPUT ;
    USE SIGNAL ;
    PORT
      LAYER M3 ;
        RECT 146.304 0.000 146.322 0.144 ;
    END
  END up_in[45]
  PIN up_in[46]
    DIRECTION INPUT ;
    USE SIGNAL ;
    PORT
      LAYER M5 ;
        RECT 146.688 0.000 146.712 0.192 ;
    END
  END up_in[46]
  PIN up_in[47]
    DIRECTION INPUT ;
    USE SIGNAL ;
    PORT
      LAYER M3 ;
        RECT 147.060 0.000 147.078 0.144 ;
    END
  END up_in[47]
  PIN up_in[48]
    DIRECTION INPUT ;
    USE SIGNAL ;
    PORT
      LAYER M5 ;
        RECT 147.408 0.000 147.432 0.192 ;
    END
  END up_in[48]
  PIN up_in[49]
    DIRECTION INPUT ;
    USE SIGNAL ;
    PORT
      LAYER M3 ;
        RECT 147.780 0.000 147.798 0.144 ;
    END
  END up_in[49]
  PIN up_in[50]
    DIRECTION INPUT ;
    USE SIGNAL ;
    PORT
      LAYER M5 ;
        RECT 148.128 0.000 148.152 0.192 ;
    END
  END up_in[50]
  PIN up_in[51]
    DIRECTION INPUT ;
    USE SIGNAL ;
    PORT
      LAYER M3 ;
        RECT 148.500 0.000 148.518 0.144 ;
    END
  END up_in[51]
  PIN up_in[52]
    DIRECTION INPUT ;
    USE SIGNAL ;
    PORT
      LAYER M5 ;
        RECT 148.848 0.000 148.872 0.192 ;
    END
  END up_in[52]
  PIN up_in[53]
    DIRECTION INPUT ;
    USE SIGNAL ;
    PORT
      LAYER M3 ;
        RECT 149.220 0.000 149.238 0.144 ;
    END
  END up_in[53]
  PIN up_in[54]
    DIRECTION INPUT ;
    USE SIGNAL ;
    PORT
      LAYER M5 ;
        RECT 149.568 0.000 149.592 0.192 ;
    END
  END up_in[54]
  PIN up_in[55]
    DIRECTION INPUT ;
    USE SIGNAL ;
    PORT
      LAYER M3 ;
        RECT 149.940 0.000 149.958 0.144 ;
    END
  END up_in[55]
  PIN up_in[56]
    DIRECTION INPUT ;
    USE SIGNAL ;
    PORT
      LAYER M5 ;
        RECT 150.336 0.000 150.360 0.192 ;
    END
  END up_in[56]
  PIN up_in[57]
    DIRECTION INPUT ;
    USE SIGNAL ;
    PORT
      LAYER M3 ;
        RECT 150.696 0.000 150.714 0.144 ;
    END
  END up_in[57]
  PIN up_in[58]
    DIRECTION INPUT ;
    USE SIGNAL ;
    PORT
      LAYER M5 ;
        RECT 151.056 0.000 151.080 0.192 ;
    END
  END up_in[58]
  PIN up_in[59]
    DIRECTION INPUT ;
    USE SIGNAL ;
    PORT
      LAYER M3 ;
        RECT 151.416 0.000 151.434 0.144 ;
    END
  END up_in[59]
  PIN up_in[60]
    DIRECTION INPUT ;
    USE SIGNAL ;
    PORT
      LAYER M5 ;
        RECT 151.776 0.000 151.800 0.192 ;
    END
  END up_in[60]
  PIN up_in[61]
    DIRECTION INPUT ;
    USE SIGNAL ;
    PORT
      LAYER M3 ;
        RECT 152.136 0.000 152.154 0.144 ;
    END
  END up_in[61]
  PIN up_in[62]
    DIRECTION INPUT ;
    USE SIGNAL ;
    PORT
      LAYER M5 ;
        RECT 152.496 0.000 152.520 0.192 ;
    END
  END up_in[62]
  PIN up_in[63]
    DIRECTION INPUT ;
    USE SIGNAL ;
    PORT
      LAYER M3 ;
        RECT 152.856 0.000 152.874 0.144 ;
    END
  END up_in[63]
  PIN up_in[64]
    DIRECTION INPUT ;
    USE SIGNAL ;
    PORT
      LAYER M5 ;
        RECT 153.216 0.000 153.240 0.192 ;
    END
  END up_in[64]
  PIN up_in[65]
    DIRECTION INPUT ;
    USE SIGNAL ;
    PORT
      LAYER M3 ;
        RECT 153.576 0.000 153.594 0.144 ;
    END
  END up_in[65]
  PIN up_in[66]
    DIRECTION INPUT ;
    USE SIGNAL ;
    PORT
      LAYER M5 ;
        RECT 153.936 0.000 153.960 0.192 ;
    END
  END up_in[66]
  PIN up_in[67]
    DIRECTION INPUT ;
    USE SIGNAL ;
    PORT
      LAYER M3 ;
        RECT 154.332 0.000 154.350 0.144 ;
    END
  END up_in[67]
  PIN up_in[68]
    DIRECTION INPUT ;
    USE SIGNAL ;
    PORT
      LAYER M5 ;
        RECT 154.704 0.000 154.728 0.192 ;
    END
  END up_in[68]
  PIN up_in[69]
    DIRECTION INPUT ;
    USE SIGNAL ;
    PORT
      LAYER M3 ;
        RECT 155.052 0.000 155.070 0.144 ;
    END
  END up_in[69]
  PIN up_in[70]
    DIRECTION INPUT ;
    USE SIGNAL ;
    PORT
      LAYER M5 ;
        RECT 155.424 0.000 155.448 0.192 ;
    END
  END up_in[70]
  PIN up_in[71]
    DIRECTION INPUT ;
    USE SIGNAL ;
    PORT
      LAYER M3 ;
        RECT 155.772 0.000 155.790 0.144 ;
    END
  END up_in[71]
  PIN up_in[72]
    DIRECTION INPUT ;
    USE SIGNAL ;
    PORT
      LAYER M5 ;
        RECT 156.144 0.000 156.168 0.192 ;
    END
  END up_in[72]
  PIN up_in[73]
    DIRECTION INPUT ;
    USE SIGNAL ;
    PORT
      LAYER M3 ;
        RECT 156.492 0.000 156.510 0.144 ;
    END
  END up_in[73]
  PIN up_in[74]
    DIRECTION INPUT ;
    USE SIGNAL ;
    PORT
      LAYER M5 ;
        RECT 156.864 0.000 156.888 0.192 ;
    END
  END up_in[74]
  PIN up_in[75]
    DIRECTION INPUT ;
    USE SIGNAL ;
    PORT
      LAYER M3 ;
        RECT 157.212 0.000 157.230 0.144 ;
    END
  END up_in[75]
  PIN up_in[76]
    DIRECTION INPUT ;
    USE SIGNAL ;
    PORT
      LAYER M5 ;
        RECT 157.584 0.000 157.608 0.192 ;
    END
  END up_in[76]
  PIN up_in[77]
    DIRECTION INPUT ;
    USE SIGNAL ;
    PORT
      LAYER M3 ;
        RECT 157.968 0.000 157.986 0.144 ;
    END
  END up_in[77]
  PIN up_in[78]
    DIRECTION INPUT ;
    USE SIGNAL ;
    PORT
      LAYER M5 ;
        RECT 158.304 0.000 158.328 0.192 ;
    END
  END up_in[78]
  PIN up_in[79]
    DIRECTION INPUT ;
    USE SIGNAL ;
    PORT
      LAYER M3 ;
        RECT 158.688 0.000 158.706 0.144 ;
    END
  END up_in[79]
  PIN up_in[80]
    DIRECTION INPUT ;
    USE SIGNAL ;
    PORT
      LAYER M5 ;
        RECT 159.024 0.000 159.048 0.192 ;
    END
  END up_in[80]
  PIN up_in[81]
    DIRECTION INPUT ;
    USE SIGNAL ;
    PORT
      LAYER M3 ;
        RECT 159.408 0.000 159.426 0.144 ;
    END
  END up_in[81]
  PIN up_in[82]
    DIRECTION INPUT ;
    USE SIGNAL ;
    PORT
      LAYER M5 ;
        RECT 159.792 0.000 159.816 0.192 ;
    END
  END up_in[82]
  PIN up_in[83]
    DIRECTION INPUT ;
    USE SIGNAL ;
    PORT
      LAYER M3 ;
        RECT 160.128 0.000 160.146 0.144 ;
    END
  END up_in[83]
  PIN up_in[84]
    DIRECTION INPUT ;
    USE SIGNAL ;
    PORT
      LAYER M5 ;
        RECT 160.512 0.000 160.536 0.192 ;
    END
  END up_in[84]
  PIN up_in[85]
    DIRECTION INPUT ;
    USE SIGNAL ;
    PORT
      LAYER M3 ;
        RECT 160.848 0.000 160.866 0.144 ;
    END
  END up_in[85]
  PIN up_in[86]
    DIRECTION INPUT ;
    USE SIGNAL ;
    PORT
      LAYER M5 ;
        RECT 161.232 0.000 161.256 0.192 ;
    END
  END up_in[86]
  PIN up_in[87]
    DIRECTION INPUT ;
    USE SIGNAL ;
    PORT
      LAYER M3 ;
        RECT 161.604 0.000 161.622 0.144 ;
    END
  END up_in[87]
  PIN up_in[88]
    DIRECTION INPUT ;
    USE SIGNAL ;
    PORT
      LAYER M5 ;
        RECT 161.952 0.000 161.976 0.192 ;
    END
  END up_in[88]
  PIN up_in[89]
    DIRECTION INPUT ;
    USE SIGNAL ;
    PORT
      LAYER M3 ;
        RECT 162.324 0.000 162.342 0.144 ;
    END
  END up_in[89]
  PIN up_in[90]
    DIRECTION INPUT ;
    USE SIGNAL ;
    PORT
      LAYER M5 ;
        RECT 162.672 0.000 162.696 0.192 ;
    END
  END up_in[90]
  PIN up_in[91]
    DIRECTION INPUT ;
    USE SIGNAL ;
    PORT
      LAYER M3 ;
        RECT 163.044 0.000 163.062 0.144 ;
    END
  END up_in[91]
  PIN up_in[92]
    DIRECTION INPUT ;
    USE SIGNAL ;
    PORT
      LAYER M5 ;
        RECT 163.392 0.000 163.416 0.192 ;
    END
  END up_in[92]
  PIN up_in[93]
    DIRECTION INPUT ;
    USE SIGNAL ;
    PORT
      LAYER M3 ;
        RECT 163.764 0.000 163.782 0.144 ;
    END
  END up_in[93]
  PIN up_in[94]
    DIRECTION INPUT ;
    USE SIGNAL ;
    PORT
      LAYER M5 ;
        RECT 164.112 0.000 164.136 0.192 ;
    END
  END up_in[94]
  PIN up_in[95]
    DIRECTION INPUT ;
    USE SIGNAL ;
    PORT
      LAYER M3 ;
        RECT 164.520 0.000 164.538 0.144 ;
    END
  END up_in[95]
  PIN up_in[96]
    DIRECTION INPUT ;
    USE SIGNAL ;
    PORT
      LAYER M5 ;
        RECT 164.880 0.000 164.904 0.192 ;
    END
  END up_in[96]
  PIN up_in[97]
    DIRECTION INPUT ;
    USE SIGNAL ;
    PORT
      LAYER M3 ;
        RECT 165.240 0.000 165.258 0.144 ;
    END
  END up_in[97]
  PIN up_in[98]
    DIRECTION INPUT ;
    USE SIGNAL ;
    PORT
      LAYER M5 ;
        RECT 165.600 0.000 165.624 0.192 ;
    END
  END up_in[98]
  PIN up_in[99]
    DIRECTION INPUT ;
    USE SIGNAL ;
    PORT
      LAYER M3 ;
        RECT 165.960 0.000 165.978 0.144 ;
    END
  END up_in[99]
  PIN up_in[100]
    DIRECTION INPUT ;
    USE SIGNAL ;
    PORT
      LAYER M5 ;
        RECT 166.320 0.000 166.344 0.192 ;
    END
  END up_in[100]
  PIN up_in[101]
    DIRECTION INPUT ;
    USE SIGNAL ;
    PORT
      LAYER M3 ;
        RECT 166.680 0.000 166.698 0.144 ;
    END
  END up_in[101]
  PIN up_in[102]
    DIRECTION INPUT ;
    USE SIGNAL ;
    PORT
      LAYER M5 ;
        RECT 167.040 0.000 167.064 0.192 ;
    END
  END up_in[102]
  PIN up_in[103]
    DIRECTION INPUT ;
    USE SIGNAL ;
    PORT
      LAYER M3 ;
        RECT 167.400 0.000 167.418 0.144 ;
    END
  END up_in[103]
  PIN up_in[104]
    DIRECTION INPUT ;
    USE SIGNAL ;
    PORT
      LAYER M5 ;
        RECT 167.760 0.000 167.784 0.192 ;
    END
  END up_in[104]
  PIN up_in[105]
    DIRECTION INPUT ;
    USE SIGNAL ;
    PORT
      LAYER M3 ;
        RECT 168.156 0.000 168.174 0.144 ;
    END
  END up_in[105]
  PIN up_in[106]
    DIRECTION INPUT ;
    USE SIGNAL ;
    PORT
      LAYER M5 ;
        RECT 168.480 0.000 168.504 0.192 ;
    END
  END up_in[106]
  PIN up_in[107]
    DIRECTION INPUT ;
    USE SIGNAL ;
    PORT
      LAYER M3 ;
        RECT 168.876 0.000 168.894 0.144 ;
    END
  END up_in[107]
  PIN up_in[108]
    DIRECTION INPUT ;
    USE SIGNAL ;
    PORT
      LAYER M5 ;
        RECT 169.248 0.000 169.272 0.192 ;
    END
  END up_in[108]
  PIN up_in[109]
    DIRECTION INPUT ;
    USE SIGNAL ;
    PORT
      LAYER M3 ;
        RECT 169.596 0.000 169.614 0.144 ;
    END
  END up_in[109]
  PIN up_in[110]
    DIRECTION INPUT ;
    USE SIGNAL ;
    PORT
      LAYER M5 ;
        RECT 169.968 0.000 169.992 0.192 ;
    END
  END up_in[110]
  PIN up_in[111]
    DIRECTION INPUT ;
    USE SIGNAL ;
    PORT
      LAYER M3 ;
        RECT 170.316 0.000 170.334 0.144 ;
    END
  END up_in[111]
  PIN up_in[112]
    DIRECTION INPUT ;
    USE SIGNAL ;
    PORT
      LAYER M5 ;
        RECT 170.688 0.000 170.712 0.192 ;
    END
  END up_in[112]
  PIN up_in[113]
    DIRECTION INPUT ;
    USE SIGNAL ;
    PORT
      LAYER M3 ;
        RECT 171.036 0.000 171.054 0.144 ;
    END
  END up_in[113]
  PIN up_in[114]
    DIRECTION INPUT ;
    USE SIGNAL ;
    PORT
      LAYER M5 ;
        RECT 171.408 0.000 171.432 0.192 ;
    END
  END up_in[114]
  PIN up_in[115]
    DIRECTION INPUT ;
    USE SIGNAL ;
    PORT
      LAYER M3 ;
        RECT 171.792 0.000 171.810 0.144 ;
    END
  END up_in[115]
  PIN up_in[116]
    DIRECTION INPUT ;
    USE SIGNAL ;
    PORT
      LAYER M5 ;
        RECT 172.128 0.000 172.152 0.192 ;
    END
  END up_in[116]
  PIN up_in[117]
    DIRECTION INPUT ;
    USE SIGNAL ;
    PORT
      LAYER M3 ;
        RECT 172.512 0.000 172.530 0.144 ;
    END
  END up_in[117]
  PIN up_in[118]
    DIRECTION INPUT ;
    USE SIGNAL ;
    PORT
      LAYER M5 ;
        RECT 172.848 0.000 172.872 0.192 ;
    END
  END up_in[118]
  PIN up_in[119]
    DIRECTION INPUT ;
    USE SIGNAL ;
    PORT
      LAYER M3 ;
        RECT 173.232 0.000 173.250 0.144 ;
    END
  END up_in[119]
  PIN up_in[120]
    DIRECTION INPUT ;
    USE SIGNAL ;
    PORT
      LAYER M5 ;
        RECT 173.568 0.000 173.592 0.192 ;
    END
  END up_in[120]
  PIN up_in[121]
    DIRECTION INPUT ;
    USE SIGNAL ;
    PORT
      LAYER M3 ;
        RECT 173.952 0.000 173.970 0.144 ;
    END
  END up_in[121]
  PIN up_in[122]
    DIRECTION INPUT ;
    USE SIGNAL ;
    PORT
      LAYER M5 ;
        RECT 174.336 0.000 174.360 0.192 ;
    END
  END up_in[122]
  PIN up_in[123]
    DIRECTION INPUT ;
    USE SIGNAL ;
    PORT
      LAYER M3 ;
        RECT 174.672 0.000 174.690 0.144 ;
    END
  END up_in[123]
  PIN up_in[124]
    DIRECTION INPUT ;
    USE SIGNAL ;
    PORT
      LAYER M5 ;
        RECT 175.056 0.000 175.080 0.192 ;
    END
  END up_in[124]
  PIN up_in[125]
    DIRECTION INPUT ;
    USE SIGNAL ;
    PORT
      LAYER M3 ;
        RECT 175.428 0.000 175.446 0.144 ;
    END
  END up_in[125]
  PIN up_in[126]
    DIRECTION INPUT ;
    USE SIGNAL ;
    PORT
      LAYER M5 ;
        RECT 175.776 0.000 175.800 0.192 ;
    END
  END up_in[126]
  PIN up_in[127]
    DIRECTION INPUT ;
    USE SIGNAL ;
    PORT
      LAYER M3 ;
        RECT 176.148 0.000 176.166 0.144 ;
    END
  END up_in[127]
  PIN up_in[128]
    DIRECTION INPUT ;
    USE SIGNAL ;
    PORT
      LAYER M5 ;
        RECT 176.496 0.000 176.520 0.192 ;
    END
  END up_in[128]
  PIN up_in[129]
    DIRECTION INPUT ;
    USE SIGNAL ;
    PORT
      LAYER M3 ;
        RECT 176.868 0.000 176.886 0.144 ;
    END
  END up_in[129]
  PIN up_in[130]
    DIRECTION INPUT ;
    USE SIGNAL ;
    PORT
      LAYER M5 ;
        RECT 177.216 0.000 177.240 0.192 ;
    END
  END up_in[130]
  PIN up_in[131]
    DIRECTION INPUT ;
    USE SIGNAL ;
    PORT
      LAYER M3 ;
        RECT 177.588 0.000 177.606 0.144 ;
    END
  END up_in[131]
  PIN up_in[132]
    DIRECTION INPUT ;
    USE SIGNAL ;
    PORT
      LAYER M5 ;
        RECT 177.936 0.000 177.960 0.192 ;
    END
  END up_in[132]
  PIN up_in[133]
    DIRECTION INPUT ;
    USE SIGNAL ;
    PORT
      LAYER M3 ;
        RECT 178.308 0.000 178.326 0.144 ;
    END
  END up_in[133]
  PIN up_in[134]
    DIRECTION INPUT ;
    USE SIGNAL ;
    PORT
      LAYER M5 ;
        RECT 178.704 0.000 178.728 0.192 ;
    END
  END up_in[134]
  PIN up_in[135]
    DIRECTION INPUT ;
    USE SIGNAL ;
    PORT
      LAYER M3 ;
        RECT 179.064 0.000 179.082 0.144 ;
    END
  END up_in[135]
  PIN up_in[136]
    DIRECTION INPUT ;
    USE SIGNAL ;
    PORT
      LAYER M5 ;
        RECT 179.424 0.000 179.448 0.192 ;
    END
  END up_in[136]
  PIN up_in[137]
    DIRECTION INPUT ;
    USE SIGNAL ;
    PORT
      LAYER M3 ;
        RECT 179.784 0.000 179.802 0.144 ;
    END
  END up_in[137]
  PIN up_in[138]
    DIRECTION INPUT ;
    USE SIGNAL ;
    PORT
      LAYER M5 ;
        RECT 180.144 0.000 180.168 0.192 ;
    END
  END up_in[138]
  PIN up_in[139]
    DIRECTION INPUT ;
    USE SIGNAL ;
    PORT
      LAYER M3 ;
        RECT 180.504 0.000 180.522 0.144 ;
    END
  END up_in[139]
  PIN up_in[140]
    DIRECTION INPUT ;
    USE SIGNAL ;
    PORT
      LAYER M5 ;
        RECT 180.864 0.000 180.888 0.192 ;
    END
  END up_in[140]
  PIN up_in[141]
    DIRECTION INPUT ;
    USE SIGNAL ;
    PORT
      LAYER M3 ;
        RECT 181.224 0.000 181.242 0.144 ;
    END
  END up_in[141]
  PIN up_in[142]
    DIRECTION INPUT ;
    USE SIGNAL ;
    PORT
      LAYER M5 ;
        RECT 181.584 0.000 181.608 0.192 ;
    END
  END up_in[142]
  PIN up_in[143]
    DIRECTION INPUT ;
    USE SIGNAL ;
    PORT
      LAYER M3 ;
        RECT 181.944 0.000 181.962 0.144 ;
    END
  END up_in[143]
  PIN up_in[144]
    DIRECTION INPUT ;
    USE SIGNAL ;
    PORT
      LAYER M5 ;
        RECT 182.304 0.000 182.328 0.192 ;
    END
  END up_in[144]
  PIN up_in[145]
    DIRECTION INPUT ;
    USE SIGNAL ;
    PORT
      LAYER M3 ;
        RECT 182.700 0.000 182.718 0.144 ;
    END
  END up_in[145]
  PIN up_in[146]
    DIRECTION INPUT ;
    USE SIGNAL ;
    PORT
      LAYER M5 ;
        RECT 183.024 0.000 183.048 0.192 ;
    END
  END up_in[146]
  PIN up_in[147]
    DIRECTION INPUT ;
    USE SIGNAL ;
    PORT
      LAYER M3 ;
        RECT 183.420 0.000 183.438 0.144 ;
    END
  END up_in[147]
  PIN up_in[148]
    DIRECTION INPUT ;
    USE SIGNAL ;
    PORT
      LAYER M5 ;
        RECT 183.792 0.000 183.816 0.192 ;
    END
  END up_in[148]
  PIN up_in[149]
    DIRECTION INPUT ;
    USE SIGNAL ;
    PORT
      LAYER M3 ;
        RECT 184.140 0.000 184.158 0.144 ;
    END
  END up_in[149]
  PIN up_in[150]
    DIRECTION INPUT ;
    USE SIGNAL ;
    PORT
      LAYER M5 ;
        RECT 184.512 0.000 184.536 0.192 ;
    END
  END up_in[150]
  PIN up_in[151]
    DIRECTION INPUT ;
    USE SIGNAL ;
    PORT
      LAYER M3 ;
        RECT 184.860 0.000 184.878 0.144 ;
    END
  END up_in[151]
  PIN up_in[152]
    DIRECTION INPUT ;
    USE SIGNAL ;
    PORT
      LAYER M5 ;
        RECT 185.232 0.000 185.256 0.192 ;
    END
  END up_in[152]
  PIN up_in[153]
    DIRECTION INPUT ;
    USE SIGNAL ;
    PORT
      LAYER M3 ;
        RECT 185.580 0.000 185.598 0.144 ;
    END
  END up_in[153]
  PIN up_in[154]
    DIRECTION INPUT ;
    USE SIGNAL ;
    PORT
      LAYER M5 ;
        RECT 185.952 0.000 185.976 0.192 ;
    END
  END up_in[154]
  PIN up_in[155]
    DIRECTION INPUT ;
    USE SIGNAL ;
    PORT
      LAYER M3 ;
        RECT 186.336 0.000 186.354 0.144 ;
    END
  END up_in[155]
  PIN up_in[156]
    DIRECTION INPUT ;
    USE SIGNAL ;
    PORT
      LAYER M5 ;
        RECT 186.672 0.000 186.696 0.192 ;
    END
  END up_in[156]
  PIN up_in[157]
    DIRECTION INPUT ;
    USE SIGNAL ;
    PORT
      LAYER M3 ;
        RECT 187.056 0.000 187.074 0.144 ;
    END
  END up_in[157]
  PIN up_in[158]
    DIRECTION INPUT ;
    USE SIGNAL ;
    PORT
      LAYER M5 ;
        RECT 187.392 0.000 187.416 0.192 ;
    END
  END up_in[158]
  PIN up_in[159]
    DIRECTION INPUT ;
    USE SIGNAL ;
    PORT
      LAYER M3 ;
        RECT 187.776 0.000 187.794 0.144 ;
    END
  END up_in[159]
  PIN up_in[160]
    DIRECTION INPUT ;
    USE SIGNAL ;
    PORT
      LAYER M5 ;
        RECT 188.160 0.000 188.184 0.192 ;
    END
  END up_in[160]
  PIN up_in[161]
    DIRECTION INPUT ;
    USE SIGNAL ;
    PORT
      LAYER M3 ;
        RECT 188.496 0.000 188.514 0.144 ;
    END
  END up_in[161]
  PIN up_in[162]
    DIRECTION INPUT ;
    USE SIGNAL ;
    PORT
      LAYER M5 ;
        RECT 188.880 0.000 188.904 0.192 ;
    END
  END up_in[162]
  PIN up_in[163]
    DIRECTION INPUT ;
    USE SIGNAL ;
    PORT
      LAYER M3 ;
        RECT 189.216 0.000 189.234 0.144 ;
    END
  END up_in[163]
  PIN up_in[164]
    DIRECTION INPUT ;
    USE SIGNAL ;
    PORT
      LAYER M5 ;
        RECT 189.600 0.000 189.624 0.192 ;
    END
  END up_in[164]
  PIN up_in[165]
    DIRECTION INPUT ;
    USE SIGNAL ;
    PORT
      LAYER M3 ;
        RECT 189.972 0.000 189.990 0.144 ;
    END
  END up_in[165]
  PIN up_in[166]
    DIRECTION INPUT ;
    USE SIGNAL ;
    PORT
      LAYER M5 ;
        RECT 190.320 0.000 190.344 0.192 ;
    END
  END up_in[166]
  PIN up_in[167]
    DIRECTION INPUT ;
    USE SIGNAL ;
    PORT
      LAYER M3 ;
        RECT 190.692 0.000 190.710 0.144 ;
    END
  END up_in[167]
  PIN up_in[168]
    DIRECTION INPUT ;
    USE SIGNAL ;
    PORT
      LAYER M5 ;
        RECT 191.040 0.000 191.064 0.192 ;
    END
  END up_in[168]
  PIN up_in[169]
    DIRECTION INPUT ;
    USE SIGNAL ;
    PORT
      LAYER M3 ;
        RECT 191.412 0.000 191.430 0.144 ;
    END
  END up_in[169]
  PIN up_in[170]
    DIRECTION INPUT ;
    USE SIGNAL ;
    PORT
      LAYER M5 ;
        RECT 191.760 0.000 191.784 0.192 ;
    END
  END up_in[170]
  PIN up_in[171]
    DIRECTION INPUT ;
    USE SIGNAL ;
    PORT
      LAYER M3 ;
        RECT 192.132 0.000 192.150 0.144 ;
    END
  END up_in[171]
  PIN up_in[172]
    DIRECTION INPUT ;
    USE SIGNAL ;
    PORT
      LAYER M5 ;
        RECT 192.480 0.000 192.504 0.192 ;
    END
  END up_in[172]
  PIN up_in[173]
    DIRECTION INPUT ;
    USE SIGNAL ;
    PORT
      LAYER M3 ;
        RECT 192.852 0.000 192.870 0.144 ;
    END
  END up_in[173]
  PIN up_in[174]
    DIRECTION INPUT ;
    USE SIGNAL ;
    PORT
      LAYER M5 ;
        RECT 193.248 0.000 193.272 0.192 ;
    END
  END up_in[174]
  PIN up_in[175]
    DIRECTION INPUT ;
    USE SIGNAL ;
    PORT
      LAYER M3 ;
        RECT 193.608 0.000 193.626 0.144 ;
    END
  END up_in[175]
  PIN up_in[176]
    DIRECTION INPUT ;
    USE SIGNAL ;
    PORT
      LAYER M5 ;
        RECT 193.968 0.000 193.992 0.192 ;
    END
  END up_in[176]
  PIN up_in[177]
    DIRECTION INPUT ;
    USE SIGNAL ;
    PORT
      LAYER M3 ;
        RECT 194.328 0.000 194.346 0.144 ;
    END
  END up_in[177]
  PIN up_in[178]
    DIRECTION INPUT ;
    USE SIGNAL ;
    PORT
      LAYER M5 ;
        RECT 194.688 0.000 194.712 0.192 ;
    END
  END up_in[178]
  PIN up_in[179]
    DIRECTION INPUT ;
    USE SIGNAL ;
    PORT
      LAYER M3 ;
        RECT 195.048 0.000 195.066 0.144 ;
    END
  END up_in[179]
  PIN up_in[180]
    DIRECTION INPUT ;
    USE SIGNAL ;
    PORT
      LAYER M5 ;
        RECT 195.408 0.000 195.432 0.192 ;
    END
  END up_in[180]
  PIN up_in[181]
    DIRECTION INPUT ;
    USE SIGNAL ;
    PORT
      LAYER M3 ;
        RECT 195.768 0.000 195.786 0.144 ;
    END
  END up_in[181]
  PIN up_in[182]
    DIRECTION INPUT ;
    USE SIGNAL ;
    PORT
      LAYER M5 ;
        RECT 196.128 0.000 196.152 0.192 ;
    END
  END up_in[182]
  PIN up_in[183]
    DIRECTION INPUT ;
    USE SIGNAL ;
    PORT
      LAYER M3 ;
        RECT 196.488 0.000 196.506 0.144 ;
    END
  END up_in[183]
  PIN up_in[184]
    DIRECTION INPUT ;
    USE SIGNAL ;
    PORT
      LAYER M5 ;
        RECT 196.848 0.000 196.872 0.192 ;
    END
  END up_in[184]
  PIN up_in[185]
    DIRECTION INPUT ;
    USE SIGNAL ;
    PORT
      LAYER M3 ;
        RECT 197.244 0.000 197.262 0.144 ;
    END
  END up_in[185]
  PIN up_in[186]
    DIRECTION INPUT ;
    USE SIGNAL ;
    PORT
      LAYER M5 ;
        RECT 197.568 0.000 197.592 0.192 ;
    END
  END up_in[186]
  PIN up_in[187]
    DIRECTION INPUT ;
    USE SIGNAL ;
    PORT
      LAYER M3 ;
        RECT 197.964 0.000 197.982 0.144 ;
    END
  END up_in[187]
  PIN up_in[188]
    DIRECTION INPUT ;
    USE SIGNAL ;
    PORT
      LAYER M5 ;
        RECT 198.336 0.000 198.360 0.192 ;
    END
  END up_in[188]
  PIN up_in[189]
    DIRECTION INPUT ;
    USE SIGNAL ;
    PORT
      LAYER M3 ;
        RECT 198.684 0.000 198.702 0.144 ;
    END
  END up_in[189]
  PIN up_in[190]
    DIRECTION INPUT ;
    USE SIGNAL ;
    PORT
      LAYER M5 ;
        RECT 199.056 0.000 199.080 0.192 ;
    END
  END up_in[190]
  PIN up_in[191]
    DIRECTION INPUT ;
    USE SIGNAL ;
    PORT
      LAYER M3 ;
        RECT 199.404 0.000 199.422 0.144 ;
    END
  END up_in[191]
  PIN up_in[192]
    DIRECTION INPUT ;
    USE SIGNAL ;
    PORT
      LAYER M5 ;
        RECT 199.776 0.000 199.800 0.192 ;
    END
  END up_in[192]
  PIN up_in[193]
    DIRECTION INPUT ;
    USE SIGNAL ;
    PORT
      LAYER M3 ;
        RECT 200.124 0.000 200.142 0.144 ;
    END
  END up_in[193]
  PIN up_in[194]
    DIRECTION INPUT ;
    USE SIGNAL ;
    PORT
      LAYER M5 ;
        RECT 200.496 0.000 200.520 0.192 ;
    END
  END up_in[194]
  PIN up_in[195]
    DIRECTION INPUT ;
    USE SIGNAL ;
    PORT
      LAYER M3 ;
        RECT 200.880 0.000 200.898 0.144 ;
    END
  END up_in[195]
  PIN up_in[196]
    DIRECTION INPUT ;
    USE SIGNAL ;
    PORT
      LAYER M5 ;
        RECT 201.216 0.000 201.240 0.192 ;
    END
  END up_in[196]
  PIN up_in[197]
    DIRECTION INPUT ;
    USE SIGNAL ;
    PORT
      LAYER M3 ;
        RECT 201.600 0.000 201.618 0.144 ;
    END
  END up_in[197]
  PIN up_in[198]
    DIRECTION INPUT ;
    USE SIGNAL ;
    PORT
      LAYER M5 ;
        RECT 201.936 0.000 201.960 0.192 ;
    END
  END up_in[198]
  PIN up_in[199]
    DIRECTION INPUT ;
    USE SIGNAL ;
    PORT
      LAYER M3 ;
        RECT 202.320 0.000 202.338 0.144 ;
    END
  END up_in[199]
  PIN up_in[200]
    DIRECTION INPUT ;
    USE SIGNAL ;
    PORT
      LAYER M5 ;
        RECT 202.704 0.000 202.728 0.192 ;
    END
  END up_in[200]
  PIN up_in[201]
    DIRECTION INPUT ;
    USE SIGNAL ;
    PORT
      LAYER M3 ;
        RECT 203.040 0.000 203.058 0.144 ;
    END
  END up_in[201]
  PIN up_in[202]
    DIRECTION INPUT ;
    USE SIGNAL ;
    PORT
      LAYER M5 ;
        RECT 203.424 0.000 203.448 0.192 ;
    END
  END up_in[202]
  PIN up_in[203]
    DIRECTION INPUT ;
    USE SIGNAL ;
    PORT
      LAYER M3 ;
        RECT 203.760 0.000 203.778 0.144 ;
    END
  END up_in[203]
  PIN up_in[204]
    DIRECTION INPUT ;
    USE SIGNAL ;
    PORT
      LAYER M5 ;
        RECT 204.144 0.000 204.168 0.192 ;
    END
  END up_in[204]
  PIN up_in[205]
    DIRECTION INPUT ;
    USE SIGNAL ;
    PORT
      LAYER M3 ;
        RECT 204.516 0.000 204.534 0.144 ;
    END
  END up_in[205]
  PIN up_in[206]
    DIRECTION INPUT ;
    USE SIGNAL ;
    PORT
      LAYER M5 ;
        RECT 204.864 0.000 204.888 0.192 ;
    END
  END up_in[206]
  PIN up_in[207]
    DIRECTION INPUT ;
    USE SIGNAL ;
    PORT
      LAYER M3 ;
        RECT 205.236 0.000 205.254 0.144 ;
    END
  END up_in[207]
  PIN up_in[208]
    DIRECTION INPUT ;
    USE SIGNAL ;
    PORT
      LAYER M5 ;
        RECT 205.584 0.000 205.608 0.192 ;
    END
  END up_in[208]
  PIN up_in[209]
    DIRECTION INPUT ;
    USE SIGNAL ;
    PORT
      LAYER M3 ;
        RECT 205.956 0.000 205.974 0.144 ;
    END
  END up_in[209]
  PIN up_in[210]
    DIRECTION INPUT ;
    USE SIGNAL ;
    PORT
      LAYER M5 ;
        RECT 206.304 0.000 206.328 0.192 ;
    END
  END up_in[210]
  PIN up_in[211]
    DIRECTION INPUT ;
    USE SIGNAL ;
    PORT
      LAYER M3 ;
        RECT 206.676 0.000 206.694 0.144 ;
    END
  END up_in[211]
  PIN up_in[212]
    DIRECTION INPUT ;
    USE SIGNAL ;
    PORT
      LAYER M5 ;
        RECT 207.024 0.000 207.048 0.192 ;
    END
  END up_in[212]
  PIN up_in[213]
    DIRECTION INPUT ;
    USE SIGNAL ;
    PORT
      LAYER M3 ;
        RECT 207.396 0.000 207.414 0.144 ;
    END
  END up_in[213]
  PIN up_in[214]
    DIRECTION INPUT ;
    USE SIGNAL ;
    PORT
      LAYER M5 ;
        RECT 207.792 0.000 207.816 0.192 ;
    END
  END up_in[214]
  PIN up_in[215]
    DIRECTION INPUT ;
    USE SIGNAL ;
    PORT
      LAYER M3 ;
        RECT 208.152 0.000 208.170 0.144 ;
    END
  END up_in[215]
  PIN up_in[216]
    DIRECTION INPUT ;
    USE SIGNAL ;
    PORT
      LAYER M5 ;
        RECT 208.512 0.000 208.536 0.192 ;
    END
  END up_in[216]
  PIN up_in[217]
    DIRECTION INPUT ;
    USE SIGNAL ;
    PORT
      LAYER M3 ;
        RECT 208.872 0.000 208.890 0.144 ;
    END
  END up_in[217]
  PIN up_in[218]
    DIRECTION INPUT ;
    USE SIGNAL ;
    PORT
      LAYER M5 ;
        RECT 209.232 0.000 209.256 0.192 ;
    END
  END up_in[218]
  PIN up_in[219]
    DIRECTION INPUT ;
    USE SIGNAL ;
    PORT
      LAYER M3 ;
        RECT 209.592 0.000 209.610 0.144 ;
    END
  END up_in[219]
  PIN up_in[220]
    DIRECTION INPUT ;
    USE SIGNAL ;
    PORT
      LAYER M5 ;
        RECT 209.952 0.000 209.976 0.192 ;
    END
  END up_in[220]
  PIN up_in[221]
    DIRECTION INPUT ;
    USE SIGNAL ;
    PORT
      LAYER M3 ;
        RECT 210.312 0.000 210.330 0.144 ;
    END
  END up_in[221]
  PIN up_in[222]
    DIRECTION INPUT ;
    USE SIGNAL ;
    PORT
      LAYER M5 ;
        RECT 210.672 0.000 210.696 0.192 ;
    END
  END up_in[222]
  PIN up_in[223]
    DIRECTION INPUT ;
    USE SIGNAL ;
    PORT
      LAYER M3 ;
        RECT 211.068 0.000 211.086 0.144 ;
    END
  END up_in[223]
  PIN up_in[224]
    DIRECTION INPUT ;
    USE SIGNAL ;
    PORT
      LAYER M5 ;
        RECT 211.392 0.000 211.416 0.192 ;
    END
  END up_in[224]
  PIN up_in[225]
    DIRECTION INPUT ;
    USE SIGNAL ;
    PORT
      LAYER M3 ;
        RECT 211.788 0.000 211.806 0.144 ;
    END
  END up_in[225]
  PIN up_in[226]
    DIRECTION INPUT ;
    USE SIGNAL ;
    PORT
      LAYER M5 ;
        RECT 212.160 0.000 212.184 0.192 ;
    END
  END up_in[226]
  PIN up_in[227]
    DIRECTION INPUT ;
    USE SIGNAL ;
    PORT
      LAYER M3 ;
        RECT 212.508 0.000 212.526 0.144 ;
    END
  END up_in[227]
  PIN up_in[228]
    DIRECTION INPUT ;
    USE SIGNAL ;
    PORT
      LAYER M5 ;
        RECT 212.880 0.000 212.904 0.192 ;
    END
  END up_in[228]
  PIN up_in[229]
    DIRECTION INPUT ;
    USE SIGNAL ;
    PORT
      LAYER M3 ;
        RECT 213.228 0.000 213.246 0.144 ;
    END
  END up_in[229]
  PIN up_in[230]
    DIRECTION INPUT ;
    USE SIGNAL ;
    PORT
      LAYER M5 ;
        RECT 213.600 0.000 213.624 0.192 ;
    END
  END up_in[230]
  PIN up_in[231]
    DIRECTION INPUT ;
    USE SIGNAL ;
    PORT
      LAYER M3 ;
        RECT 213.948 0.000 213.966 0.144 ;
    END
  END up_in[231]
  PIN up_in[232]
    DIRECTION INPUT ;
    USE SIGNAL ;
    PORT
      LAYER M5 ;
        RECT 214.320 0.000 214.344 0.192 ;
    END
  END up_in[232]
  PIN up_in[233]
    DIRECTION INPUT ;
    USE SIGNAL ;
    PORT
      LAYER M3 ;
        RECT 214.704 0.000 214.722 0.144 ;
    END
  END up_in[233]
  PIN up_in[234]
    DIRECTION INPUT ;
    USE SIGNAL ;
    PORT
      LAYER M5 ;
        RECT 215.040 0.000 215.064 0.192 ;
    END
  END up_in[234]
  PIN up_in[235]
    DIRECTION INPUT ;
    USE SIGNAL ;
    PORT
      LAYER M3 ;
        RECT 215.424 0.000 215.442 0.144 ;
    END
  END up_in[235]
  PIN up_in[236]
    DIRECTION INPUT ;
    USE SIGNAL ;
    PORT
      LAYER M5 ;
        RECT 215.760 0.000 215.784 0.192 ;
    END
  END up_in[236]
  PIN up_in[237]
    DIRECTION INPUT ;
    USE SIGNAL ;
    PORT
      LAYER M3 ;
        RECT 216.144 0.000 216.162 0.144 ;
    END
  END up_in[237]
  PIN up_in[238]
    DIRECTION INPUT ;
    USE SIGNAL ;
    PORT
      LAYER M5 ;
        RECT 216.480 0.000 216.504 0.192 ;
    END
  END up_in[238]
  PIN up_in[239]
    DIRECTION INPUT ;
    USE SIGNAL ;
    PORT
      LAYER M3 ;
        RECT 216.864 0.000 216.882 0.144 ;
    END
  END up_in[239]
  PIN up_in[240]
    DIRECTION INPUT ;
    USE SIGNAL ;
    PORT
      LAYER M5 ;
        RECT 217.248 0.000 217.272 0.192 ;
    END
  END up_in[240]
  PIN up_in[241]
    DIRECTION INPUT ;
    USE SIGNAL ;
    PORT
      LAYER M3 ;
        RECT 217.584 0.000 217.602 0.144 ;
    END
  END up_in[241]
  PIN up_in[242]
    DIRECTION INPUT ;
    USE SIGNAL ;
    PORT
      LAYER M5 ;
        RECT 217.968 0.000 217.992 0.192 ;
    END
  END up_in[242]
  PIN up_in[243]
    DIRECTION INPUT ;
    USE SIGNAL ;
    PORT
      LAYER M3 ;
        RECT 218.340 0.000 218.358 0.144 ;
    END
  END up_in[243]
  PIN up_in[244]
    DIRECTION INPUT ;
    USE SIGNAL ;
    PORT
      LAYER M5 ;
        RECT 218.688 0.000 218.712 0.192 ;
    END
  END up_in[244]
  PIN up_in[245]
    DIRECTION INPUT ;
    USE SIGNAL ;
    PORT
      LAYER M3 ;
        RECT 219.060 0.000 219.078 0.144 ;
    END
  END up_in[245]
  PIN up_in[246]
    DIRECTION INPUT ;
    USE SIGNAL ;
    PORT
      LAYER M5 ;
        RECT 219.408 0.000 219.432 0.192 ;
    END
  END up_in[246]
  PIN up_in[247]
    DIRECTION INPUT ;
    USE SIGNAL ;
    PORT
      LAYER M3 ;
        RECT 219.780 0.000 219.798 0.144 ;
    END
  END up_in[247]
  PIN up_in[248]
    DIRECTION INPUT ;
    USE SIGNAL ;
    PORT
      LAYER M5 ;
        RECT 220.128 0.000 220.152 0.192 ;
    END
  END up_in[248]
  PIN up_in[249]
    DIRECTION INPUT ;
    USE SIGNAL ;
    PORT
      LAYER M3 ;
        RECT 220.500 0.000 220.518 0.144 ;
    END
  END up_in[249]
  PIN up_in[250]
    DIRECTION INPUT ;
    USE SIGNAL ;
    PORT
      LAYER M5 ;
        RECT 220.848 0.000 220.872 0.192 ;
    END
  END up_in[250]
  PIN up_in[251]
    DIRECTION INPUT ;
    USE SIGNAL ;
    PORT
      LAYER M3 ;
        RECT 221.220 0.000 221.238 0.144 ;
    END
  END up_in[251]
  PIN up_in[252]
    DIRECTION INPUT ;
    USE SIGNAL ;
    PORT
      LAYER M5 ;
        RECT 221.616 0.000 221.640 0.192 ;
    END
  END up_in[252]
  PIN up_in[253]
    DIRECTION INPUT ;
    USE SIGNAL ;
    PORT
      LAYER M3 ;
        RECT 221.976 0.000 221.994 0.144 ;
    END
  END up_in[253]
  PIN up_in[254]
    DIRECTION INPUT ;
    USE SIGNAL ;
    PORT
      LAYER M5 ;
        RECT 222.336 0.000 222.360 0.192 ;
    END
  END up_in[254]
  PIN up_in[255]
    DIRECTION INPUT ;
    USE SIGNAL ;
    PORT
      LAYER M3 ;
        RECT 222.696 0.000 222.714 0.144 ;
    END
  END up_in[255]
  PIN up_in[256]
    DIRECTION INPUT ;
    USE SIGNAL ;
    PORT
      LAYER M5 ;
        RECT 223.056 0.000 223.080 0.192 ;
    END
  END up_in[256]
  PIN up_in[257]
    DIRECTION INPUT ;
    USE SIGNAL ;
    PORT
      LAYER M3 ;
        RECT 223.416 0.000 223.434 0.144 ;
    END
  END up_in[257]
  PIN up_in[258]
    DIRECTION INPUT ;
    USE SIGNAL ;
    PORT
      LAYER M5 ;
        RECT 223.776 0.000 223.800 0.192 ;
    END
  END up_in[258]
  PIN up_in[259]
    DIRECTION INPUT ;
    USE SIGNAL ;
    PORT
      LAYER M3 ;
        RECT 224.136 0.000 224.154 0.144 ;
    END
  END up_in[259]
  PIN up_in[260]
    DIRECTION INPUT ;
    USE SIGNAL ;
    PORT
      LAYER M5 ;
        RECT 224.496 0.000 224.520 0.192 ;
    END
  END up_in[260]
  PIN up_in[261]
    DIRECTION INPUT ;
    USE SIGNAL ;
    PORT
      LAYER M3 ;
        RECT 224.856 0.000 224.874 0.144 ;
    END
  END up_in[261]
  PIN up_in[262]
    DIRECTION INPUT ;
    USE SIGNAL ;
    PORT
      LAYER M5 ;
        RECT 225.216 0.000 225.240 0.192 ;
    END
  END up_in[262]
  PIN up_in[263]
    DIRECTION INPUT ;
    USE SIGNAL ;
    PORT
      LAYER M3 ;
        RECT 225.612 0.000 225.630 0.144 ;
    END
  END up_in[263]
  PIN up_in[264]
    DIRECTION INPUT ;
    USE SIGNAL ;
    PORT
      LAYER M5 ;
        RECT 225.936 0.000 225.960 0.192 ;
    END
  END up_in[264]
  PIN up_in[265]
    DIRECTION INPUT ;
    USE SIGNAL ;
    PORT
      LAYER M3 ;
        RECT 226.332 0.000 226.350 0.144 ;
    END
  END up_in[265]
  PIN up_in[266]
    DIRECTION INPUT ;
    USE SIGNAL ;
    PORT
      LAYER M5 ;
        RECT 226.704 0.000 226.728 0.192 ;
    END
  END up_in[266]
  PIN up_in[267]
    DIRECTION INPUT ;
    USE SIGNAL ;
    PORT
      LAYER M3 ;
        RECT 227.052 0.000 227.070 0.144 ;
    END
  END up_in[267]
  PIN up_in[268]
    DIRECTION INPUT ;
    USE SIGNAL ;
    PORT
      LAYER M5 ;
        RECT 227.424 0.000 227.448 0.192 ;
    END
  END up_in[268]
  PIN up_in[269]
    DIRECTION INPUT ;
    USE SIGNAL ;
    PORT
      LAYER M3 ;
        RECT 227.772 0.000 227.790 0.144 ;
    END
  END up_in[269]
  PIN up_in[270]
    DIRECTION INPUT ;
    USE SIGNAL ;
    PORT
      LAYER M5 ;
        RECT 228.144 0.000 228.168 0.192 ;
    END
  END up_in[270]
  PIN up_in[271]
    DIRECTION INPUT ;
    USE SIGNAL ;
    PORT
      LAYER M3 ;
        RECT 228.492 0.000 228.510 0.144 ;
    END
  END up_in[271]
  PIN up_in[272]
    DIRECTION INPUT ;
    USE SIGNAL ;
    PORT
      LAYER M5 ;
        RECT 228.864 0.000 228.888 0.192 ;
    END
  END up_in[272]
  PIN up_in[273]
    DIRECTION INPUT ;
    USE SIGNAL ;
    PORT
      LAYER M3 ;
        RECT 229.248 0.000 229.266 0.144 ;
    END
  END up_in[273]
  PIN up_in[274]
    DIRECTION INPUT ;
    USE SIGNAL ;
    PORT
      LAYER M5 ;
        RECT 229.584 0.000 229.608 0.192 ;
    END
  END up_in[274]
  PIN up_in[275]
    DIRECTION INPUT ;
    USE SIGNAL ;
    PORT
      LAYER M3 ;
        RECT 229.968 0.000 229.986 0.144 ;
    END
  END up_in[275]
  PIN up_in[276]
    DIRECTION INPUT ;
    USE SIGNAL ;
    PORT
      LAYER M5 ;
        RECT 230.304 0.000 230.328 0.192 ;
    END
  END up_in[276]
  PIN up_in[277]
    DIRECTION INPUT ;
    USE SIGNAL ;
    PORT
      LAYER M3 ;
        RECT 230.688 0.000 230.706 0.144 ;
    END
  END up_in[277]
  PIN up_in[278]
    DIRECTION INPUT ;
    USE SIGNAL ;
    PORT
      LAYER M5 ;
        RECT 231.072 0.000 231.096 0.192 ;
    END
  END up_in[278]
  PIN up_in[279]
    DIRECTION INPUT ;
    USE SIGNAL ;
    PORT
      LAYER M3 ;
        RECT 231.408 0.000 231.426 0.144 ;
    END
  END up_in[279]
  PIN up_in[280]
    DIRECTION INPUT ;
    USE SIGNAL ;
    PORT
      LAYER M5 ;
        RECT 231.792 0.000 231.816 0.192 ;
    END
  END up_in[280]
  PIN up_in[281]
    DIRECTION INPUT ;
    USE SIGNAL ;
    PORT
      LAYER M3 ;
        RECT 232.128 0.000 232.146 0.144 ;
    END
  END up_in[281]
  PIN up_in[282]
    DIRECTION INPUT ;
    USE SIGNAL ;
    PORT
      LAYER M5 ;
        RECT 232.512 0.000 232.536 0.192 ;
    END
  END up_in[282]
  PIN up_in[283]
    DIRECTION INPUT ;
    USE SIGNAL ;
    PORT
      LAYER M3 ;
        RECT 232.884 0.000 232.902 0.144 ;
    END
  END up_in[283]
  PIN up_in[284]
    DIRECTION INPUT ;
    USE SIGNAL ;
    PORT
      LAYER M5 ;
        RECT 233.232 0.000 233.256 0.192 ;
    END
  END up_in[284]
  PIN up_in[285]
    DIRECTION INPUT ;
    USE SIGNAL ;
    PORT
      LAYER M3 ;
        RECT 233.604 0.000 233.622 0.144 ;
    END
  END up_in[285]
  PIN up_in[286]
    DIRECTION INPUT ;
    USE SIGNAL ;
    PORT
      LAYER M5 ;
        RECT 233.952 0.000 233.976 0.192 ;
    END
  END up_in[286]
  PIN up_in[287]
    DIRECTION INPUT ;
    USE SIGNAL ;
    PORT
      LAYER M3 ;
        RECT 234.324 0.000 234.342 0.144 ;
    END
  END up_in[287]
  PIN up_in[288]
    DIRECTION INPUT ;
    USE SIGNAL ;
    PORT
      LAYER M5 ;
        RECT 234.672 0.000 234.696 0.192 ;
    END
  END up_in[288]
  PIN up_in[289]
    DIRECTION INPUT ;
    USE SIGNAL ;
    PORT
      LAYER M3 ;
        RECT 235.044 0.000 235.062 0.144 ;
    END
  END up_in[289]
  PIN up_in[290]
    DIRECTION INPUT ;
    USE SIGNAL ;
    PORT
      LAYER M5 ;
        RECT 235.392 0.000 235.416 0.192 ;
    END
  END up_in[290]
  PIN up_in[291]
    DIRECTION INPUT ;
    USE SIGNAL ;
    PORT
      LAYER M3 ;
        RECT 235.764 0.000 235.782 0.144 ;
    END
  END up_in[291]
  PIN up_in[292]
    DIRECTION INPUT ;
    USE SIGNAL ;
    PORT
      LAYER M5 ;
        RECT 236.160 0.000 236.184 0.192 ;
    END
  END up_in[292]
  PIN up_in[293]
    DIRECTION INPUT ;
    USE SIGNAL ;
    PORT
      LAYER M3 ;
        RECT 236.520 0.000 236.538 0.144 ;
    END
  END up_in[293]
  PIN up_in[294]
    DIRECTION INPUT ;
    USE SIGNAL ;
    PORT
      LAYER M5 ;
        RECT 236.880 0.000 236.904 0.192 ;
    END
  END up_in[294]
  PIN up_in[295]
    DIRECTION INPUT ;
    USE SIGNAL ;
    PORT
      LAYER M3 ;
        RECT 237.240 0.000 237.258 0.144 ;
    END
  END up_in[295]
  PIN up_in[296]
    DIRECTION INPUT ;
    USE SIGNAL ;
    PORT
      LAYER M5 ;
        RECT 237.600 0.000 237.624 0.192 ;
    END
  END up_in[296]
  PIN up_in[297]
    DIRECTION INPUT ;
    USE SIGNAL ;
    PORT
      LAYER M3 ;
        RECT 237.960 0.000 237.978 0.144 ;
    END
  END up_in[297]
  PIN up_in[298]
    DIRECTION INPUT ;
    USE SIGNAL ;
    PORT
      LAYER M5 ;
        RECT 238.320 0.000 238.344 0.192 ;
    END
  END up_in[298]
  PIN up_in[299]
    DIRECTION INPUT ;
    USE SIGNAL ;
    PORT
      LAYER M3 ;
        RECT 238.680 0.000 238.698 0.144 ;
    END
  END up_in[299]
  PIN up_in[300]
    DIRECTION INPUT ;
    USE SIGNAL ;
    PORT
      LAYER M5 ;
        RECT 239.040 0.000 239.064 0.192 ;
    END
  END up_in[300]
  PIN up_in[301]
    DIRECTION INPUT ;
    USE SIGNAL ;
    PORT
      LAYER M3 ;
        RECT 239.400 0.000 239.418 0.144 ;
    END
  END up_in[301]
  PIN up_in[302]
    DIRECTION INPUT ;
    USE SIGNAL ;
    PORT
      LAYER M5 ;
        RECT 239.760 0.000 239.784 0.192 ;
    END
  END up_in[302]
  PIN up_in[303]
    DIRECTION INPUT ;
    USE SIGNAL ;
    PORT
      LAYER M3 ;
        RECT 240.156 0.000 240.174 0.144 ;
    END
  END up_in[303]
  PIN up_in[304]
    DIRECTION INPUT ;
    USE SIGNAL ;
    PORT
      LAYER M5 ;
        RECT 240.480 0.000 240.504 0.192 ;
    END
  END up_in[304]
  PIN up_in[305]
    DIRECTION INPUT ;
    USE SIGNAL ;
    PORT
      LAYER M3 ;
        RECT 240.876 0.000 240.894 0.144 ;
    END
  END up_in[305]
  PIN up_in[306]
    DIRECTION INPUT ;
    USE SIGNAL ;
    PORT
      LAYER M5 ;
        RECT 241.248 0.000 241.272 0.192 ;
    END
  END up_in[306]
  PIN up_in[307]
    DIRECTION INPUT ;
    USE SIGNAL ;
    PORT
      LAYER M3 ;
        RECT 241.596 0.000 241.614 0.144 ;
    END
  END up_in[307]
  PIN up_in[308]
    DIRECTION INPUT ;
    USE SIGNAL ;
    PORT
      LAYER M5 ;
        RECT 241.968 0.000 241.992 0.192 ;
    END
  END up_in[308]
  PIN up_in[309]
    DIRECTION INPUT ;
    USE SIGNAL ;
    PORT
      LAYER M3 ;
        RECT 242.316 0.000 242.334 0.144 ;
    END
  END up_in[309]
  PIN up_in[310]
    DIRECTION INPUT ;
    USE SIGNAL ;
    PORT
      LAYER M5 ;
        RECT 242.688 0.000 242.712 0.192 ;
    END
  END up_in[310]
  PIN up_in[311]
    DIRECTION INPUT ;
    USE SIGNAL ;
    PORT
      LAYER M3 ;
        RECT 243.036 0.000 243.054 0.144 ;
    END
  END up_in[311]
  PIN up_in[312]
    DIRECTION INPUT ;
    USE SIGNAL ;
    PORT
      LAYER M5 ;
        RECT 243.408 0.000 243.432 0.192 ;
    END
  END up_in[312]
  PIN up_in[313]
    DIRECTION INPUT ;
    USE SIGNAL ;
    PORT
      LAYER M3 ;
        RECT 243.792 0.000 243.810 0.144 ;
    END
  END up_in[313]
  PIN up_in[314]
    DIRECTION INPUT ;
    USE SIGNAL ;
    PORT
      LAYER M5 ;
        RECT 244.128 0.000 244.152 0.192 ;
    END
  END up_in[314]
  PIN up_in[315]
    DIRECTION INPUT ;
    USE SIGNAL ;
    PORT
      LAYER M3 ;
        RECT 244.512 0.000 244.530 0.144 ;
    END
  END up_in[315]
  PIN up_in[316]
    DIRECTION INPUT ;
    USE SIGNAL ;
    PORT
      LAYER M5 ;
        RECT 244.848 0.000 244.872 0.192 ;
    END
  END up_in[316]
  PIN up_in[317]
    DIRECTION INPUT ;
    USE SIGNAL ;
    PORT
      LAYER M3 ;
        RECT 245.232 0.000 245.250 0.144 ;
    END
  END up_in[317]
  PIN up_in[318]
    DIRECTION INPUT ;
    USE SIGNAL ;
    PORT
      LAYER M5 ;
        RECT 245.616 0.000 245.640 0.192 ;
    END
  END up_in[318]
  PIN up_in[319]
    DIRECTION INPUT ;
    USE SIGNAL ;
    PORT
      LAYER M3 ;
        RECT 245.952 0.000 245.970 0.144 ;
    END
  END up_in[319]
  PIN up_in[320]
    DIRECTION INPUT ;
    USE SIGNAL ;
    PORT
      LAYER M5 ;
        RECT 246.336 0.000 246.360 0.192 ;
    END
  END up_in[320]
  PIN up_in[321]
    DIRECTION INPUT ;
    USE SIGNAL ;
    PORT
      LAYER M3 ;
        RECT 246.672 0.000 246.690 0.144 ;
    END
  END up_in[321]
  PIN up_in[322]
    DIRECTION INPUT ;
    USE SIGNAL ;
    PORT
      LAYER M5 ;
        RECT 247.056 0.000 247.080 0.192 ;
    END
  END up_in[322]
  PIN up_in[323]
    DIRECTION INPUT ;
    USE SIGNAL ;
    PORT
      LAYER M3 ;
        RECT 247.428 0.000 247.446 0.144 ;
    END
  END up_in[323]
  PIN up_in[324]
    DIRECTION INPUT ;
    USE SIGNAL ;
    PORT
      LAYER M5 ;
        RECT 247.776 0.000 247.800 0.192 ;
    END
  END up_in[324]
  PIN up_in[325]
    DIRECTION INPUT ;
    USE SIGNAL ;
    PORT
      LAYER M3 ;
        RECT 248.148 0.000 248.166 0.144 ;
    END
  END up_in[325]
  PIN up_in[326]
    DIRECTION INPUT ;
    USE SIGNAL ;
    PORT
      LAYER M5 ;
        RECT 248.496 0.000 248.520 0.192 ;
    END
  END up_in[326]
  PIN up_in[327]
    DIRECTION INPUT ;
    USE SIGNAL ;
    PORT
      LAYER M3 ;
        RECT 248.868 0.000 248.886 0.144 ;
    END
  END up_in[327]
  PIN up_in[328]
    DIRECTION INPUT ;
    USE SIGNAL ;
    PORT
      LAYER M5 ;
        RECT 249.216 0.000 249.240 0.192 ;
    END
  END up_in[328]
  PIN up_in[329]
    DIRECTION INPUT ;
    USE SIGNAL ;
    PORT
      LAYER M3 ;
        RECT 249.588 0.000 249.606 0.144 ;
    END
  END up_in[329]
  PIN up_in[330]
    DIRECTION INPUT ;
    USE SIGNAL ;
    PORT
      LAYER M5 ;
        RECT 249.936 0.000 249.960 0.192 ;
    END
  END up_in[330]
  PIN up_in[331]
    DIRECTION INPUT ;
    USE SIGNAL ;
    PORT
      LAYER M3 ;
        RECT 250.308 0.000 250.326 0.144 ;
    END
  END up_in[331]
  PIN up_in[332]
    DIRECTION INPUT ;
    USE SIGNAL ;
    PORT
      LAYER M5 ;
        RECT 250.704 0.000 250.728 0.192 ;
    END
  END up_in[332]
  PIN up_in[333]
    DIRECTION INPUT ;
    USE SIGNAL ;
    PORT
      LAYER M3 ;
        RECT 251.064 0.000 251.082 0.144 ;
    END
  END up_in[333]
  PIN up_in[334]
    DIRECTION INPUT ;
    USE SIGNAL ;
    PORT
      LAYER M5 ;
        RECT 251.424 0.000 251.448 0.192 ;
    END
  END up_in[334]
  PIN up_in[335]
    DIRECTION INPUT ;
    USE SIGNAL ;
    PORT
      LAYER M3 ;
        RECT 251.784 0.000 251.802 0.144 ;
    END
  END up_in[335]
  PIN up_in[336]
    DIRECTION INPUT ;
    USE SIGNAL ;
    PORT
      LAYER M5 ;
        RECT 252.144 0.000 252.168 0.192 ;
    END
  END up_in[336]
  PIN up_in[337]
    DIRECTION INPUT ;
    USE SIGNAL ;
    PORT
      LAYER M3 ;
        RECT 252.504 0.000 252.522 0.144 ;
    END
  END up_in[337]
  PIN up_in[338]
    DIRECTION INPUT ;
    USE SIGNAL ;
    PORT
      LAYER M5 ;
        RECT 252.864 0.000 252.888 0.192 ;
    END
  END up_in[338]
  PIN up_in[339]
    DIRECTION INPUT ;
    USE SIGNAL ;
    PORT
      LAYER M3 ;
        RECT 253.224 0.000 253.242 0.144 ;
    END
  END up_in[339]
  PIN up_in[340]
    DIRECTION INPUT ;
    USE SIGNAL ;
    PORT
      LAYER M5 ;
        RECT 253.584 0.000 253.608 0.192 ;
    END
  END up_in[340]
  PIN up_in[341]
    DIRECTION INPUT ;
    USE SIGNAL ;
    PORT
      LAYER M3 ;
        RECT 253.944 0.000 253.962 0.144 ;
    END
  END up_in[341]
  PIN up_in[342]
    DIRECTION INPUT ;
    USE SIGNAL ;
    PORT
      LAYER M5 ;
        RECT 254.304 0.000 254.328 0.192 ;
    END
  END up_in[342]
  PIN up_in[343]
    DIRECTION INPUT ;
    USE SIGNAL ;
    PORT
      LAYER M3 ;
        RECT 254.700 0.000 254.718 0.144 ;
    END
  END up_in[343]
  PIN clr
    DIRECTION INPUT ;
    USE SIGNAL ;
    PORT
      LAYER M4 ;
        RECT 0.000 46.032 0.192 46.056 ;
    END
  END clr
  PIN conv
    DIRECTION INPUT ;
    USE SIGNAL ;
    PORT
      LAYER M4 ;
        RECT 0.000 129.600 0.192 129.624 ;
    END
  END conv
  PIN busy
    DIRECTION OUTPUT ;
    USE SIGNAL ;
    PORT
      LAYER M4 ;
        RECT 0.000 213.120 0.192 213.144 ;
    END
  END busy
  PIN VDD
    DIRECTION INOUT ;
    USE POWER ;
    PORT
      LAYER M5 ;
        RECT 2.460 0.500 2.580 258.700 ;
        RECT 7.860 0.500 7.980 258.700 ;
        RECT 13.260 0.500 13.380 258.700 ;
        RECT 18.660 0.500 18.780 258.700 ;
        RECT 24.060 0.500 24.180 258.700 ;
        RECT 29.460 0.500 29.580 258.700 ;
        RECT 34.860 0.500 34.980 258.700 ;
        RECT 40.260 0.500 40.380 258.700 ;
        RECT 45.660 0.500 45.780 258.700 ;
        RECT 51.060 0.500 51.180 258.700 ;
        RECT 56.460 0.500 56.580 258.700 ;
        RECT 61.860 0.500 61.980 258.700 ;
        RECT 67.260 0.500 67.380 258.700 ;
        RECT 72.660 0.500 72.780 258.700 ;
        RECT 78.060 0.500 78.180 258.700 ;
        RECT 83.460 0.500 83.580 258.700 ;
        RECT 88.860 0.500 88.980 258.700 ;
        RECT 94.260 0.500 94.380 258.700 ;
        RECT 99.660 0.500 99.780 258.700 ;
        RECT 105.060 0.500 105.180 258.700 ;
        RECT 110.460 0.500 110.580 258.700 ;
        RECT 115.860 0.500 115.980 258.700 ;
        RECT 121.260 0.500 121.380 258.700 ;
        RECT 126.660 0.500 126.780 258.700 ;
        RECT 132.060 0.500 132.180 258.700 ;
        RECT 137.460 0.500 137.580 258.700 ;
        RECT 142.860 0.500 142.980 258.700 ;
        RECT 148.260 0.500 148.380 258.700 ;
        RECT 153.660 0.500 153.780 258.700 ;
        RECT 159.060 0.500 159.180 258.700 ;
        RECT 164.460 0.500 164.580 258.700 ;
        RECT 169.860 0.500 169.980 258.700 ;
        RECT 175.260 0.500 175.380 258.700 ;
        RECT 180.660 0.500 180.780 258.700 ;
        RECT 186.060 0.500 186.180 258.700 ;
        RECT 191.460 0.500 191.580 258.700 ;
        RECT 196.860 0.500 196.980 258.700 ;
        RECT 202.260 0.500 202.380 258.700 ;
        RECT 207.660 0.500 207.780 258.700 ;
        RECT 213.060 0.500 213.180 258.700 ;
        RECT 218.460 0.500 218.580 258.700 ;
        RECT 223.860 0.500 223.980 258.700 ;
        RECT 229.260 0.500 229.380 258.700 ;
        RECT 234.660 0.500 234.780 258.700 ;
        RECT 240.060 0.500 240.180 258.700 ;
        RECT 245.460 0.500 245.580 258.700 ;
        RECT 250.860 0.500 250.980 258.700 ;
        RECT 256.260 0.500 256.380 258.700 ;
    END
  END VDD
  PIN VSS
    DIRECTION INOUT ;
    USE GROUND ;
    PORT
      LAYER M5 ;
        RECT 2.652 0.500 2.772 258.700 ;
        RECT 8.052 0.500 8.172 258.700 ;
        RECT 13.452 0.500 13.572 258.700 ;
        RECT 18.852 0.500 18.972 258.700 ;
        RECT 24.252 0.500 24.372 258.700 ;
        RECT 29.652 0.500 29.772 258.700 ;
        RECT 35.052 0.500 35.172 258.700 ;
        RECT 40.452 0.500 40.572 258.700 ;
        RECT 45.852 0.500 45.972 258.700 ;
        RECT 51.252 0.500 51.372 258.700 ;
        RECT 56.652 0.500 56.772 258.700 ;
        RECT 62.052 0.500 62.172 258.700 ;
        RECT 67.452 0.500 67.572 258.700 ;
        RECT 72.852 0.500 72.972 258.700 ;
        RECT 78.252 0.500 78.372 258.700 ;
        RECT 83.652 0.500 83.772 258.700 ;
        RECT 89.052 0.500 89.172 258.700 ;
        RECT 94.452 0.500 94.572 258.700 ;
        RECT 99.852 0.500 99.972 258.700 ;
        RECT 105.252 0.500 105.372 258.700 ;
        RECT 110.652 0.500 110.772 258.700 ;
        RECT 116.052 0.500 116.172 258.700 ;
        RECT 121.452 0.500 121.572 258.700 ;
        RECT 126.852 0.500 126.972 258.700 ;
        RECT 132.252 0.500 132.372 258.700 ;
        RECT 137.652 0.500 137.772 258.700 ;
        RECT 143.052 0.500 143.172 258.700 ;
        RECT 148.452 0.500 148.572 258.700 ;
        RECT 153.852 0.500 153.972 258.700 ;
        RECT 159.252 0.500 159.372 258.700 ;
        RECT 164.652 0.500 164.772 258.700 ;
        RECT 170.052 0.500 170.172 258.700 ;
        RECT 175.452 0.500 175.572 258.700 ;
        RECT 180.852 0.500 180.972 258.700 ;
        RECT 186.252 0.500 186.372 258.700 ;
        RECT 191.652 0.500 191.772 258.700 ;
        RECT 197.052 0.500 197.172 258.700 ;
        RECT 202.452 0.500 202.572 258.700 ;
        RECT 207.852 0.500 207.972 258.700 ;
        RECT 213.252 0.500 213.372 258.700 ;
        RECT 218.652 0.500 218.772 258.700 ;
        RECT 224.052 0.500 224.172 258.700 ;
        RECT 229.452 0.500 229.572 258.700 ;
        RECT 234.852 0.500 234.972 258.700 ;
        RECT 240.252 0.500 240.372 258.700 ;
        RECT 245.652 0.500 245.772 258.700 ;
        RECT 251.052 0.500 251.172 258.700 ;
        RECT 256.452 0.500 256.572 258.700 ;
    END
  END VSS
  OBS
    LAYER M1 ;
      RECT 0.500 0.500 258.700 258.700 ;
    LAYER M2 ;
      RECT 0.500 0.500 258.700 258.700 ;
    LAYER M3 ;
      RECT 0.500 10.800 10.800 35.232 ;
      RECT 0.500 56.856 10.800 118.800 ;
      RECT 0.500 140.424 10.800 202.320 ;
      RECT 0.500 223.944 10.800 248.400 ;
      RECT 10.800 10.800 258.700 248.400 ;
    LAYER M4 ;
      RECT 0.500 10.800 10.800 35.232 ;
      RECT 0.500 56.856 10.800 118.800 ;
      RECT 0.500 140.424 10.800 202.320 ;
      RECT 0.500 223.944 10.800 248.400 ;
      RECT 10.800 10.800 258.700 248.400 ;
    LAYER M5 ;
      RECT 0.500 10.800 2.460 35.232 ;
      RECT 0.500 56.856 2.460 118.800 ;
      RECT 0.500 140.424 2.460 202.320 ;
      RECT 0.500 223.944 2.460 248.400 ;
      RECT 2.580 10.800 2.652 35.232 ;
      RECT 2.580 56.856 2.652 118.800 ;
      RECT 2.580 140.424 2.652 202.320 ;
      RECT 2.580 223.944 2.652 248.400 ;
      RECT 2.772 10.800 7.860 35.232 ;
      RECT 2.772 56.856 7.860 118.800 ;
      RECT 2.772 140.424 7.860 202.320 ;
      RECT 2.772 223.944 7.860 248.400 ;
      RECT 7.980 10.800 8.052 35.232 ;
      RECT 7.980 56.856 8.052 118.800 ;
      RECT 7.980 140.424 8.052 202.320 ;
      RECT 7.980 223.944 8.052 248.400 ;
      RECT 8.172 10.800 10.800 35.232 ;
      RECT 8.172 56.856 10.800 118.800 ;
      RECT 8.172 140.424 10.800 202.320 ;
      RECT 8.172 223.944 10.800 248.400 ;
      RECT 10.800 10.800 13.260 248.400 ;
      RECT 13.380 10.800 13.452 248.400 ;
      RECT 13.572 10.800 18.660 248.400 ;
      RECT 18.780 10.800 18.852 248.400 ;
      RECT 18.972 10.800 24.060 248.400 ;
      RECT 24.180 10.800 24.252 248.400 ;
      RECT 24.372 10.800 29.460 248.400 ;
      RECT 29.580 10.800 29.652 248.400 ;
      RECT 29.772 10.800 34.860 248.400 ;
      RECT 34.980 10.800 35.052 248.400 ;
      RECT 35.172 10.800 40.260 248.400 ;
      RECT 40.380 10.800 40.452 248.400 ;
      RECT 40.572 10.800 45.660 248.400 ;
      RECT 45.780 10.800 45.852 248.400 ;
      RECT 45.972 10.800 51.060 248.400 ;
      RECT 51.180 10.800 51.252 248.400 ;
      RECT 51.372 10.800 56.460 248.400 ;
      RECT 56.580 10.800 56.652 248.400 ;
      RECT 56.772 10.800 61.860 248.400 ;
      RECT 61.980 10.800 62.052 248.400 ;
      RECT 62.172 10.800 67.260 248.400 ;
      RECT 67.380 10.800 67.452 248.400 ;
      RECT 67.572 10.800 72.660 248.400 ;
      RECT 72.780 10.800 72.852 248.400 ;
      RECT 72.972 10.800 78.060 248.400 ;
      RECT 78.180 10.800 78.252 248.400 ;
      RECT 78.372 10.800 83.460 248.400 ;
      RECT 83.580 10.800 83.652 248.400 ;
      RECT 83.772 10.800 88.860 248.400 ;
      RECT 88.980 10.800 89.052 248.400 ;
      RECT 89.172 10.800 94.260 248.400 ;
      RECT 94.380 10.800 94.452 248.400 ;
      RECT 94.572 10.800 99.660 248.400 ;
      RECT 99.780 10.800 99.852 248.400 ;
      RECT 99.972 10.800 105.060 248.400 ;
      RECT 105.180 10.800 105.252 248.400 ;
      RECT 105.372 10.800 110.460 248.400 ;
      RECT 110.580 10.800 110.652 248.400 ;
      RECT 110.772 10.800 115.860 248.400 ;
      RECT 115.980 10.800 116.052 248.400 ;
      RECT 116.172 10.800 121.260 248.400 ;
      RECT 121.380 10.800 121.452 248.400 ;
      RECT 121.572 10.800 126.660 248.400 ;
      RECT 126.780 10.800 126.852 248.400 ;
      RECT 126.972 10.800 132.060 248.400 ;
      RECT 132.180 10.800 132.252 248.400 ;
      RECT 132.372 10.800 137.460 248.400 ;
      RECT 137.580 10.800 137.652 248.400 ;
      RECT 137.772 10.800 142.860 248.400 ;
      RECT 142.980 10.800 143.052 248.400 ;
      RECT 143.172 10.800 148.260 248.400 ;
      RECT 148.380 10.800 148.452 248.400 ;
      RECT 148.572 10.800 153.660 248.400 ;
      RECT 153.780 10.800 153.852 248.400 ;
      RECT 153.972 10.800 159.060 248.400 ;
      RECT 159.180 10.800 159.252 248.400 ;
      RECT 159.372 10.800 164.460 248.400 ;
      RECT 164.580 10.800 164.652 248.400 ;
      RECT 164.772 10.800 169.860 248.400 ;
      RECT 169.980 10.800 170.052 248.400 ;
      RECT 170.172 10.800 175.260 248.400 ;
      RECT 175.380 10.800 175.452 248.400 ;
      RECT 175.572 10.800 180.660 248.400 ;
      RECT 180.780 10.800 180.852 248.400 ;
      RECT 180.972 10.800 186.060 248.400 ;
      RECT 186.180 10.800 186.252 248.400 ;
      RECT 186.372 10.800 191.460 248.400 ;
      RECT 191.580 10.800 191.652 248.400 ;
      RECT 191.772 10.800 196.860 248.400 ;
      RECT 196.980 10.800 197.052 248.400 ;
      RECT 197.172 10.800 202.260 248.400 ;
      RECT 202.380 10.800 202.452 248.400 ;
      RECT 202.572 10.800 207.660 248.400 ;
      RECT 207.780 10.800 207.852 248.400 ;
      RECT 207.972 10.800 213.060 248.400 ;
      RECT 213.180 10.800 213.252 248.400 ;
      RECT 213.372 10.800 218.460 248.400 ;
      RECT 218.580 10.800 218.652 248.400 ;
      RECT 218.772 10.800 223.860 248.400 ;
      RECT 223.980 10.800 224.052 248.400 ;
      RECT 224.172 10.800 229.260 248.400 ;
      RECT 229.380 10.800 229.452 248.400 ;
      RECT 229.572 10.800 234.660 248.400 ;
      RECT 234.780 10.800 234.852 248.400 ;
      RECT 234.972 10.800 240.060 248.400 ;
      RECT 240.180 10.800 240.252 248.400 ;
      RECT 240.372 10.800 245.460 248.400 ;
      RECT 245.580 10.800 245.652 248.400 ;
      RECT 245.772 10.800 250.860 248.400 ;
      RECT 250.980 10.800 251.052 248.400 ;
      RECT 251.172 10.800 256.260 248.400 ;
      RECT 256.380 10.800 256.452 248.400 ;
      RECT 256.572 10.800 258.700 248.400 ;
  END
END ot_hgi_coll_tkm_tile_e86
END LIBRARY
